VERSION 5.8 ;
BUSBITCHARS "[]" ;
DIVIDERCHAR "/" ;
UNITS
    DATABASE MICRONS 1000 ;
END UNITS

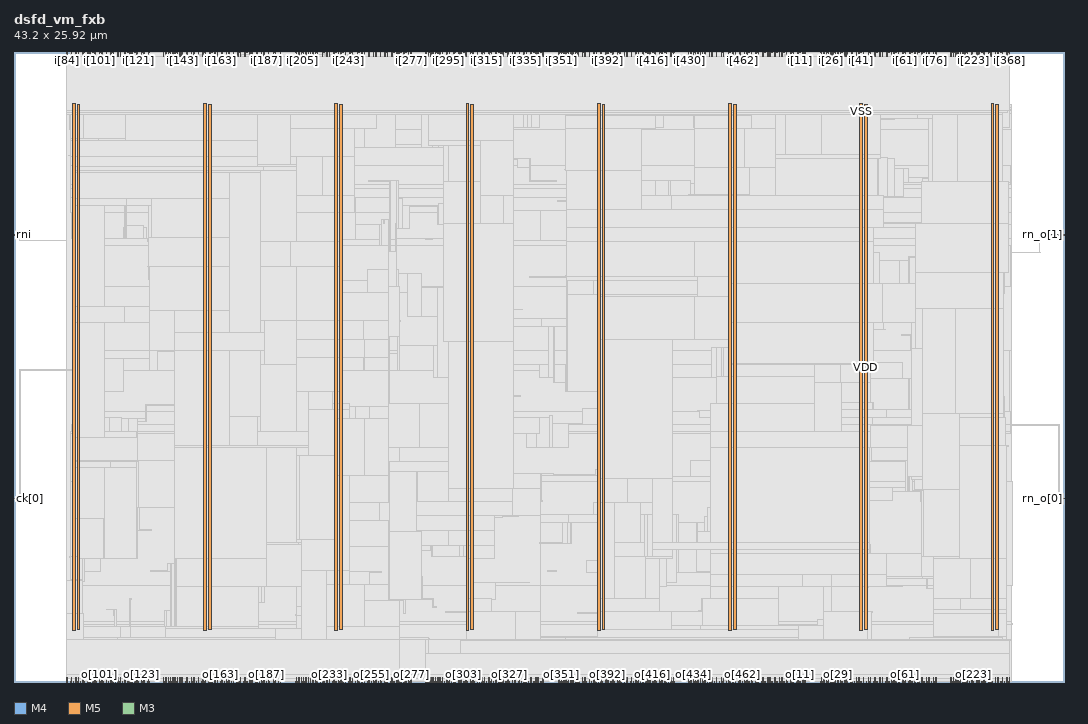
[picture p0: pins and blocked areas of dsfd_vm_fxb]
MACRO dsfd_vm_fxb
  FOREIGN dsfd_vm_fxb 0 0 ;
  CLASS BLOCK ;
  SIZE 43.2 BY 25.92 ;
  PIN ck[0]
    DIRECTION INPUT ;
    USE SIGNAL ;
    PORT
      LAYER M4 ;
        RECT  0 7.536 0.192 7.56 ;
    END
    PORT
      LAYER M4 ;
        RECT  0.156 7.536 0.275 7.56 ;
    END
  END ck[0]
  PIN i[0]
    DIRECTION INPUT ;
    USE SIGNAL ;
    PORT
      LAYER M5 ;
        RECT  31.488 25.728 31.512 25.92 ;
    END
  END i[0]
  PIN i[100]
    DIRECTION INPUT ;
    USE SIGNAL ;
    PORT
      LAYER M5 ;
        RECT  3.504 25.728 3.528 25.92 ;
    END
  END i[100]
  PIN i[101]
    DIRECTION INPUT ;
    USE SIGNAL ;
    PORT
      LAYER M3 ;
        RECT  3.528 25.882 3.546 25.92 ;
    END
  END i[101]
  PIN i[102]
    DIRECTION INPUT ;
    USE SIGNAL ;
    PORT
      LAYER M5 ;
        RECT  3.6 25.728 3.624 25.92 ;
    END
  END i[102]
  PIN i[103]
    DIRECTION INPUT ;
    USE SIGNAL ;
    PORT
      LAYER M3 ;
        RECT  3.672 25.882 3.69 25.92 ;
    END
  END i[103]
  PIN i[104]
    DIRECTION INPUT ;
    USE SIGNAL ;
    PORT
      LAYER M5 ;
        RECT  3.792 25.728 3.816 25.92 ;
    END
  END i[104]
  PIN i[105]
    DIRECTION INPUT ;
    USE SIGNAL ;
    PORT
      LAYER M3 ;
        RECT  3.888 25.882 3.906 25.92 ;
    END
  END i[105]
  PIN i[106]
    DIRECTION INPUT ;
    USE SIGNAL ;
    PORT
      LAYER M5 ;
        RECT  3.984 25.728 4.008 25.92 ;
    END
  END i[106]
  PIN i[107]
    DIRECTION INPUT ;
    USE SIGNAL ;
    PORT
      LAYER M3 ;
        RECT  4.032 25.882 4.05 25.92 ;
    END
  END i[107]
  PIN i[108]
    DIRECTION INPUT ;
    USE SIGNAL ;
    PORT
      LAYER M5 ;
        RECT  4.08 25.728 4.104 25.92 ;
    END
  END i[108]
  PIN i[109]
    DIRECTION INPUT ;
    USE SIGNAL ;
    PORT
      LAYER M3 ;
        RECT  4.176 25.882 4.194 25.92 ;
    END
  END i[109]
  PIN i[10]
    DIRECTION INPUT ;
    USE SIGNAL ;
    PORT
      LAYER M5 ;
        RECT  32.256 25.728 32.28 25.92 ;
    END
  END i[10]
  PIN i[110]
    DIRECTION INPUT ;
    USE SIGNAL ;
    PORT
      LAYER M5 ;
        RECT  4.272 25.728 4.296 25.92 ;
    END
  END i[110]
  PIN i[111]
    DIRECTION INPUT ;
    USE SIGNAL ;
    PORT
      LAYER M3 ;
        RECT  4.32 25.882 4.338 25.92 ;
    END
  END i[111]
  PIN i[112]
    DIRECTION INPUT ;
    USE SIGNAL ;
    PORT
      LAYER M5 ;
        RECT  4.368 25.728 4.392 25.92 ;
    END
  END i[112]
  PIN i[113]
    DIRECTION INPUT ;
    USE SIGNAL ;
    PORT
      LAYER M3 ;
        RECT  4.464 25.882 4.482 25.92 ;
    END
  END i[113]
  PIN i[114]
    DIRECTION INPUT ;
    USE SIGNAL ;
    PORT
      LAYER M5 ;
        RECT  4.56 25.728 4.584 25.92 ;
    END
  END i[114]
  PIN i[115]
    DIRECTION INPUT ;
    USE SIGNAL ;
    PORT
      LAYER M3 ;
        RECT  4.68 25.882 4.698 25.92 ;
    END
  END i[115]
  PIN i[116]
    DIRECTION INPUT ;
    USE SIGNAL ;
    PORT
      LAYER M5 ;
        RECT  4.752 25.728 4.776 25.92 ;
    END
  END i[116]
  PIN i[117]
    DIRECTION INPUT ;
    USE SIGNAL ;
    PORT
      LAYER M3 ;
        RECT  4.824 25.882 4.842 25.92 ;
    END
  END i[117]
  PIN i[118]
    DIRECTION INPUT ;
    USE SIGNAL ;
    PORT
      LAYER M5 ;
        RECT  4.848 25.728 4.872 25.92 ;
    END
  END i[118]
  PIN i[119]
    DIRECTION INPUT ;
    USE SIGNAL ;
    PORT
      LAYER M3 ;
        RECT  4.968 25.882 4.986 25.92 ;
    END
  END i[119]
  PIN i[11]
    DIRECTION INPUT ;
    USE SIGNAL ;
    PORT
      LAYER M3 ;
        RECT  32.328 25.882 32.346 25.92 ;
    END
  END i[11]
  PIN i[120]
    DIRECTION INPUT ;
    USE SIGNAL ;
    PORT
      LAYER M5 ;
        RECT  5.04 25.728 5.064 25.92 ;
    END
  END i[120]
  PIN i[121]
    DIRECTION INPUT ;
    USE SIGNAL ;
    PORT
      LAYER M3 ;
        RECT  5.112 25.882 5.13 25.92 ;
    END
  END i[121]
  PIN i[122]
    DIRECTION INPUT ;
    USE SIGNAL ;
    PORT
      LAYER M5 ;
        RECT  5.232 25.728 5.256 25.92 ;
    END
  END i[122]
  PIN i[123]
    DIRECTION INPUT ;
    USE SIGNAL ;
    PORT
      LAYER M3 ;
        RECT  5.256 25.882 5.274 25.92 ;
    END
  END i[123]
  PIN i[124]
    DIRECTION INPUT ;
    USE SIGNAL ;
    PORT
      LAYER M5 ;
        RECT  5.328 25.728 5.352 25.92 ;
    END
  END i[124]
  PIN i[125]
    DIRECTION INPUT ;
    USE SIGNAL ;
    PORT
      LAYER M3 ;
        RECT  5.472 25.882 5.49 25.92 ;
    END
  END i[125]
  PIN i[126]
    DIRECTION INPUT ;
    USE SIGNAL ;
    PORT
      LAYER M5 ;
        RECT  5.52 25.728 5.544 25.92 ;
    END
  END i[126]
  PIN i[127]
    DIRECTION INPUT ;
    USE SIGNAL ;
    PORT
      LAYER M3 ;
        RECT  5.544 25.882 5.562 25.92 ;
    END
  END i[127]
  PIN i[128]
    DIRECTION INPUT ;
    USE SIGNAL ;
    PORT
      LAYER M5 ;
        RECT  6.144 25.728 6.168 25.92 ;
    END
  END i[128]
  PIN i[129]
    DIRECTION INPUT ;
    USE SIGNAL ;
    PORT
      LAYER M3 ;
        RECT  6.192 25.882 6.21 25.92 ;
    END
  END i[129]
  PIN i[12]
    DIRECTION INPUT ;
    USE SIGNAL ;
    PORT
      LAYER M5 ;
        RECT  32.448 25.728 32.472 25.92 ;
    END
  END i[12]
  PIN i[130]
    DIRECTION INPUT ;
    USE SIGNAL ;
    PORT
      LAYER M5 ;
        RECT  6.24 25.728 6.264 25.92 ;
    END
  END i[130]
  PIN i[131]
    DIRECTION INPUT ;
    USE SIGNAL ;
    PORT
      LAYER M3 ;
        RECT  6.264 25.882 6.282 25.92 ;
    END
  END i[131]
  PIN i[132]
    DIRECTION INPUT ;
    USE SIGNAL ;
    PORT
      LAYER M5 ;
        RECT  6.336 25.728 6.36 25.92 ;
    END
  END i[132]
  PIN i[133]
    DIRECTION INPUT ;
    USE SIGNAL ;
    PORT
      LAYER M3 ;
        RECT  6.336 25.882 6.354 25.92 ;
    END
  END i[133]
  PIN i[134]
    DIRECTION INPUT ;
    USE SIGNAL ;
    PORT
      LAYER M5 ;
        RECT  6.432 25.728 6.456 25.92 ;
    END
  END i[134]
  PIN i[135]
    DIRECTION INPUT ;
    USE SIGNAL ;
    PORT
      LAYER M3 ;
        RECT  6.408 25.882 6.426 25.92 ;
    END
  END i[135]
  PIN i[136]
    DIRECTION INPUT ;
    USE SIGNAL ;
    PORT
      LAYER M5 ;
        RECT  6.528 25.728 6.552 25.92 ;
    END
  END i[136]
  PIN i[137]
    DIRECTION INPUT ;
    USE SIGNAL ;
    PORT
      LAYER M3 ;
        RECT  6.48 25.882 6.498 25.92 ;
    END
  END i[137]
  PIN i[138]
    DIRECTION INPUT ;
    USE SIGNAL ;
    PORT
      LAYER M5 ;
        RECT  6.624 25.728 6.648 25.92 ;
    END
  END i[138]
  PIN i[139]
    DIRECTION INPUT ;
    USE SIGNAL ;
    PORT
      LAYER M3 ;
        RECT  6.552 25.882 6.57 25.92 ;
    END
  END i[139]
  PIN i[13]
    DIRECTION INPUT ;
    USE SIGNAL ;
    PORT
      LAYER M3 ;
        RECT  32.472 25.882 32.49 25.92 ;
    END
  END i[13]
  PIN i[140]
    DIRECTION INPUT ;
    USE SIGNAL ;
    PORT
      LAYER M5 ;
        RECT  6.72 25.728 6.744 25.92 ;
    END
  END i[140]
  PIN i[141]
    DIRECTION INPUT ;
    USE SIGNAL ;
    PORT
      LAYER M3 ;
        RECT  6.696 25.882 6.714 25.92 ;
    END
  END i[141]
  PIN i[142]
    DIRECTION INPUT ;
    USE SIGNAL ;
    PORT
      LAYER M5 ;
        RECT  6.816 25.728 6.84 25.92 ;
    END
  END i[142]
  PIN i[143]
    DIRECTION INPUT ;
    USE SIGNAL ;
    PORT
      LAYER M3 ;
        RECT  6.912 25.882 6.93 25.92 ;
    END
  END i[143]
  PIN i[144]
    DIRECTION INPUT ;
    USE SIGNAL ;
    PORT
      LAYER M5 ;
        RECT  6.912 25.728 6.936 25.92 ;
    END
  END i[144]
  PIN i[145]
    DIRECTION INPUT ;
    USE SIGNAL ;
    PORT
      LAYER M3 ;
        RECT  7.056 25.882 7.074 25.92 ;
    END
  END i[145]
  PIN i[146]
    DIRECTION INPUT ;
    USE SIGNAL ;
    PORT
      LAYER M5 ;
        RECT  7.104 25.728 7.128 25.92 ;
    END
  END i[146]
  PIN i[147]
    DIRECTION INPUT ;
    USE SIGNAL ;
    PORT
      LAYER M3 ;
        RECT  7.2 25.882 7.218 25.92 ;
    END
  END i[147]
  PIN i[148]
    DIRECTION INPUT ;
    USE SIGNAL ;
    PORT
      LAYER M5 ;
        RECT  7.296 25.728 7.32 25.92 ;
    END
  END i[148]
  PIN i[149]
    DIRECTION INPUT ;
    USE SIGNAL ;
    PORT
      LAYER M3 ;
        RECT  7.344 25.882 7.362 25.92 ;
    END
  END i[149]
  PIN i[14]
    DIRECTION INPUT ;
    USE SIGNAL ;
    PORT
      LAYER M3 ;
        RECT  32.544 25.882 32.562 25.92 ;
    END
  END i[14]
  PIN i[150]
    DIRECTION INPUT ;
    USE SIGNAL ;
    PORT
      LAYER M5 ;
        RECT  7.392 25.728 7.416 25.92 ;
    END
  END i[150]
  PIN i[151]
    DIRECTION INPUT ;
    USE SIGNAL ;
    PORT
      LAYER M3 ;
        RECT  7.488 25.882 7.506 25.92 ;
    END
  END i[151]
  PIN i[152]
    DIRECTION INPUT ;
    USE SIGNAL ;
    PORT
      LAYER M5 ;
        RECT  7.584 25.728 7.608 25.92 ;
    END
  END i[152]
  PIN i[153]
    DIRECTION INPUT ;
    USE SIGNAL ;
    PORT
      LAYER M3 ;
        RECT  7.704 25.882 7.722 25.92 ;
    END
  END i[153]
  PIN i[154]
    DIRECTION INPUT ;
    USE SIGNAL ;
    PORT
      LAYER M5 ;
        RECT  7.776 25.728 7.8 25.92 ;
    END
  END i[154]
  PIN i[155]
    DIRECTION INPUT ;
    USE SIGNAL ;
    PORT
      LAYER M3 ;
        RECT  7.848 25.882 7.866 25.92 ;
    END
  END i[155]
  PIN i[156]
    DIRECTION INPUT ;
    USE SIGNAL ;
    PORT
      LAYER M5 ;
        RECT  7.872 25.728 7.896 25.92 ;
    END
  END i[156]
  PIN i[157]
    DIRECTION INPUT ;
    USE SIGNAL ;
    PORT
      LAYER M3 ;
        RECT  7.992 25.882 8.01 25.92 ;
    END
  END i[157]
  PIN i[158]
    DIRECTION INPUT ;
    USE SIGNAL ;
    PORT
      LAYER M5 ;
        RECT  8.064 25.728 8.088 25.92 ;
    END
  END i[158]
  PIN i[159]
    DIRECTION INPUT ;
    USE SIGNAL ;
    PORT
      LAYER M3 ;
        RECT  8.136 25.882 8.154 25.92 ;
    END
  END i[159]
  PIN i[15]
    DIRECTION INPUT ;
    USE SIGNAL ;
    PORT
      LAYER M5 ;
        RECT  33.216 25.728 33.24 25.92 ;
    END
  END i[15]
  PIN i[160]
    DIRECTION INPUT ;
    USE SIGNAL ;
    PORT
      LAYER M5 ;
        RECT  8.256 25.728 8.28 25.92 ;
    END
  END i[160]
  PIN i[161]
    DIRECTION INPUT ;
    USE SIGNAL ;
    PORT
      LAYER M3 ;
        RECT  8.28 25.882 8.298 25.92 ;
    END
  END i[161]
  PIN i[162]
    DIRECTION INPUT ;
    USE SIGNAL ;
    PORT
      LAYER M5 ;
        RECT  8.352 25.728 8.376 25.92 ;
    END
  END i[162]
  PIN i[163]
    DIRECTION INPUT ;
    USE SIGNAL ;
    PORT
      LAYER M3 ;
        RECT  8.496 25.882 8.514 25.92 ;
    END
  END i[163]
  PIN i[164]
    DIRECTION INPUT ;
    USE SIGNAL ;
    PORT
      LAYER M5 ;
        RECT  8.544 25.728 8.568 25.92 ;
    END
  END i[164]
  PIN i[165]
    DIRECTION INPUT ;
    USE SIGNAL ;
    PORT
      LAYER M3 ;
        RECT  8.64 25.882 8.658 25.92 ;
    END
  END i[165]
  PIN i[166]
    DIRECTION INPUT ;
    USE SIGNAL ;
    PORT
      LAYER M5 ;
        RECT  8.736 25.728 8.76 25.92 ;
    END
  END i[166]
  PIN i[167]
    DIRECTION INPUT ;
    USE SIGNAL ;
    PORT
      LAYER M3 ;
        RECT  8.784 25.882 8.802 25.92 ;
    END
  END i[167]
  PIN i[168]
    DIRECTION INPUT ;
    USE SIGNAL ;
    PORT
      LAYER M5 ;
        RECT  8.832 25.728 8.856 25.92 ;
    END
  END i[168]
  PIN i[169]
    DIRECTION INPUT ;
    USE SIGNAL ;
    PORT
      LAYER M3 ;
        RECT  8.928 25.882 8.946 25.92 ;
    END
  END i[169]
  PIN i[16]
    DIRECTION INPUT ;
    USE SIGNAL ;
    PORT
      LAYER M3 ;
        RECT  33.192 25.882 33.21 25.92 ;
    END
  END i[16]
  PIN i[170]
    DIRECTION INPUT ;
    USE SIGNAL ;
    PORT
      LAYER M5 ;
        RECT  9.024 25.728 9.048 25.92 ;
    END
  END i[170]
  PIN i[171]
    DIRECTION INPUT ;
    USE SIGNAL ;
    PORT
      LAYER M3 ;
        RECT  9.144 25.882 9.162 25.92 ;
    END
  END i[171]
  PIN i[172]
    DIRECTION INPUT ;
    USE SIGNAL ;
    PORT
      LAYER M5 ;
        RECT  9.216 25.728 9.24 25.92 ;
    END
  END i[172]
  PIN i[173]
    DIRECTION INPUT ;
    USE SIGNAL ;
    PORT
      LAYER M3 ;
        RECT  9.288 25.882 9.306 25.92 ;
    END
  END i[173]
  PIN i[174]
    DIRECTION INPUT ;
    USE SIGNAL ;
    PORT
      LAYER M5 ;
        RECT  9.312 25.728 9.336 25.92 ;
    END
  END i[174]
  PIN i[175]
    DIRECTION INPUT ;
    USE SIGNAL ;
    PORT
      LAYER M3 ;
        RECT  9.432 25.882 9.45 25.92 ;
    END
  END i[175]
  PIN i[176]
    DIRECTION INPUT ;
    USE SIGNAL ;
    PORT
      LAYER M5 ;
        RECT  9.504 25.728 9.528 25.92 ;
    END
  END i[176]
  PIN i[177]
    DIRECTION INPUT ;
    USE SIGNAL ;
    PORT
      LAYER M3 ;
        RECT  9.576 25.882 9.594 25.92 ;
    END
  END i[177]
  PIN i[178]
    DIRECTION INPUT ;
    USE SIGNAL ;
    PORT
      LAYER M5 ;
        RECT  9.696 25.728 9.72 25.92 ;
    END
  END i[178]
  PIN i[179]
    DIRECTION INPUT ;
    USE SIGNAL ;
    PORT
      LAYER M3 ;
        RECT  9.72 25.882 9.738 25.92 ;
    END
  END i[179]
  PIN i[17]
    DIRECTION INPUT ;
    USE SIGNAL ;
    PORT
      LAYER M5 ;
        RECT  33.312 25.728 33.336 25.92 ;
    END
  END i[17]
  PIN i[180]
    DIRECTION INPUT ;
    USE SIGNAL ;
    PORT
      LAYER M5 ;
        RECT  9.792 25.728 9.816 25.92 ;
    END
  END i[180]
  PIN i[181]
    DIRECTION INPUT ;
    USE SIGNAL ;
    PORT
      LAYER M3 ;
        RECT  9.936 25.882 9.954 25.92 ;
    END
  END i[181]
  PIN i[182]
    DIRECTION INPUT ;
    USE SIGNAL ;
    PORT
      LAYER M5 ;
        RECT  9.984 25.728 10.008 25.92 ;
    END
  END i[182]
  PIN i[183]
    DIRECTION INPUT ;
    USE SIGNAL ;
    PORT
      LAYER M3 ;
        RECT  10.08 25.882 10.098 25.92 ;
    END
  END i[183]
  PIN i[184]
    DIRECTION INPUT ;
    USE SIGNAL ;
    PORT
      LAYER M5 ;
        RECT  10.176 25.728 10.2 25.92 ;
    END
  END i[184]
  PIN i[185]
    DIRECTION INPUT ;
    USE SIGNAL ;
    PORT
      LAYER M3 ;
        RECT  10.224 25.882 10.242 25.92 ;
    END
  END i[185]
  PIN i[186]
    DIRECTION INPUT ;
    USE SIGNAL ;
    PORT
      LAYER M5 ;
        RECT  10.272 25.728 10.296 25.92 ;
    END
  END i[186]
  PIN i[187]
    DIRECTION INPUT ;
    USE SIGNAL ;
    PORT
      LAYER M3 ;
        RECT  10.368 25.882 10.386 25.92 ;
    END
  END i[187]
  PIN i[188]
    DIRECTION INPUT ;
    USE SIGNAL ;
    PORT
      LAYER M5 ;
        RECT  10.464 25.728 10.488 25.92 ;
    END
  END i[188]
  PIN i[189]
    DIRECTION INPUT ;
    USE SIGNAL ;
    PORT
      LAYER M3 ;
        RECT  10.512 25.882 10.53 25.92 ;
    END
  END i[189]
  PIN i[18]
    DIRECTION INPUT ;
    USE SIGNAL ;
    PORT
      LAYER M3 ;
        RECT  33.264 25.882 33.282 25.92 ;
    END
  END i[18]
  PIN i[190]
    DIRECTION INPUT ;
    USE SIGNAL ;
    PORT
      LAYER M5 ;
        RECT  10.656 25.728 10.68 25.92 ;
    END
  END i[190]
  PIN i[191]
    DIRECTION INPUT ;
    USE SIGNAL ;
    PORT
      LAYER M3 ;
        RECT  10.728 25.882 10.746 25.92 ;
    END
  END i[191]
  PIN i[192]
    DIRECTION INPUT ;
    USE SIGNAL ;
    PORT
      LAYER M5 ;
        RECT  10.752 25.728 10.776 25.92 ;
    END
  END i[192]
  PIN i[193]
    DIRECTION INPUT ;
    USE SIGNAL ;
    PORT
      LAYER M3 ;
        RECT  10.872 25.882 10.89 25.92 ;
    END
  END i[193]
  PIN i[194]
    DIRECTION INPUT ;
    USE SIGNAL ;
    PORT
      LAYER M5 ;
        RECT  10.944 25.728 10.968 25.92 ;
    END
  END i[194]
  PIN i[195]
    DIRECTION INPUT ;
    USE SIGNAL ;
    PORT
      LAYER M3 ;
        RECT  10.944 25.882 10.962 25.92 ;
    END
  END i[195]
  PIN i[196]
    DIRECTION INPUT ;
    USE SIGNAL ;
    PORT
      LAYER M5 ;
        RECT  11.616 25.728 11.64 25.92 ;
    END
  END i[196]
  PIN i[197]
    DIRECTION INPUT ;
    USE SIGNAL ;
    PORT
      LAYER M3 ;
        RECT  11.592 25.882 11.61 25.92 ;
    END
  END i[197]
  PIN i[198]
    DIRECTION INPUT ;
    USE SIGNAL ;
    PORT
      LAYER M5 ;
        RECT  11.712 25.728 11.736 25.92 ;
    END
  END i[198]
  PIN i[199]
    DIRECTION INPUT ;
    USE SIGNAL ;
    PORT
      LAYER M3 ;
        RECT  11.664 25.882 11.682 25.92 ;
    END
  END i[199]
  PIN i[19]
    DIRECTION INPUT ;
    USE SIGNAL ;
    PORT
      LAYER M5 ;
        RECT  33.408 25.728 33.432 25.92 ;
    END
  END i[19]
  PIN i[1]
    DIRECTION INPUT ;
    USE SIGNAL ;
    PORT
      LAYER M3 ;
        RECT  31.536 25.882 31.554 25.92 ;
    END
  END i[1]
  PIN i[200]
    DIRECTION INPUT ;
    USE SIGNAL ;
    PORT
      LAYER M5 ;
        RECT  11.808 25.728 11.832 25.92 ;
    END
  END i[200]
  PIN i[201]
    DIRECTION INPUT ;
    USE SIGNAL ;
    PORT
      LAYER M3 ;
        RECT  11.736 25.882 11.754 25.92 ;
    END
  END i[201]
  PIN i[202]
    DIRECTION INPUT ;
    USE SIGNAL ;
    PORT
      LAYER M5 ;
        RECT  11.904 25.728 11.928 25.92 ;
    END
  END i[202]
  PIN i[203]
    DIRECTION INPUT ;
    USE SIGNAL ;
    PORT
      LAYER M3 ;
        RECT  11.808 25.882 11.826 25.92 ;
    END
  END i[203]
  PIN i[204]
    DIRECTION INPUT ;
    USE SIGNAL ;
    PORT
      LAYER M5 ;
        RECT  12 25.728 12.024 25.92 ;
    END
  END i[204]
  PIN i[205]
    DIRECTION INPUT ;
    USE SIGNAL ;
    PORT
      LAYER M3 ;
        RECT  11.88 25.882 11.898 25.92 ;
    END
  END i[205]
  PIN i[206]
    DIRECTION INPUT ;
    USE SIGNAL ;
    PORT
      LAYER M5 ;
        RECT  12.096 25.728 12.12 25.92 ;
    END
  END i[206]
  PIN i[207]
    DIRECTION INPUT ;
    USE SIGNAL ;
    PORT
      LAYER M3 ;
        RECT  11.952 25.882 11.97 25.92 ;
    END
  END i[207]
  PIN i[208]
    DIRECTION INPUT ;
    USE SIGNAL ;
    PORT
      LAYER M5 ;
        RECT  12.192 25.728 12.216 25.92 ;
    END
  END i[208]
  PIN i[209]
    DIRECTION INPUT ;
    USE SIGNAL ;
    PORT
      LAYER M3 ;
        RECT  12.096 25.882 12.114 25.92 ;
    END
  END i[209]
  PIN i[20]
    DIRECTION INPUT ;
    USE SIGNAL ;
    PORT
      LAYER M3 ;
        RECT  33.336 25.882 33.354 25.92 ;
    END
  END i[20]
  PIN i[210]
    DIRECTION INPUT ;
    USE SIGNAL ;
    PORT
      LAYER M5 ;
        RECT  12.288 25.728 12.312 25.92 ;
    END
  END i[210]
  PIN i[211]
    DIRECTION INPUT ;
    USE SIGNAL ;
    PORT
      LAYER M3 ;
        RECT  12.312 25.882 12.33 25.92 ;
    END
  END i[211]
  PIN i[212]
    DIRECTION INPUT ;
    USE SIGNAL ;
    PORT
      LAYER M5 ;
        RECT  38.832 25.728 38.856 25.92 ;
    END
  END i[212]
  PIN i[213]
    DIRECTION INPUT ;
    USE SIGNAL ;
    PORT
      LAYER M3 ;
        RECT  38.808 25.882 38.826 25.92 ;
    END
  END i[213]
  PIN i[214]
    DIRECTION INPUT ;
    USE SIGNAL ;
    PORT
      LAYER M5 ;
        RECT  38.928 25.728 38.952 25.92 ;
    END
  END i[214]
  PIN i[215]
    DIRECTION INPUT ;
    USE SIGNAL ;
    PORT
      LAYER M3 ;
        RECT  38.88 25.882 38.898 25.92 ;
    END
  END i[215]
  PIN i[216]
    DIRECTION INPUT ;
    USE SIGNAL ;
    PORT
      LAYER M5 ;
        RECT  39.024 25.728 39.048 25.92 ;
    END
  END i[216]
  PIN i[217]
    DIRECTION INPUT ;
    USE SIGNAL ;
    PORT
      LAYER M3 ;
        RECT  39.024 25.882 39.042 25.92 ;
    END
  END i[217]
  PIN i[218]
    DIRECTION INPUT ;
    USE SIGNAL ;
    PORT
      LAYER M5 ;
        RECT  39.12 25.728 39.144 25.92 ;
    END
  END i[218]
  PIN i[219]
    DIRECTION INPUT ;
    USE SIGNAL ;
    PORT
      LAYER M3 ;
        RECT  39.168 25.882 39.186 25.92 ;
    END
  END i[219]
  PIN i[21]
    DIRECTION INPUT ;
    USE SIGNAL ;
    PORT
      LAYER M5 ;
        RECT  33.504 25.728 33.528 25.92 ;
    END
  END i[21]
  PIN i[220]
    DIRECTION INPUT ;
    USE SIGNAL ;
    PORT
      LAYER M5 ;
        RECT  39.216 25.728 39.24 25.92 ;
    END
  END i[220]
  PIN i[221]
    DIRECTION INPUT ;
    USE SIGNAL ;
    PORT
      LAYER M3 ;
        RECT  39.312 25.882 39.33 25.92 ;
    END
  END i[221]
  PIN i[222]
    DIRECTION INPUT ;
    USE SIGNAL ;
    PORT
      LAYER M5 ;
        RECT  39.408 25.728 39.432 25.92 ;
    END
  END i[222]
  PIN i[223]
    DIRECTION INPUT ;
    USE SIGNAL ;
    PORT
      LAYER M3 ;
        RECT  39.456 25.882 39.474 25.92 ;
    END
  END i[223]
  PIN i[224]
    DIRECTION INPUT ;
    USE SIGNAL ;
    PORT
      LAYER M5 ;
        RECT  39.6 25.728 39.624 25.92 ;
    END
  END i[224]
  PIN i[225]
    DIRECTION INPUT ;
    USE SIGNAL ;
    PORT
      LAYER M3 ;
        RECT  39.672 25.882 39.69 25.92 ;
    END
  END i[225]
  PIN i[226]
    DIRECTION INPUT ;
    USE SIGNAL ;
    PORT
      LAYER M5 ;
        RECT  12.384 25.728 12.408 25.92 ;
    END
  END i[226]
  PIN i[227]
    DIRECTION INPUT ;
    USE SIGNAL ;
    PORT
      LAYER M3 ;
        RECT  12.456 25.882 12.474 25.92 ;
    END
  END i[227]
  PIN i[228]
    DIRECTION INPUT ;
    USE SIGNAL ;
    PORT
      LAYER M5 ;
        RECT  12.48 25.728 12.504 25.92 ;
    END
  END i[228]
  PIN i[229]
    DIRECTION INPUT ;
    USE SIGNAL ;
    PORT
      LAYER M3 ;
        RECT  12.6 25.882 12.618 25.92 ;
    END
  END i[229]
  PIN i[22]
    DIRECTION INPUT ;
    USE SIGNAL ;
    PORT
      LAYER M3 ;
        RECT  33.408 25.882 33.426 25.92 ;
    END
  END i[22]
  PIN i[230]
    DIRECTION INPUT ;
    USE SIGNAL ;
    PORT
      LAYER M5 ;
        RECT  12.672 25.728 12.696 25.92 ;
    END
  END i[230]
  PIN i[231]
    DIRECTION INPUT ;
    USE SIGNAL ;
    PORT
      LAYER M3 ;
        RECT  12.744 25.882 12.762 25.92 ;
    END
  END i[231]
  PIN i[232]
    DIRECTION INPUT ;
    USE SIGNAL ;
    PORT
      LAYER M5 ;
        RECT  12.864 25.728 12.888 25.92 ;
    END
  END i[232]
  PIN i[233]
    DIRECTION INPUT ;
    USE SIGNAL ;
    PORT
      LAYER M3 ;
        RECT  12.96 25.882 12.978 25.92 ;
    END
  END i[233]
  PIN i[234]
    DIRECTION INPUT ;
    USE SIGNAL ;
    PORT
      LAYER M5 ;
        RECT  12.96 25.728 12.984 25.92 ;
    END
  END i[234]
  PIN i[235]
    DIRECTION INPUT ;
    USE SIGNAL ;
    PORT
      LAYER M3 ;
        RECT  13.104 25.882 13.122 25.92 ;
    END
  END i[235]
  PIN i[236]
    DIRECTION INPUT ;
    USE SIGNAL ;
    PORT
      LAYER M5 ;
        RECT  13.152 25.728 13.176 25.92 ;
    END
  END i[236]
  PIN i[237]
    DIRECTION INPUT ;
    USE SIGNAL ;
    PORT
      LAYER M3 ;
        RECT  13.248 25.882 13.266 25.92 ;
    END
  END i[237]
  PIN i[238]
    DIRECTION INPUT ;
    USE SIGNAL ;
    PORT
      LAYER M5 ;
        RECT  13.344 25.728 13.368 25.92 ;
    END
  END i[238]
  PIN i[239]
    DIRECTION INPUT ;
    USE SIGNAL ;
    PORT
      LAYER M3 ;
        RECT  13.392 25.882 13.41 25.92 ;
    END
  END i[239]
  PIN i[23]
    DIRECTION INPUT ;
    USE SIGNAL ;
    PORT
      LAYER M5 ;
        RECT  33.6 25.728 33.624 25.92 ;
    END
  END i[23]
  PIN i[240]
    DIRECTION INPUT ;
    USE SIGNAL ;
    PORT
      LAYER M5 ;
        RECT  13.44 25.728 13.464 25.92 ;
    END
  END i[240]
  PIN i[241]
    DIRECTION INPUT ;
    USE SIGNAL ;
    PORT
      LAYER M3 ;
        RECT  13.536 25.882 13.554 25.92 ;
    END
  END i[241]
  PIN i[242]
    DIRECTION INPUT ;
    USE SIGNAL ;
    PORT
      LAYER M5 ;
        RECT  13.632 25.728 13.656 25.92 ;
    END
  END i[242]
  PIN i[243]
    DIRECTION INPUT ;
    USE SIGNAL ;
    PORT
      LAYER M3 ;
        RECT  13.752 25.882 13.77 25.92 ;
    END
  END i[243]
  PIN i[244]
    DIRECTION INPUT ;
    USE SIGNAL ;
    PORT
      LAYER M5 ;
        RECT  13.824 25.728 13.848 25.92 ;
    END
  END i[244]
  PIN i[245]
    DIRECTION INPUT ;
    USE SIGNAL ;
    PORT
      LAYER M3 ;
        RECT  13.896 25.882 13.914 25.92 ;
    END
  END i[245]
  PIN i[246]
    DIRECTION INPUT ;
    USE SIGNAL ;
    PORT
      LAYER M5 ;
        RECT  13.92 25.728 13.944 25.92 ;
    END
  END i[246]
  PIN i[247]
    DIRECTION INPUT ;
    USE SIGNAL ;
    PORT
      LAYER M3 ;
        RECT  14.04 25.882 14.058 25.92 ;
    END
  END i[247]
  PIN i[248]
    DIRECTION INPUT ;
    USE SIGNAL ;
    PORT
      LAYER M5 ;
        RECT  14.112 25.728 14.136 25.92 ;
    END
  END i[248]
  PIN i[249]
    DIRECTION INPUT ;
    USE SIGNAL ;
    PORT
      LAYER M3 ;
        RECT  14.184 25.882 14.202 25.92 ;
    END
  END i[249]
  PIN i[24]
    DIRECTION INPUT ;
    USE SIGNAL ;
    PORT
      LAYER M3 ;
        RECT  33.48 25.882 33.498 25.92 ;
    END
  END i[24]
  PIN i[250]
    DIRECTION INPUT ;
    USE SIGNAL ;
    PORT
      LAYER M5 ;
        RECT  14.304 25.728 14.328 25.92 ;
    END
  END i[250]
  PIN i[251]
    DIRECTION INPUT ;
    USE SIGNAL ;
    PORT
      LAYER M3 ;
        RECT  14.328 25.882 14.346 25.92 ;
    END
  END i[251]
  PIN i[252]
    DIRECTION INPUT ;
    USE SIGNAL ;
    PORT
      LAYER M5 ;
        RECT  14.4 25.728 14.424 25.92 ;
    END
  END i[252]
  PIN i[253]
    DIRECTION INPUT ;
    USE SIGNAL ;
    PORT
      LAYER M3 ;
        RECT  14.544 25.882 14.562 25.92 ;
    END
  END i[253]
  PIN i[254]
    DIRECTION INPUT ;
    USE SIGNAL ;
    PORT
      LAYER M5 ;
        RECT  14.592 25.728 14.616 25.92 ;
    END
  END i[254]
  PIN i[255]
    DIRECTION INPUT ;
    USE SIGNAL ;
    PORT
      LAYER M3 ;
        RECT  14.688 25.882 14.706 25.92 ;
    END
  END i[255]
  PIN i[256]
    DIRECTION INPUT ;
    USE SIGNAL ;
    PORT
      LAYER M5 ;
        RECT  14.784 25.728 14.808 25.92 ;
    END
  END i[256]
  PIN i[257]
    DIRECTION INPUT ;
    USE SIGNAL ;
    PORT
      LAYER M3 ;
        RECT  14.832 25.882 14.85 25.92 ;
    END
  END i[257]
  PIN i[258]
    DIRECTION INPUT ;
    USE SIGNAL ;
    PORT
      LAYER M5 ;
        RECT  14.88 25.728 14.904 25.92 ;
    END
  END i[258]
  PIN i[259]
    DIRECTION INPUT ;
    USE SIGNAL ;
    PORT
      LAYER M3 ;
        RECT  14.976 25.882 14.994 25.92 ;
    END
  END i[259]
  PIN i[25]
    DIRECTION INPUT ;
    USE SIGNAL ;
    PORT
      LAYER M5 ;
        RECT  33.696 25.728 33.72 25.92 ;
    END
  END i[25]
  PIN i[260]
    DIRECTION INPUT ;
    USE SIGNAL ;
    PORT
      LAYER M5 ;
        RECT  15.072 25.728 15.096 25.92 ;
    END
  END i[260]
  PIN i[261]
    DIRECTION INPUT ;
    USE SIGNAL ;
    PORT
      LAYER M3 ;
        RECT  15.12 25.882 15.138 25.92 ;
    END
  END i[261]
  PIN i[262]
    DIRECTION INPUT ;
    USE SIGNAL ;
    PORT
      LAYER M5 ;
        RECT  15.264 25.728 15.288 25.92 ;
    END
  END i[262]
  PIN i[263]
    DIRECTION INPUT ;
    USE SIGNAL ;
    PORT
      LAYER M3 ;
        RECT  15.336 25.882 15.354 25.92 ;
    END
  END i[263]
  PIN i[264]
    DIRECTION INPUT ;
    USE SIGNAL ;
    PORT
      LAYER M5 ;
        RECT  15.36 25.728 15.384 25.92 ;
    END
  END i[264]
  PIN i[265]
    DIRECTION INPUT ;
    USE SIGNAL ;
    PORT
      LAYER M3 ;
        RECT  15.48 25.882 15.498 25.92 ;
    END
  END i[265]
  PIN i[266]
    DIRECTION INPUT ;
    USE SIGNAL ;
    PORT
      LAYER M5 ;
        RECT  15.552 25.728 15.576 25.92 ;
    END
  END i[266]
  PIN i[267]
    DIRECTION INPUT ;
    USE SIGNAL ;
    PORT
      LAYER M3 ;
        RECT  15.624 25.882 15.642 25.92 ;
    END
  END i[267]
  PIN i[268]
    DIRECTION INPUT ;
    USE SIGNAL ;
    PORT
      LAYER M5 ;
        RECT  15.744 25.728 15.768 25.92 ;
    END
  END i[268]
  PIN i[269]
    DIRECTION INPUT ;
    USE SIGNAL ;
    PORT
      LAYER M3 ;
        RECT  15.768 25.882 15.786 25.92 ;
    END
  END i[269]
  PIN i[26]
    DIRECTION INPUT ;
    USE SIGNAL ;
    PORT
      LAYER M3 ;
        RECT  33.624 25.882 33.642 25.92 ;
    END
  END i[26]
  PIN i[270]
    DIRECTION INPUT ;
    USE SIGNAL ;
    PORT
      LAYER M5 ;
        RECT  15.84 25.728 15.864 25.92 ;
    END
  END i[270]
  PIN i[271]
    DIRECTION INPUT ;
    USE SIGNAL ;
    PORT
      LAYER M3 ;
        RECT  15.912 25.882 15.93 25.92 ;
    END
  END i[271]
  PIN i[272]
    DIRECTION INPUT ;
    USE SIGNAL ;
    PORT
      LAYER M5 ;
        RECT  16.032 25.728 16.056 25.92 ;
    END
  END i[272]
  PIN i[273]
    DIRECTION INPUT ;
    USE SIGNAL ;
    PORT
      LAYER M3 ;
        RECT  16.128 25.882 16.146 25.92 ;
    END
  END i[273]
  PIN i[274]
    DIRECTION INPUT ;
    USE SIGNAL ;
    PORT
      LAYER M5 ;
        RECT  16.224 25.728 16.248 25.92 ;
    END
  END i[274]
  PIN i[275]
    DIRECTION INPUT ;
    USE SIGNAL ;
    PORT
      LAYER M3 ;
        RECT  16.272 25.882 16.29 25.92 ;
    END
  END i[275]
  PIN i[276]
    DIRECTION INPUT ;
    USE SIGNAL ;
    PORT
      LAYER M5 ;
        RECT  16.32 25.728 16.344 25.92 ;
    END
  END i[276]
  PIN i[277]
    DIRECTION INPUT ;
    USE SIGNAL ;
    PORT
      LAYER M3 ;
        RECT  16.344 25.882 16.362 25.92 ;
    END
  END i[277]
  PIN i[278]
    DIRECTION INPUT ;
    USE SIGNAL ;
    PORT
      LAYER M5 ;
        RECT  16.944 25.728 16.968 25.92 ;
    END
  END i[278]
  PIN i[279]
    DIRECTION INPUT ;
    USE SIGNAL ;
    PORT
      LAYER M3 ;
        RECT  16.992 25.882 17.01 25.92 ;
    END
  END i[279]
  PIN i[27]
    DIRECTION INPUT ;
    USE SIGNAL ;
    PORT
      LAYER M5 ;
        RECT  33.792 25.728 33.816 25.92 ;
    END
  END i[27]
  PIN i[280]
    DIRECTION INPUT ;
    USE SIGNAL ;
    PORT
      LAYER M5 ;
        RECT  17.04 25.728 17.064 25.92 ;
    END
  END i[280]
  PIN i[281]
    DIRECTION INPUT ;
    USE SIGNAL ;
    PORT
      LAYER M3 ;
        RECT  17.064 25.882 17.082 25.92 ;
    END
  END i[281]
  PIN i[282]
    DIRECTION INPUT ;
    USE SIGNAL ;
    PORT
      LAYER M5 ;
        RECT  17.136 25.728 17.16 25.92 ;
    END
  END i[282]
  PIN i[283]
    DIRECTION INPUT ;
    USE SIGNAL ;
    PORT
      LAYER M3 ;
        RECT  17.136 25.882 17.154 25.92 ;
    END
  END i[283]
  PIN i[284]
    DIRECTION INPUT ;
    USE SIGNAL ;
    PORT
      LAYER M5 ;
        RECT  17.232 25.728 17.256 25.92 ;
    END
  END i[284]
  PIN i[285]
    DIRECTION INPUT ;
    USE SIGNAL ;
    PORT
      LAYER M3 ;
        RECT  17.208 25.882 17.226 25.92 ;
    END
  END i[285]
  PIN i[286]
    DIRECTION INPUT ;
    USE SIGNAL ;
    PORT
      LAYER M5 ;
        RECT  17.328 25.728 17.352 25.92 ;
    END
  END i[286]
  PIN i[287]
    DIRECTION INPUT ;
    USE SIGNAL ;
    PORT
      LAYER M3 ;
        RECT  17.28 25.882 17.298 25.92 ;
    END
  END i[287]
  PIN i[288]
    DIRECTION INPUT ;
    USE SIGNAL ;
    PORT
      LAYER M5 ;
        RECT  17.424 25.728 17.448 25.92 ;
    END
  END i[288]
  PIN i[289]
    DIRECTION INPUT ;
    USE SIGNAL ;
    PORT
      LAYER M3 ;
        RECT  17.352 25.882 17.37 25.92 ;
    END
  END i[289]
  PIN i[28]
    DIRECTION INPUT ;
    USE SIGNAL ;
    PORT
      LAYER M5 ;
        RECT  33.888 25.728 33.912 25.92 ;
    END
  END i[28]
  PIN i[290]
    DIRECTION INPUT ;
    USE SIGNAL ;
    PORT
      LAYER M5 ;
        RECT  17.52 25.728 17.544 25.92 ;
    END
  END i[290]
  PIN i[291]
    DIRECTION INPUT ;
    USE SIGNAL ;
    PORT
      LAYER M3 ;
        RECT  17.568 25.882 17.586 25.92 ;
    END
  END i[291]
  PIN i[292]
    DIRECTION INPUT ;
    USE SIGNAL ;
    PORT
      LAYER M5 ;
        RECT  17.616 25.728 17.64 25.92 ;
    END
  END i[292]
  PIN i[293]
    DIRECTION INPUT ;
    USE SIGNAL ;
    PORT
      LAYER M3 ;
        RECT  17.712 25.882 17.73 25.92 ;
    END
  END i[293]
  PIN i[294]
    DIRECTION INPUT ;
    USE SIGNAL ;
    PORT
      LAYER M5 ;
        RECT  17.808 25.728 17.832 25.92 ;
    END
  END i[294]
  PIN i[295]
    DIRECTION INPUT ;
    USE SIGNAL ;
    PORT
      LAYER M3 ;
        RECT  17.856 25.882 17.874 25.92 ;
    END
  END i[295]
  PIN i[296]
    DIRECTION INPUT ;
    USE SIGNAL ;
    PORT
      LAYER M5 ;
        RECT  17.904 25.728 17.928 25.92 ;
    END
  END i[296]
  PIN i[297]
    DIRECTION INPUT ;
    USE SIGNAL ;
    PORT
      LAYER M3 ;
        RECT  18 25.882 18.018 25.92 ;
    END
  END i[297]
  PIN i[298]
    DIRECTION INPUT ;
    USE SIGNAL ;
    PORT
      LAYER M5 ;
        RECT  18.096 25.728 18.12 25.92 ;
    END
  END i[298]
  PIN i[299]
    DIRECTION INPUT ;
    USE SIGNAL ;
    PORT
      LAYER M3 ;
        RECT  18.144 25.882 18.162 25.92 ;
    END
  END i[299]
  PIN i[29]
    DIRECTION INPUT ;
    USE SIGNAL ;
    PORT
      LAYER M3 ;
        RECT  33.912 25.882 33.93 25.92 ;
    END
  END i[29]
  PIN i[2]
    DIRECTION INPUT ;
    USE SIGNAL ;
    PORT
      LAYER M5 ;
        RECT  31.584 25.728 31.608 25.92 ;
    END
  END i[2]
  PIN i[300]
    DIRECTION INPUT ;
    USE SIGNAL ;
    PORT
      LAYER M5 ;
        RECT  18.288 25.728 18.312 25.92 ;
    END
  END i[300]
  PIN i[301]
    DIRECTION INPUT ;
    USE SIGNAL ;
    PORT
      LAYER M3 ;
        RECT  18.36 25.882 18.378 25.92 ;
    END
  END i[301]
  PIN i[302]
    DIRECTION INPUT ;
    USE SIGNAL ;
    PORT
      LAYER M5 ;
        RECT  18.384 25.728 18.408 25.92 ;
    END
  END i[302]
  PIN i[303]
    DIRECTION INPUT ;
    USE SIGNAL ;
    PORT
      LAYER M3 ;
        RECT  18.504 25.882 18.522 25.92 ;
    END
  END i[303]
  PIN i[304]
    DIRECTION INPUT ;
    USE SIGNAL ;
    PORT
      LAYER M5 ;
        RECT  18.576 25.728 18.6 25.92 ;
    END
  END i[304]
  PIN i[305]
    DIRECTION INPUT ;
    USE SIGNAL ;
    PORT
      LAYER M3 ;
        RECT  18.648 25.882 18.666 25.92 ;
    END
  END i[305]
  PIN i[306]
    DIRECTION INPUT ;
    USE SIGNAL ;
    PORT
      LAYER M5 ;
        RECT  18.768 25.728 18.792 25.92 ;
    END
  END i[306]
  PIN i[307]
    DIRECTION INPUT ;
    USE SIGNAL ;
    PORT
      LAYER M3 ;
        RECT  18.792 25.882 18.81 25.92 ;
    END
  END i[307]
  PIN i[308]
    DIRECTION INPUT ;
    USE SIGNAL ;
    PORT
      LAYER M5 ;
        RECT  18.864 25.728 18.888 25.92 ;
    END
  END i[308]
  PIN i[309]
    DIRECTION INPUT ;
    USE SIGNAL ;
    PORT
      LAYER M3 ;
        RECT  18.936 25.882 18.954 25.92 ;
    END
  END i[309]
  PIN i[30]
    DIRECTION INPUT ;
    USE SIGNAL ;
    PORT
      LAYER M5 ;
        RECT  33.984 25.728 34.008 25.92 ;
    END
  END i[30]
  PIN i[310]
    DIRECTION INPUT ;
    USE SIGNAL ;
    PORT
      LAYER M5 ;
        RECT  19.056 25.728 19.08 25.92 ;
    END
  END i[310]
  PIN i[311]
    DIRECTION INPUT ;
    USE SIGNAL ;
    PORT
      LAYER M3 ;
        RECT  19.152 25.882 19.17 25.92 ;
    END
  END i[311]
  PIN i[312]
    DIRECTION INPUT ;
    USE SIGNAL ;
    PORT
      LAYER M5 ;
        RECT  19.248 25.728 19.272 25.92 ;
    END
  END i[312]
  PIN i[313]
    DIRECTION INPUT ;
    USE SIGNAL ;
    PORT
      LAYER M3 ;
        RECT  19.296 25.882 19.314 25.92 ;
    END
  END i[313]
  PIN i[314]
    DIRECTION INPUT ;
    USE SIGNAL ;
    PORT
      LAYER M5 ;
        RECT  19.344 25.728 19.368 25.92 ;
    END
  END i[314]
  PIN i[315]
    DIRECTION INPUT ;
    USE SIGNAL ;
    PORT
      LAYER M3 ;
        RECT  19.44 25.882 19.458 25.92 ;
    END
  END i[315]
  PIN i[316]
    DIRECTION INPUT ;
    USE SIGNAL ;
    PORT
      LAYER M5 ;
        RECT  19.536 25.728 19.56 25.92 ;
    END
  END i[316]
  PIN i[317]
    DIRECTION INPUT ;
    USE SIGNAL ;
    PORT
      LAYER M3 ;
        RECT  19.584 25.882 19.602 25.92 ;
    END
  END i[317]
  PIN i[318]
    DIRECTION INPUT ;
    USE SIGNAL ;
    PORT
      LAYER M5 ;
        RECT  19.632 25.728 19.656 25.92 ;
    END
  END i[318]
  PIN i[319]
    DIRECTION INPUT ;
    USE SIGNAL ;
    PORT
      LAYER M3 ;
        RECT  19.728 25.882 19.746 25.92 ;
    END
  END i[319]
  PIN i[31]
    DIRECTION INPUT ;
    USE SIGNAL ;
    PORT
      LAYER M3 ;
        RECT  34.056 25.882 34.074 25.92 ;
    END
  END i[31]
  PIN i[320]
    DIRECTION INPUT ;
    USE SIGNAL ;
    PORT
      LAYER M5 ;
        RECT  19.824 25.728 19.848 25.92 ;
    END
  END i[320]
  PIN i[321]
    DIRECTION INPUT ;
    USE SIGNAL ;
    PORT
      LAYER M3 ;
        RECT  19.944 25.882 19.962 25.92 ;
    END
  END i[321]
  PIN i[322]
    DIRECTION INPUT ;
    USE SIGNAL ;
    PORT
      LAYER M5 ;
        RECT  20.016 25.728 20.04 25.92 ;
    END
  END i[322]
  PIN i[323]
    DIRECTION INPUT ;
    USE SIGNAL ;
    PORT
      LAYER M3 ;
        RECT  20.088 25.882 20.106 25.92 ;
    END
  END i[323]
  PIN i[324]
    DIRECTION INPUT ;
    USE SIGNAL ;
    PORT
      LAYER M5 ;
        RECT  20.112 25.728 20.136 25.92 ;
    END
  END i[324]
  PIN i[325]
    DIRECTION INPUT ;
    USE SIGNAL ;
    PORT
      LAYER M3 ;
        RECT  20.232 25.882 20.25 25.92 ;
    END
  END i[325]
  PIN i[326]
    DIRECTION INPUT ;
    USE SIGNAL ;
    PORT
      LAYER M5 ;
        RECT  20.304 25.728 20.328 25.92 ;
    END
  END i[326]
  PIN i[327]
    DIRECTION INPUT ;
    USE SIGNAL ;
    PORT
      LAYER M3 ;
        RECT  20.376 25.882 20.394 25.92 ;
    END
  END i[327]
  PIN i[328]
    DIRECTION INPUT ;
    USE SIGNAL ;
    PORT
      LAYER M5 ;
        RECT  20.496 25.728 20.52 25.92 ;
    END
  END i[328]
  PIN i[329]
    DIRECTION INPUT ;
    USE SIGNAL ;
    PORT
      LAYER M3 ;
        RECT  20.592 25.882 20.61 25.92 ;
    END
  END i[329]
  PIN i[32]
    DIRECTION INPUT ;
    USE SIGNAL ;
    PORT
      LAYER M5 ;
        RECT  34.176 25.728 34.2 25.92 ;
    END
  END i[32]
  PIN i[330]
    DIRECTION INPUT ;
    USE SIGNAL ;
    PORT
      LAYER M5 ;
        RECT  20.592 25.728 20.616 25.92 ;
    END
  END i[330]
  PIN i[331]
    DIRECTION INPUT ;
    USE SIGNAL ;
    PORT
      LAYER M3 ;
        RECT  20.736 25.882 20.754 25.92 ;
    END
  END i[331]
  PIN i[332]
    DIRECTION INPUT ;
    USE SIGNAL ;
    PORT
      LAYER M5 ;
        RECT  20.784 25.728 20.808 25.92 ;
    END
  END i[332]
  PIN i[333]
    DIRECTION INPUT ;
    USE SIGNAL ;
    PORT
      LAYER M3 ;
        RECT  20.88 25.882 20.898 25.92 ;
    END
  END i[333]
  PIN i[334]
    DIRECTION INPUT ;
    USE SIGNAL ;
    PORT
      LAYER M5 ;
        RECT  20.976 25.728 21 25.92 ;
    END
  END i[334]
  PIN i[335]
    DIRECTION INPUT ;
    USE SIGNAL ;
    PORT
      LAYER M3 ;
        RECT  21.024 25.882 21.042 25.92 ;
    END
  END i[335]
  PIN i[336]
    DIRECTION INPUT ;
    USE SIGNAL ;
    PORT
      LAYER M5 ;
        RECT  21.072 25.728 21.096 25.92 ;
    END
  END i[336]
  PIN i[337]
    DIRECTION INPUT ;
    USE SIGNAL ;
    PORT
      LAYER M3 ;
        RECT  21.168 25.882 21.186 25.92 ;
    END
  END i[337]
  PIN i[338]
    DIRECTION INPUT ;
    USE SIGNAL ;
    PORT
      LAYER M5 ;
        RECT  21.264 25.728 21.288 25.92 ;
    END
  END i[338]
  PIN i[339]
    DIRECTION INPUT ;
    USE SIGNAL ;
    PORT
      LAYER M3 ;
        RECT  21.384 25.882 21.402 25.92 ;
    END
  END i[339]
  PIN i[33]
    DIRECTION INPUT ;
    USE SIGNAL ;
    PORT
      LAYER M3 ;
        RECT  34.2 25.882 34.218 25.92 ;
    END
  END i[33]
  PIN i[340]
    DIRECTION INPUT ;
    USE SIGNAL ;
    PORT
      LAYER M5 ;
        RECT  21.456 25.728 21.48 25.92 ;
    END
  END i[340]
  PIN i[341]
    DIRECTION INPUT ;
    USE SIGNAL ;
    PORT
      LAYER M3 ;
        RECT  21.528 25.882 21.546 25.92 ;
    END
  END i[341]
  PIN i[342]
    DIRECTION INPUT ;
    USE SIGNAL ;
    PORT
      LAYER M5 ;
        RECT  21.552 25.728 21.576 25.92 ;
    END
  END i[342]
  PIN i[343]
    DIRECTION INPUT ;
    USE SIGNAL ;
    PORT
      LAYER M3 ;
        RECT  21.672 25.882 21.69 25.92 ;
    END
  END i[343]
  PIN i[344]
    DIRECTION INPUT ;
    USE SIGNAL ;
    PORT
      LAYER M5 ;
        RECT  21.744 25.728 21.768 25.92 ;
    END
  END i[344]
  PIN i[345]
    DIRECTION INPUT ;
    USE SIGNAL ;
    PORT
      LAYER M3 ;
        RECT  21.744 25.882 21.762 25.92 ;
    END
  END i[345]
  PIN i[346]
    DIRECTION INPUT ;
    USE SIGNAL ;
    PORT
      LAYER M5 ;
        RECT  22.416 25.728 22.44 25.92 ;
    END
  END i[346]
  PIN i[347]
    DIRECTION INPUT ;
    USE SIGNAL ;
    PORT
      LAYER M3 ;
        RECT  22.392 25.882 22.41 25.92 ;
    END
  END i[347]
  PIN i[348]
    DIRECTION INPUT ;
    USE SIGNAL ;
    PORT
      LAYER M5 ;
        RECT  22.512 25.728 22.536 25.92 ;
    END
  END i[348]
  PIN i[349]
    DIRECTION INPUT ;
    USE SIGNAL ;
    PORT
      LAYER M3 ;
        RECT  22.464 25.882 22.482 25.92 ;
    END
  END i[349]
  PIN i[34]
    DIRECTION INPUT ;
    USE SIGNAL ;
    PORT
      LAYER M5 ;
        RECT  34.272 25.728 34.296 25.92 ;
    END
  END i[34]
  PIN i[350]
    DIRECTION INPUT ;
    USE SIGNAL ;
    PORT
      LAYER M5 ;
        RECT  22.608 25.728 22.632 25.92 ;
    END
  END i[350]
  PIN i[351]
    DIRECTION INPUT ;
    USE SIGNAL ;
    PORT
      LAYER M3 ;
        RECT  22.536 25.882 22.554 25.92 ;
    END
  END i[351]
  PIN i[352]
    DIRECTION INPUT ;
    USE SIGNAL ;
    PORT
      LAYER M5 ;
        RECT  22.704 25.728 22.728 25.92 ;
    END
  END i[352]
  PIN i[353]
    DIRECTION INPUT ;
    USE SIGNAL ;
    PORT
      LAYER M3 ;
        RECT  22.608 25.882 22.626 25.92 ;
    END
  END i[353]
  PIN i[354]
    DIRECTION INPUT ;
    USE SIGNAL ;
    PORT
      LAYER M3 ;
        RECT  39.816 25.882 39.834 25.92 ;
    END
  END i[354]
  PIN i[355]
    DIRECTION INPUT ;
    USE SIGNAL ;
    PORT
      LAYER M5 ;
        RECT  39.888 25.728 39.912 25.92 ;
    END
  END i[355]
  PIN i[356]
    DIRECTION INPUT ;
    USE SIGNAL ;
    PORT
      LAYER M3 ;
        RECT  39.96 25.882 39.978 25.92 ;
    END
  END i[356]
  PIN i[357]
    DIRECTION INPUT ;
    USE SIGNAL ;
    PORT
      LAYER M5 ;
        RECT  40.08 25.728 40.104 25.92 ;
    END
  END i[357]
  PIN i[358]
    DIRECTION INPUT ;
    USE SIGNAL ;
    PORT
      LAYER M3 ;
        RECT  40.104 25.882 40.122 25.92 ;
    END
  END i[358]
  PIN i[359]
    DIRECTION INPUT ;
    USE SIGNAL ;
    PORT
      LAYER M5 ;
        RECT  40.176 25.728 40.2 25.92 ;
    END
  END i[359]
  PIN i[35]
    DIRECTION INPUT ;
    USE SIGNAL ;
    PORT
      LAYER M3 ;
        RECT  34.416 25.882 34.434 25.92 ;
    END
  END i[35]
  PIN i[360]
    DIRECTION INPUT ;
    USE SIGNAL ;
    PORT
      LAYER M3 ;
        RECT  40.248 25.882 40.266 25.92 ;
    END
  END i[360]
  PIN i[361]
    DIRECTION INPUT ;
    USE SIGNAL ;
    PORT
      LAYER M5 ;
        RECT  40.368 25.728 40.392 25.92 ;
    END
  END i[361]
  PIN i[362]
    DIRECTION INPUT ;
    USE SIGNAL ;
    PORT
      LAYER M3 ;
        RECT  40.464 25.882 40.482 25.92 ;
    END
  END i[362]
  PIN i[363]
    DIRECTION INPUT ;
    USE SIGNAL ;
    PORT
      LAYER M5 ;
        RECT  40.464 25.728 40.488 25.92 ;
    END
  END i[363]
  PIN i[364]
    DIRECTION INPUT ;
    USE SIGNAL ;
    PORT
      LAYER M3 ;
        RECT  40.608 25.882 40.626 25.92 ;
    END
  END i[364]
  PIN i[365]
    DIRECTION INPUT ;
    USE SIGNAL ;
    PORT
      LAYER M5 ;
        RECT  40.656 25.728 40.68 25.92 ;
    END
  END i[365]
  PIN i[366]
    DIRECTION INPUT ;
    USE SIGNAL ;
    PORT
      LAYER M3 ;
        RECT  40.752 25.882 40.77 25.92 ;
    END
  END i[366]
  PIN i[367]
    DIRECTION INPUT ;
    USE SIGNAL ;
    PORT
      LAYER M5 ;
        RECT  40.848 25.728 40.872 25.92 ;
    END
  END i[367]
  PIN i[368]
    DIRECTION INPUT ;
    USE SIGNAL ;
    PORT
      LAYER M5 ;
        RECT  40.944 25.728 40.968 25.92 ;
    END
  END i[368]
  PIN i[369]
    DIRECTION INPUT ;
    USE SIGNAL ;
    PORT
      LAYER M5 ;
        RECT  22.8 25.728 22.824 25.92 ;
    END
  END i[369]
  PIN i[36]
    DIRECTION INPUT ;
    USE SIGNAL ;
    PORT
      LAYER M5 ;
        RECT  34.464 25.728 34.488 25.92 ;
    END
  END i[36]
  PIN i[370]
    DIRECTION INPUT ;
    USE SIGNAL ;
    PORT
      LAYER M3 ;
        RECT  22.68 25.882 22.698 25.92 ;
    END
  END i[370]
  PIN i[371]
    DIRECTION INPUT ;
    USE SIGNAL ;
    PORT
      LAYER M5 ;
        RECT  22.896 25.728 22.92 25.92 ;
    END
  END i[371]
  PIN i[372]
    DIRECTION INPUT ;
    USE SIGNAL ;
    PORT
      LAYER M3 ;
        RECT  22.752 25.882 22.77 25.92 ;
    END
  END i[372]
  PIN i[373]
    DIRECTION INPUT ;
    USE SIGNAL ;
    PORT
      LAYER M5 ;
        RECT  22.992 25.728 23.016 25.92 ;
    END
  END i[373]
  PIN i[374]
    DIRECTION INPUT ;
    USE SIGNAL ;
    PORT
      LAYER M3 ;
        RECT  22.968 25.882 22.986 25.92 ;
    END
  END i[374]
  PIN i[375]
    DIRECTION INPUT ;
    USE SIGNAL ;
    PORT
      LAYER M5 ;
        RECT  23.088 25.728 23.112 25.92 ;
    END
  END i[375]
  PIN i[376]
    DIRECTION INPUT ;
    USE SIGNAL ;
    PORT
      LAYER M3 ;
        RECT  23.112 25.882 23.13 25.92 ;
    END
  END i[376]
  PIN i[377]
    DIRECTION INPUT ;
    USE SIGNAL ;
    PORT
      LAYER M5 ;
        RECT  23.184 25.728 23.208 25.92 ;
    END
  END i[377]
  PIN i[378]
    DIRECTION INPUT ;
    USE SIGNAL ;
    PORT
      LAYER M3 ;
        RECT  23.256 25.882 23.274 25.92 ;
    END
  END i[378]
  PIN i[379]
    DIRECTION INPUT ;
    USE SIGNAL ;
    PORT
      LAYER M5 ;
        RECT  23.376 25.728 23.4 25.92 ;
    END
  END i[379]
  PIN i[37]
    DIRECTION INPUT ;
    USE SIGNAL ;
    PORT
      LAYER M3 ;
        RECT  34.56 25.882 34.578 25.92 ;
    END
  END i[37]
  PIN i[380]
    DIRECTION INPUT ;
    USE SIGNAL ;
    PORT
      LAYER M3 ;
        RECT  23.4 25.882 23.418 25.92 ;
    END
  END i[380]
  PIN i[381]
    DIRECTION INPUT ;
    USE SIGNAL ;
    PORT
      LAYER M5 ;
        RECT  23.472 25.728 23.496 25.92 ;
    END
  END i[381]
  PIN i[382]
    DIRECTION INPUT ;
    USE SIGNAL ;
    PORT
      LAYER M3 ;
        RECT  23.544 25.882 23.562 25.92 ;
    END
  END i[382]
  PIN i[383]
    DIRECTION INPUT ;
    USE SIGNAL ;
    PORT
      LAYER M5 ;
        RECT  23.664 25.728 23.688 25.92 ;
    END
  END i[383]
  PIN i[384]
    DIRECTION INPUT ;
    USE SIGNAL ;
    PORT
      LAYER M3 ;
        RECT  23.76 25.882 23.778 25.92 ;
    END
  END i[384]
  PIN i[385]
    DIRECTION INPUT ;
    USE SIGNAL ;
    PORT
      LAYER M5 ;
        RECT  23.856 25.728 23.88 25.92 ;
    END
  END i[385]
  PIN i[386]
    DIRECTION INPUT ;
    USE SIGNAL ;
    PORT
      LAYER M3 ;
        RECT  23.904 25.882 23.922 25.92 ;
    END
  END i[386]
  PIN i[387]
    DIRECTION INPUT ;
    USE SIGNAL ;
    PORT
      LAYER M5 ;
        RECT  23.952 25.728 23.976 25.92 ;
    END
  END i[387]
  PIN i[388]
    DIRECTION INPUT ;
    USE SIGNAL ;
    PORT
      LAYER M3 ;
        RECT  24.048 25.882 24.066 25.92 ;
    END
  END i[388]
  PIN i[389]
    DIRECTION INPUT ;
    USE SIGNAL ;
    PORT
      LAYER M5 ;
        RECT  24.144 25.728 24.168 25.92 ;
    END
  END i[389]
  PIN i[38]
    DIRECTION INPUT ;
    USE SIGNAL ;
    PORT
      LAYER M5 ;
        RECT  34.656 25.728 34.68 25.92 ;
    END
  END i[38]
  PIN i[390]
    DIRECTION INPUT ;
    USE SIGNAL ;
    PORT
      LAYER M3 ;
        RECT  24.192 25.882 24.21 25.92 ;
    END
  END i[390]
  PIN i[391]
    DIRECTION INPUT ;
    USE SIGNAL ;
    PORT
      LAYER M5 ;
        RECT  24.336 25.728 24.36 25.92 ;
    END
  END i[391]
  PIN i[392]
    DIRECTION INPUT ;
    USE SIGNAL ;
    PORT
      LAYER M3 ;
        RECT  24.408 25.882 24.426 25.92 ;
    END
  END i[392]
  PIN i[393]
    DIRECTION INPUT ;
    USE SIGNAL ;
    PORT
      LAYER M5 ;
        RECT  24.432 25.728 24.456 25.92 ;
    END
  END i[393]
  PIN i[394]
    DIRECTION INPUT ;
    USE SIGNAL ;
    PORT
      LAYER M3 ;
        RECT  24.552 25.882 24.57 25.92 ;
    END
  END i[394]
  PIN i[395]
    DIRECTION INPUT ;
    USE SIGNAL ;
    PORT
      LAYER M5 ;
        RECT  24.624 25.728 24.648 25.92 ;
    END
  END i[395]
  PIN i[396]
    DIRECTION INPUT ;
    USE SIGNAL ;
    PORT
      LAYER M3 ;
        RECT  24.696 25.882 24.714 25.92 ;
    END
  END i[396]
  PIN i[397]
    DIRECTION INPUT ;
    USE SIGNAL ;
    PORT
      LAYER M5 ;
        RECT  24.816 25.728 24.84 25.92 ;
    END
  END i[397]
  PIN i[398]
    DIRECTION INPUT ;
    USE SIGNAL ;
    PORT
      LAYER M3 ;
        RECT  24.84 25.882 24.858 25.92 ;
    END
  END i[398]
  PIN i[399]
    DIRECTION INPUT ;
    USE SIGNAL ;
    PORT
      LAYER M5 ;
        RECT  24.912 25.728 24.936 25.92 ;
    END
  END i[399]
  PIN i[39]
    DIRECTION INPUT ;
    USE SIGNAL ;
    PORT
      LAYER M3 ;
        RECT  34.704 25.882 34.722 25.92 ;
    END
  END i[39]
  PIN i[3]
    DIRECTION INPUT ;
    USE SIGNAL ;
    PORT
      LAYER M3 ;
        RECT  31.68 25.882 31.698 25.92 ;
    END
  END i[3]
  PIN i[400]
    DIRECTION INPUT ;
    USE SIGNAL ;
    PORT
      LAYER M3 ;
        RECT  24.984 25.882 25.002 25.92 ;
    END
  END i[400]
  PIN i[401]
    DIRECTION INPUT ;
    USE SIGNAL ;
    PORT
      LAYER M5 ;
        RECT  25.104 25.728 25.128 25.92 ;
    END
  END i[401]
  PIN i[402]
    DIRECTION INPUT ;
    USE SIGNAL ;
    PORT
      LAYER M3 ;
        RECT  25.2 25.882 25.218 25.92 ;
    END
  END i[402]
  PIN i[403]
    DIRECTION INPUT ;
    USE SIGNAL ;
    PORT
      LAYER M5 ;
        RECT  25.2 25.728 25.224 25.92 ;
    END
  END i[403]
  PIN i[404]
    DIRECTION INPUT ;
    USE SIGNAL ;
    PORT
      LAYER M3 ;
        RECT  25.344 25.882 25.362 25.92 ;
    END
  END i[404]
  PIN i[405]
    DIRECTION INPUT ;
    USE SIGNAL ;
    PORT
      LAYER M5 ;
        RECT  25.392 25.728 25.416 25.92 ;
    END
  END i[405]
  PIN i[406]
    DIRECTION INPUT ;
    USE SIGNAL ;
    PORT
      LAYER M3 ;
        RECT  25.488 25.882 25.506 25.92 ;
    END
  END i[406]
  PIN i[407]
    DIRECTION INPUT ;
    USE SIGNAL ;
    PORT
      LAYER M5 ;
        RECT  25.584 25.728 25.608 25.92 ;
    END
  END i[407]
  PIN i[408]
    DIRECTION INPUT ;
    USE SIGNAL ;
    PORT
      LAYER M3 ;
        RECT  25.632 25.882 25.65 25.92 ;
    END
  END i[408]
  PIN i[409]
    DIRECTION INPUT ;
    USE SIGNAL ;
    PORT
      LAYER M5 ;
        RECT  25.68 25.728 25.704 25.92 ;
    END
  END i[409]
  PIN i[40]
    DIRECTION INPUT ;
    USE SIGNAL ;
    PORT
      LAYER M5 ;
        RECT  34.752 25.728 34.776 25.92 ;
    END
  END i[40]
  PIN i[410]
    DIRECTION INPUT ;
    USE SIGNAL ;
    PORT
      LAYER M3 ;
        RECT  25.776 25.882 25.794 25.92 ;
    END
  END i[410]
  PIN i[411]
    DIRECTION INPUT ;
    USE SIGNAL ;
    PORT
      LAYER M5 ;
        RECT  25.872 25.728 25.896 25.92 ;
    END
  END i[411]
  PIN i[412]
    DIRECTION INPUT ;
    USE SIGNAL ;
    PORT
      LAYER M3 ;
        RECT  25.992 25.882 26.01 25.92 ;
    END
  END i[412]
  PIN i[413]
    DIRECTION INPUT ;
    USE SIGNAL ;
    PORT
      LAYER M5 ;
        RECT  26.064 25.728 26.088 25.92 ;
    END
  END i[413]
  PIN i[414]
    DIRECTION INPUT ;
    USE SIGNAL ;
    PORT
      LAYER M3 ;
        RECT  26.136 25.882 26.154 25.92 ;
    END
  END i[414]
  PIN i[415]
    DIRECTION INPUT ;
    USE SIGNAL ;
    PORT
      LAYER M5 ;
        RECT  26.16 25.728 26.184 25.92 ;
    END
  END i[415]
  PIN i[416]
    DIRECTION INPUT ;
    USE SIGNAL ;
    PORT
      LAYER M3 ;
        RECT  26.28 25.882 26.298 25.92 ;
    END
  END i[416]
  PIN i[417]
    DIRECTION INPUT ;
    USE SIGNAL ;
    PORT
      LAYER M5 ;
        RECT  26.352 25.728 26.376 25.92 ;
    END
  END i[417]
  PIN i[418]
    DIRECTION INPUT ;
    USE SIGNAL ;
    PORT
      LAYER M3 ;
        RECT  26.424 25.882 26.442 25.92 ;
    END
  END i[418]
  PIN i[419]
    DIRECTION INPUT ;
    USE SIGNAL ;
    PORT
      LAYER M5 ;
        RECT  26.544 25.728 26.568 25.92 ;
    END
  END i[419]
  PIN i[41]
    DIRECTION INPUT ;
    USE SIGNAL ;
    PORT
      LAYER M3 ;
        RECT  34.848 25.882 34.866 25.92 ;
    END
  END i[41]
  PIN i[420]
    DIRECTION INPUT ;
    USE SIGNAL ;
    PORT
      LAYER M3 ;
        RECT  26.568 25.882 26.586 25.92 ;
    END
  END i[420]
  PIN i[421]
    DIRECTION INPUT ;
    USE SIGNAL ;
    PORT
      LAYER M5 ;
        RECT  26.64 25.728 26.664 25.92 ;
    END
  END i[421]
  PIN i[422]
    DIRECTION INPUT ;
    USE SIGNAL ;
    PORT
      LAYER M3 ;
        RECT  26.784 25.882 26.802 25.92 ;
    END
  END i[422]
  PIN i[423]
    DIRECTION INPUT ;
    USE SIGNAL ;
    PORT
      LAYER M5 ;
        RECT  26.832 25.728 26.856 25.92 ;
    END
  END i[423]
  PIN i[424]
    DIRECTION INPUT ;
    USE SIGNAL ;
    PORT
      LAYER M3 ;
        RECT  26.928 25.882 26.946 25.92 ;
    END
  END i[424]
  PIN i[425]
    DIRECTION INPUT ;
    USE SIGNAL ;
    PORT
      LAYER M5 ;
        RECT  27.024 25.728 27.048 25.92 ;
    END
  END i[425]
  PIN i[426]
    DIRECTION INPUT ;
    USE SIGNAL ;
    PORT
      LAYER M3 ;
        RECT  27.072 25.882 27.09 25.92 ;
    END
  END i[426]
  PIN i[427]
    DIRECTION INPUT ;
    USE SIGNAL ;
    PORT
      LAYER M5 ;
        RECT  27.12 25.728 27.144 25.92 ;
    END
  END i[427]
  PIN i[428]
    DIRECTION INPUT ;
    USE SIGNAL ;
    PORT
      LAYER M3 ;
        RECT  27.144 25.882 27.162 25.92 ;
    END
  END i[428]
  PIN i[429]
    DIRECTION INPUT ;
    USE SIGNAL ;
    PORT
      LAYER M5 ;
        RECT  27.744 25.728 27.768 25.92 ;
    END
  END i[429]
  PIN i[42]
    DIRECTION INPUT ;
    USE SIGNAL ;
    PORT
      LAYER M3 ;
        RECT  35.064 25.882 35.082 25.92 ;
    END
  END i[42]
  PIN i[430]
    DIRECTION INPUT ;
    USE SIGNAL ;
    PORT
      LAYER M3 ;
        RECT  27.792 25.882 27.81 25.92 ;
    END
  END i[430]
  PIN i[431]
    DIRECTION INPUT ;
    USE SIGNAL ;
    PORT
      LAYER M5 ;
        RECT  27.84 25.728 27.864 25.92 ;
    END
  END i[431]
  PIN i[432]
    DIRECTION INPUT ;
    USE SIGNAL ;
    PORT
      LAYER M3 ;
        RECT  27.864 25.882 27.882 25.92 ;
    END
  END i[432]
  PIN i[433]
    DIRECTION INPUT ;
    USE SIGNAL ;
    PORT
      LAYER M5 ;
        RECT  27.936 25.728 27.96 25.92 ;
    END
  END i[433]
  PIN i[434]
    DIRECTION INPUT ;
    USE SIGNAL ;
    PORT
      LAYER M3 ;
        RECT  27.936 25.882 27.954 25.92 ;
    END
  END i[434]
  PIN i[435]
    DIRECTION INPUT ;
    USE SIGNAL ;
    PORT
      LAYER M5 ;
        RECT  28.032 25.728 28.056 25.92 ;
    END
  END i[435]
  PIN i[436]
    DIRECTION INPUT ;
    USE SIGNAL ;
    PORT
      LAYER M3 ;
        RECT  28.008 25.882 28.026 25.92 ;
    END
  END i[436]
  PIN i[437]
    DIRECTION INPUT ;
    USE SIGNAL ;
    PORT
      LAYER M5 ;
        RECT  28.128 25.728 28.152 25.92 ;
    END
  END i[437]
  PIN i[438]
    DIRECTION INPUT ;
    USE SIGNAL ;
    PORT
      LAYER M3 ;
        RECT  28.08 25.882 28.098 25.92 ;
    END
  END i[438]
  PIN i[439]
    DIRECTION INPUT ;
    USE SIGNAL ;
    PORT
      LAYER M5 ;
        RECT  28.224 25.728 28.248 25.92 ;
    END
  END i[439]
  PIN i[43]
    DIRECTION INPUT ;
    USE SIGNAL ;
    PORT
      LAYER M5 ;
        RECT  35.136 25.728 35.16 25.92 ;
    END
  END i[43]
  PIN i[440]
    DIRECTION INPUT ;
    USE SIGNAL ;
    PORT
      LAYER M3 ;
        RECT  28.224 25.882 28.242 25.92 ;
    END
  END i[440]
  PIN i[441]
    DIRECTION INPUT ;
    USE SIGNAL ;
    PORT
      LAYER M5 ;
        RECT  28.32 25.728 28.344 25.92 ;
    END
  END i[441]
  PIN i[442]
    DIRECTION INPUT ;
    USE SIGNAL ;
    PORT
      LAYER M3 ;
        RECT  28.368 25.882 28.386 25.92 ;
    END
  END i[442]
  PIN i[443]
    DIRECTION INPUT ;
    USE SIGNAL ;
    PORT
      LAYER M5 ;
        RECT  28.416 25.728 28.44 25.92 ;
    END
  END i[443]
  PIN i[444]
    DIRECTION INPUT ;
    USE SIGNAL ;
    PORT
      LAYER M3 ;
        RECT  28.512 25.882 28.53 25.92 ;
    END
  END i[444]
  PIN i[445]
    DIRECTION INPUT ;
    USE SIGNAL ;
    PORT
      LAYER M5 ;
        RECT  28.608 25.728 28.632 25.92 ;
    END
  END i[445]
  PIN i[446]
    DIRECTION INPUT ;
    USE SIGNAL ;
    PORT
      LAYER M3 ;
        RECT  28.656 25.882 28.674 25.92 ;
    END
  END i[446]
  PIN i[447]
    DIRECTION INPUT ;
    USE SIGNAL ;
    PORT
      LAYER M5 ;
        RECT  28.704 25.728 28.728 25.92 ;
    END
  END i[447]
  PIN i[448]
    DIRECTION INPUT ;
    USE SIGNAL ;
    PORT
      LAYER M3 ;
        RECT  28.8 25.882 28.818 25.92 ;
    END
  END i[448]
  PIN i[449]
    DIRECTION INPUT ;
    USE SIGNAL ;
    PORT
      LAYER M5 ;
        RECT  28.896 25.728 28.92 25.92 ;
    END
  END i[449]
  PIN i[44]
    DIRECTION INPUT ;
    USE SIGNAL ;
    PORT
      LAYER M3 ;
        RECT  35.208 25.882 35.226 25.92 ;
    END
  END i[44]
  PIN i[450]
    DIRECTION INPUT ;
    USE SIGNAL ;
    PORT
      LAYER M3 ;
        RECT  29.016 25.882 29.034 25.92 ;
    END
  END i[450]
  PIN i[451]
    DIRECTION INPUT ;
    USE SIGNAL ;
    PORT
      LAYER M5 ;
        RECT  29.088 25.728 29.112 25.92 ;
    END
  END i[451]
  PIN i[452]
    DIRECTION INPUT ;
    USE SIGNAL ;
    PORT
      LAYER M3 ;
        RECT  29.16 25.882 29.178 25.92 ;
    END
  END i[452]
  PIN i[453]
    DIRECTION INPUT ;
    USE SIGNAL ;
    PORT
      LAYER M5 ;
        RECT  29.184 25.728 29.208 25.92 ;
    END
  END i[453]
  PIN i[454]
    DIRECTION INPUT ;
    USE SIGNAL ;
    PORT
      LAYER M3 ;
        RECT  29.304 25.882 29.322 25.92 ;
    END
  END i[454]
  PIN i[455]
    DIRECTION INPUT ;
    USE SIGNAL ;
    PORT
      LAYER M5 ;
        RECT  29.376 25.728 29.4 25.92 ;
    END
  END i[455]
  PIN i[456]
    DIRECTION INPUT ;
    USE SIGNAL ;
    PORT
      LAYER M3 ;
        RECT  29.448 25.882 29.466 25.92 ;
    END
  END i[456]
  PIN i[457]
    DIRECTION INPUT ;
    USE SIGNAL ;
    PORT
      LAYER M5 ;
        RECT  29.568 25.728 29.592 25.92 ;
    END
  END i[457]
  PIN i[458]
    DIRECTION INPUT ;
    USE SIGNAL ;
    PORT
      LAYER M3 ;
        RECT  29.592 25.882 29.61 25.92 ;
    END
  END i[458]
  PIN i[459]
    DIRECTION INPUT ;
    USE SIGNAL ;
    PORT
      LAYER M5 ;
        RECT  29.664 25.728 29.688 25.92 ;
    END
  END i[459]
  PIN i[45]
    DIRECTION INPUT ;
    USE SIGNAL ;
    PORT
      LAYER M5 ;
        RECT  35.232 25.728 35.256 25.92 ;
    END
  END i[45]
  PIN i[460]
    DIRECTION INPUT ;
    USE SIGNAL ;
    PORT
      LAYER M3 ;
        RECT  29.808 25.882 29.826 25.92 ;
    END
  END i[460]
  PIN i[461]
    DIRECTION INPUT ;
    USE SIGNAL ;
    PORT
      LAYER M5 ;
        RECT  29.856 25.728 29.88 25.92 ;
    END
  END i[461]
  PIN i[462]
    DIRECTION INPUT ;
    USE SIGNAL ;
    PORT
      LAYER M3 ;
        RECT  29.952 25.882 29.97 25.92 ;
    END
  END i[462]
  PIN i[463]
    DIRECTION INPUT ;
    USE SIGNAL ;
    PORT
      LAYER M5 ;
        RECT  30.048 25.728 30.072 25.92 ;
    END
  END i[463]
  PIN i[464]
    DIRECTION INPUT ;
    USE SIGNAL ;
    PORT
      LAYER M3 ;
        RECT  30.096 25.882 30.114 25.92 ;
    END
  END i[464]
  PIN i[465]
    DIRECTION INPUT ;
    USE SIGNAL ;
    PORT
      LAYER M5 ;
        RECT  30.144 25.728 30.168 25.92 ;
    END
  END i[465]
  PIN i[466]
    DIRECTION INPUT ;
    USE SIGNAL ;
    PORT
      LAYER M3 ;
        RECT  30.24 25.882 30.258 25.92 ;
    END
  END i[466]
  PIN i[467]
    DIRECTION INPUT ;
    USE SIGNAL ;
    PORT
      LAYER M5 ;
        RECT  30.336 25.728 30.36 25.92 ;
    END
  END i[467]
  PIN i[468]
    DIRECTION INPUT ;
    USE SIGNAL ;
    PORT
      LAYER M3 ;
        RECT  30.384 25.882 30.402 25.92 ;
    END
  END i[468]
  PIN i[469]
    DIRECTION INPUT ;
    USE SIGNAL ;
    PORT
      LAYER M5 ;
        RECT  30.528 25.728 30.552 25.92 ;
    END
  END i[469]
  PIN i[46]
    DIRECTION INPUT ;
    USE SIGNAL ;
    PORT
      LAYER M3 ;
        RECT  35.352 25.882 35.37 25.92 ;
    END
  END i[46]
  PIN i[470]
    DIRECTION INPUT ;
    USE SIGNAL ;
    PORT
      LAYER M3 ;
        RECT  30.6 25.882 30.618 25.92 ;
    END
  END i[470]
  PIN i[471]
    DIRECTION INPUT ;
    USE SIGNAL ;
    PORT
      LAYER M5 ;
        RECT  30.624 25.728 30.648 25.92 ;
    END
  END i[471]
  PIN i[472]
    DIRECTION INPUT ;
    USE SIGNAL ;
    PORT
      LAYER M3 ;
        RECT  30.744 25.882 30.762 25.92 ;
    END
  END i[472]
  PIN i[473]
    DIRECTION INPUT ;
    USE SIGNAL ;
    PORT
      LAYER M5 ;
        RECT  30.816 25.728 30.84 25.92 ;
    END
  END i[473]
  PIN i[474]
    DIRECTION INPUT ;
    USE SIGNAL ;
    PORT
      LAYER M3 ;
        RECT  30.888 25.882 30.906 25.92 ;
    END
  END i[474]
  PIN i[475]
    DIRECTION INPUT ;
    USE SIGNAL ;
    PORT
      LAYER M5 ;
        RECT  31.008 25.728 31.032 25.92 ;
    END
  END i[475]
  PIN i[476]
    DIRECTION INPUT ;
    USE SIGNAL ;
    PORT
      LAYER M3 ;
        RECT  31.032 25.882 31.05 25.92 ;
    END
  END i[476]
  PIN i[477]
    DIRECTION INPUT ;
    USE SIGNAL ;
    PORT
      LAYER M5 ;
        RECT  31.104 25.728 31.128 25.92 ;
    END
  END i[477]
  PIN i[478]
    DIRECTION INPUT ;
    USE SIGNAL ;
    PORT
      LAYER M3 ;
        RECT  31.176 25.882 31.194 25.92 ;
    END
  END i[478]
  PIN i[479]
    DIRECTION INPUT ;
    USE SIGNAL ;
    PORT
      LAYER M5 ;
        RECT  31.296 25.728 31.32 25.92 ;
    END
  END i[479]
  PIN i[47]
    DIRECTION INPUT ;
    USE SIGNAL ;
    PORT
      LAYER M5 ;
        RECT  35.424 25.728 35.448 25.92 ;
    END
  END i[47]
  PIN i[480]
    DIRECTION INPUT ;
    USE SIGNAL ;
    PORT
      LAYER M3 ;
        RECT  31.392 25.882 31.41 25.92 ;
    END
  END i[480]
  PIN i[48]
    DIRECTION INPUT ;
    USE SIGNAL ;
    PORT
      LAYER M3 ;
        RECT  35.496 25.882 35.514 25.92 ;
    END
  END i[48]
  PIN i[49]
    DIRECTION INPUT ;
    USE SIGNAL ;
    PORT
      LAYER M5 ;
        RECT  35.616 25.728 35.64 25.92 ;
    END
  END i[49]
  PIN i[4]
    DIRECTION INPUT ;
    USE SIGNAL ;
    PORT
      LAYER M5 ;
        RECT  31.776 25.728 31.8 25.92 ;
    END
  END i[4]
  PIN i[50]
    DIRECTION INPUT ;
    USE SIGNAL ;
    PORT
      LAYER M3 ;
        RECT  35.64 25.882 35.658 25.92 ;
    END
  END i[50]
  PIN i[51]
    DIRECTION INPUT ;
    USE SIGNAL ;
    PORT
      LAYER M5 ;
        RECT  35.712 25.728 35.736 25.92 ;
    END
  END i[51]
  PIN i[52]
    DIRECTION INPUT ;
    USE SIGNAL ;
    PORT
      LAYER M3 ;
        RECT  35.856 25.882 35.874 25.92 ;
    END
  END i[52]
  PIN i[53]
    DIRECTION INPUT ;
    USE SIGNAL ;
    PORT
      LAYER M5 ;
        RECT  35.904 25.728 35.928 25.92 ;
    END
  END i[53]
  PIN i[54]
    DIRECTION INPUT ;
    USE SIGNAL ;
    PORT
      LAYER M3 ;
        RECT  36 25.882 36.018 25.92 ;
    END
  END i[54]
  PIN i[55]
    DIRECTION INPUT ;
    USE SIGNAL ;
    PORT
      LAYER M5 ;
        RECT  36.096 25.728 36.12 25.92 ;
    END
  END i[55]
  PIN i[56]
    DIRECTION INPUT ;
    USE SIGNAL ;
    PORT
      LAYER M5 ;
        RECT  36.192 25.728 36.216 25.92 ;
    END
  END i[56]
  PIN i[57]
    DIRECTION INPUT ;
    USE SIGNAL ;
    PORT
      LAYER M3 ;
        RECT  36.288 25.882 36.306 25.92 ;
    END
  END i[57]
  PIN i[58]
    DIRECTION INPUT ;
    USE SIGNAL ;
    PORT
      LAYER M5 ;
        RECT  36.384 25.728 36.408 25.92 ;
    END
  END i[58]
  PIN i[59]
    DIRECTION INPUT ;
    USE SIGNAL ;
    PORT
      LAYER M3 ;
        RECT  36.432 25.882 36.45 25.92 ;
    END
  END i[59]
  PIN i[5]
    DIRECTION INPUT ;
    USE SIGNAL ;
    PORT
      LAYER M3 ;
        RECT  31.824 25.882 31.842 25.92 ;
    END
  END i[5]
  PIN i[60]
    DIRECTION INPUT ;
    USE SIGNAL ;
    PORT
      LAYER M5 ;
        RECT  36.576 25.728 36.6 25.92 ;
    END
  END i[60]
  PIN i[61]
    DIRECTION INPUT ;
    USE SIGNAL ;
    PORT
      LAYER M3 ;
        RECT  36.648 25.882 36.666 25.92 ;
    END
  END i[61]
  PIN i[62]
    DIRECTION INPUT ;
    USE SIGNAL ;
    PORT
      LAYER M5 ;
        RECT  36.672 25.728 36.696 25.92 ;
    END
  END i[62]
  PIN i[63]
    DIRECTION INPUT ;
    USE SIGNAL ;
    PORT
      LAYER M3 ;
        RECT  36.792 25.882 36.81 25.92 ;
    END
  END i[63]
  PIN i[64]
    DIRECTION INPUT ;
    USE SIGNAL ;
    PORT
      LAYER M5 ;
        RECT  36.864 25.728 36.888 25.92 ;
    END
  END i[64]
  PIN i[65]
    DIRECTION INPUT ;
    USE SIGNAL ;
    PORT
      LAYER M3 ;
        RECT  36.936 25.882 36.954 25.92 ;
    END
  END i[65]
  PIN i[66]
    DIRECTION INPUT ;
    USE SIGNAL ;
    PORT
      LAYER M5 ;
        RECT  37.056 25.728 37.08 25.92 ;
    END
  END i[66]
  PIN i[67]
    DIRECTION INPUT ;
    USE SIGNAL ;
    PORT
      LAYER M3 ;
        RECT  37.08 25.882 37.098 25.92 ;
    END
  END i[67]
  PIN i[68]
    DIRECTION INPUT ;
    USE SIGNAL ;
    PORT
      LAYER M5 ;
        RECT  37.152 25.728 37.176 25.92 ;
    END
  END i[68]
  PIN i[69]
    DIRECTION INPUT ;
    USE SIGNAL ;
    PORT
      LAYER M3 ;
        RECT  37.224 25.882 37.242 25.92 ;
    END
  END i[69]
  PIN i[6]
    DIRECTION INPUT ;
    USE SIGNAL ;
    PORT
      LAYER M5 ;
        RECT  31.968 25.728 31.992 25.92 ;
    END
  END i[6]
  PIN i[70]
    DIRECTION INPUT ;
    USE SIGNAL ;
    PORT
      LAYER M3 ;
        RECT  37.44 25.882 37.458 25.92 ;
    END
  END i[70]
  PIN i[71]
    DIRECTION INPUT ;
    USE SIGNAL ;
    PORT
      LAYER M5 ;
        RECT  37.536 25.728 37.56 25.92 ;
    END
  END i[71]
  PIN i[72]
    DIRECTION INPUT ;
    USE SIGNAL ;
    PORT
      LAYER M3 ;
        RECT  37.584 25.882 37.602 25.92 ;
    END
  END i[72]
  PIN i[73]
    DIRECTION INPUT ;
    USE SIGNAL ;
    PORT
      LAYER M5 ;
        RECT  37.632 25.728 37.656 25.92 ;
    END
  END i[73]
  PIN i[74]
    DIRECTION INPUT ;
    USE SIGNAL ;
    PORT
      LAYER M3 ;
        RECT  37.728 25.882 37.746 25.92 ;
    END
  END i[74]
  PIN i[75]
    DIRECTION INPUT ;
    USE SIGNAL ;
    PORT
      LAYER M5 ;
        RECT  37.824 25.728 37.848 25.92 ;
    END
  END i[75]
  PIN i[76]
    DIRECTION INPUT ;
    USE SIGNAL ;
    PORT
      LAYER M3 ;
        RECT  37.872 25.882 37.89 25.92 ;
    END
  END i[76]
  PIN i[77]
    DIRECTION INPUT ;
    USE SIGNAL ;
    PORT
      LAYER M5 ;
        RECT  37.92 25.728 37.944 25.92 ;
    END
  END i[77]
  PIN i[78]
    DIRECTION INPUT ;
    USE SIGNAL ;
    PORT
      LAYER M3 ;
        RECT  37.944 25.882 37.962 25.92 ;
    END
  END i[78]
  PIN i[79]
    DIRECTION INPUT ;
    USE SIGNAL ;
    PORT
      LAYER M5 ;
        RECT  38.544 25.728 38.568 25.92 ;
    END
  END i[79]
  PIN i[7]
    DIRECTION INPUT ;
    USE SIGNAL ;
    PORT
      LAYER M3 ;
        RECT  32.04 25.882 32.058 25.92 ;
    END
  END i[7]
  PIN i[80]
    DIRECTION INPUT ;
    USE SIGNAL ;
    PORT
      LAYER M3 ;
        RECT  38.592 25.882 38.61 25.92 ;
    END
  END i[80]
  PIN i[81]
    DIRECTION INPUT ;
    USE SIGNAL ;
    PORT
      LAYER M5 ;
        RECT  38.64 25.728 38.664 25.92 ;
    END
  END i[81]
  PIN i[82]
    DIRECTION INPUT ;
    USE SIGNAL ;
    PORT
      LAYER M3 ;
        RECT  38.664 25.882 38.682 25.92 ;
    END
  END i[82]
  PIN i[83]
    DIRECTION INPUT ;
    USE SIGNAL ;
    PORT
      LAYER M5 ;
        RECT  38.736 25.728 38.76 25.92 ;
    END
  END i[83]
  PIN i[84]
    DIRECTION INPUT ;
    USE SIGNAL ;
    PORT
      LAYER M5 ;
        RECT  2.16 25.728 2.184 25.92 ;
    END
  END i[84]
  PIN i[85]
    DIRECTION INPUT ;
    USE SIGNAL ;
    PORT
      LAYER M3 ;
        RECT  2.304 25.882 2.322 25.92 ;
    END
  END i[85]
  PIN i[86]
    DIRECTION INPUT ;
    USE SIGNAL ;
    PORT
      LAYER M5 ;
        RECT  2.352 25.728 2.376 25.92 ;
    END
  END i[86]
  PIN i[87]
    DIRECTION INPUT ;
    USE SIGNAL ;
    PORT
      LAYER M3 ;
        RECT  2.448 25.882 2.466 25.92 ;
    END
  END i[87]
  PIN i[88]
    DIRECTION INPUT ;
    USE SIGNAL ;
    PORT
      LAYER M5 ;
        RECT  2.544 25.728 2.568 25.92 ;
    END
  END i[88]
  PIN i[89]
    DIRECTION INPUT ;
    USE SIGNAL ;
    PORT
      LAYER M3 ;
        RECT  2.592 25.882 2.61 25.92 ;
    END
  END i[89]
  PIN i[8]
    DIRECTION INPUT ;
    USE SIGNAL ;
    PORT
      LAYER M5 ;
        RECT  32.064 25.728 32.088 25.92 ;
    END
  END i[8]
  PIN i[90]
    DIRECTION INPUT ;
    USE SIGNAL ;
    PORT
      LAYER M5 ;
        RECT  2.64 25.728 2.664 25.92 ;
    END
  END i[90]
  PIN i[91]
    DIRECTION INPUT ;
    USE SIGNAL ;
    PORT
      LAYER M3 ;
        RECT  2.736 25.882 2.754 25.92 ;
    END
  END i[91]
  PIN i[92]
    DIRECTION INPUT ;
    USE SIGNAL ;
    PORT
      LAYER M5 ;
        RECT  2.832 25.728 2.856 25.92 ;
    END
  END i[92]
  PIN i[93]
    DIRECTION INPUT ;
    USE SIGNAL ;
    PORT
      LAYER M3 ;
        RECT  2.88 25.882 2.898 25.92 ;
    END
  END i[93]
  PIN i[94]
    DIRECTION INPUT ;
    USE SIGNAL ;
    PORT
      LAYER M5 ;
        RECT  3.024 25.728 3.048 25.92 ;
    END
  END i[94]
  PIN i[95]
    DIRECTION INPUT ;
    USE SIGNAL ;
    PORT
      LAYER M3 ;
        RECT  3.096 25.882 3.114 25.92 ;
    END
  END i[95]
  PIN i[96]
    DIRECTION INPUT ;
    USE SIGNAL ;
    PORT
      LAYER M5 ;
        RECT  3.12 25.728 3.144 25.92 ;
    END
  END i[96]
  PIN i[97]
    DIRECTION INPUT ;
    USE SIGNAL ;
    PORT
      LAYER M3 ;
        RECT  3.24 25.882 3.258 25.92 ;
    END
  END i[97]
  PIN i[98]
    DIRECTION INPUT ;
    USE SIGNAL ;
    PORT
      LAYER M5 ;
        RECT  3.312 25.728 3.336 25.92 ;
    END
  END i[98]
  PIN i[99]
    DIRECTION INPUT ;
    USE SIGNAL ;
    PORT
      LAYER M3 ;
        RECT  3.384 25.882 3.402 25.92 ;
    END
  END i[99]
  PIN i[9]
    DIRECTION INPUT ;
    USE SIGNAL ;
    PORT
      LAYER M3 ;
        RECT  32.184 25.882 32.202 25.92 ;
    END
  END i[9]
  PIN i_v[0]
    DIRECTION INPUT ;
    USE SIGNAL ;
    PORT
      LAYER M5 ;
        RECT  32.544 25.728 32.568 25.92 ;
    END
  END i_v[0]
  PIN i_v[1]
    DIRECTION INPUT ;
    USE SIGNAL ;
    PORT
      LAYER M3 ;
        RECT  33.768 25.882 33.786 25.92 ;
    END
  END i_v[1]
  PIN i_v[2]
    DIRECTION INPUT ;
    USE SIGNAL ;
    PORT
      LAYER M5 ;
        RECT  34.944 25.728 34.968 25.92 ;
    END
  END i_v[2]
  PIN i_v[3]
    DIRECTION INPUT ;
    USE SIGNAL ;
    PORT
      LAYER M3 ;
        RECT  36.144 25.882 36.162 25.92 ;
    END
  END i_v[3]
  PIN i_v[4]
    DIRECTION INPUT ;
    USE SIGNAL ;
    PORT
      LAYER M5 ;
        RECT  37.344 25.728 37.368 25.92 ;
    END
  END i_v[4]
  PIN i_v[5]
    DIRECTION INPUT ;
    USE SIGNAL ;
    PORT
      LAYER M3 ;
        RECT  38.736 25.882 38.754 25.92 ;
    END
  END i_v[5]
  PIN i_v[6]
    DIRECTION INPUT ;
    USE SIGNAL ;
    PORT
      LAYER M5 ;
        RECT  39.696 25.728 39.72 25.92 ;
    END
  END i_v[6]
  PIN i_v[7]
    DIRECTION INPUT ;
    USE SIGNAL ;
    PORT
      LAYER M3 ;
        RECT  40.896 25.882 40.914 25.92 ;
    END
  END i_v[7]
  PIN o[0]
    DIRECTION OUTPUT ;
    USE SIGNAL ;
    PORT
      LAYER M5 ;
        RECT  31.488 0 31.512 0.192 ;
    END
  END o[0]
  PIN o[100]
    DIRECTION OUTPUT ;
    USE SIGNAL ;
    PORT
      LAYER M5 ;
        RECT  3.504 0 3.528 0.192 ;
    END
  END o[100]
  PIN o[101]
    DIRECTION OUTPUT ;
    USE SIGNAL ;
    PORT
      LAYER M3 ;
        RECT  3.528 0 3.546 0.038 ;
    END
  END o[101]
  PIN o[102]
    DIRECTION OUTPUT ;
    USE SIGNAL ;
    PORT
      LAYER M5 ;
        RECT  3.6 0 3.624 0.192 ;
    END
  END o[102]
  PIN o[103]
    DIRECTION OUTPUT ;
    USE SIGNAL ;
    PORT
      LAYER M3 ;
        RECT  3.672 0 3.69 0.038 ;
    END
  END o[103]
  PIN o[104]
    DIRECTION OUTPUT ;
    USE SIGNAL ;
    PORT
      LAYER M5 ;
        RECT  3.792 0 3.816 0.192 ;
    END
  END o[104]
  PIN o[105]
    DIRECTION OUTPUT ;
    USE SIGNAL ;
    PORT
      LAYER M3 ;
        RECT  3.888 0 3.906 0.038 ;
    END
  END o[105]
  PIN o[106]
    DIRECTION OUTPUT ;
    USE SIGNAL ;
    PORT
      LAYER M5 ;
        RECT  3.984 0 4.008 0.192 ;
    END
  END o[106]
  PIN o[107]
    DIRECTION OUTPUT ;
    USE SIGNAL ;
    PORT
      LAYER M3 ;
        RECT  4.032 0 4.05 0.038 ;
    END
  END o[107]
  PIN o[108]
    DIRECTION OUTPUT ;
    USE SIGNAL ;
    PORT
      LAYER M5 ;
        RECT  4.08 0 4.104 0.192 ;
    END
  END o[108]
  PIN o[109]
    DIRECTION OUTPUT ;
    USE SIGNAL ;
    PORT
      LAYER M3 ;
        RECT  4.176 0 4.194 0.038 ;
    END
  END o[109]
  PIN o[10]
    DIRECTION OUTPUT ;
    USE SIGNAL ;
    PORT
      LAYER M5 ;
        RECT  32.256 0 32.28 0.192 ;
    END
  END o[10]
  PIN o[110]
    DIRECTION OUTPUT ;
    USE SIGNAL ;
    PORT
      LAYER M5 ;
        RECT  4.272 0 4.296 0.192 ;
    END
  END o[110]
  PIN o[111]
    DIRECTION OUTPUT ;
    USE SIGNAL ;
    PORT
      LAYER M3 ;
        RECT  4.32 0 4.338 0.038 ;
    END
  END o[111]
  PIN o[112]
    DIRECTION OUTPUT ;
    USE SIGNAL ;
    PORT
      LAYER M5 ;
        RECT  4.368 0 4.392 0.192 ;
    END
  END o[112]
  PIN o[113]
    DIRECTION OUTPUT ;
    USE SIGNAL ;
    PORT
      LAYER M3 ;
        RECT  4.464 0 4.482 0.038 ;
    END
  END o[113]
  PIN o[114]
    DIRECTION OUTPUT ;
    USE SIGNAL ;
    PORT
      LAYER M5 ;
        RECT  4.56 0 4.584 0.192 ;
    END
  END o[114]
  PIN o[115]
    DIRECTION OUTPUT ;
    USE SIGNAL ;
    PORT
      LAYER M3 ;
        RECT  4.68 0 4.698 0.038 ;
    END
  END o[115]
  PIN o[116]
    DIRECTION OUTPUT ;
    USE SIGNAL ;
    PORT
      LAYER M5 ;
        RECT  4.752 0 4.776 0.192 ;
    END
  END o[116]
  PIN o[117]
    DIRECTION OUTPUT ;
    USE SIGNAL ;
    PORT
      LAYER M3 ;
        RECT  4.824 0 4.842 0.038 ;
    END
  END o[117]
  PIN o[118]
    DIRECTION OUTPUT ;
    USE SIGNAL ;
    PORT
      LAYER M5 ;
        RECT  4.848 0 4.872 0.192 ;
    END
  END o[118]
  PIN o[119]
    DIRECTION OUTPUT ;
    USE SIGNAL ;
    PORT
      LAYER M3 ;
        RECT  4.968 0 4.986 0.038 ;
    END
  END o[119]
  PIN o[11]
    DIRECTION OUTPUT ;
    USE SIGNAL ;
    PORT
      LAYER M3 ;
        RECT  32.328 0 32.346 0.038 ;
    END
  END o[11]
  PIN o[120]
    DIRECTION OUTPUT ;
    USE SIGNAL ;
    PORT
      LAYER M5 ;
        RECT  5.04 0 5.064 0.192 ;
    END
  END o[120]
  PIN o[121]
    DIRECTION OUTPUT ;
    USE SIGNAL ;
    PORT
      LAYER M3 ;
        RECT  5.112 0 5.13 0.038 ;
    END
  END o[121]
  PIN o[122]
    DIRECTION OUTPUT ;
    USE SIGNAL ;
    PORT
      LAYER M5 ;
        RECT  5.232 0 5.256 0.192 ;
    END
  END o[122]
  PIN o[123]
    DIRECTION OUTPUT ;
    USE SIGNAL ;
    PORT
      LAYER M3 ;
        RECT  5.256 0 5.274 0.038 ;
    END
  END o[123]
  PIN o[124]
    DIRECTION OUTPUT ;
    USE SIGNAL ;
    PORT
      LAYER M5 ;
        RECT  5.328 0 5.352 0.192 ;
    END
  END o[124]
  PIN o[125]
    DIRECTION OUTPUT ;
    USE SIGNAL ;
    PORT
      LAYER M3 ;
        RECT  5.472 0 5.49 0.038 ;
    END
  END o[125]
  PIN o[126]
    DIRECTION OUTPUT ;
    USE SIGNAL ;
    PORT
      LAYER M5 ;
        RECT  5.52 0 5.544 0.192 ;
    END
  END o[126]
  PIN o[127]
    DIRECTION OUTPUT ;
    USE SIGNAL ;
    PORT
      LAYER M3 ;
        RECT  5.544 0 5.562 0.038 ;
    END
  END o[127]
  PIN o[128]
    DIRECTION OUTPUT ;
    USE SIGNAL ;
    PORT
      LAYER M5 ;
        RECT  6.144 0 6.168 0.192 ;
    END
  END o[128]
  PIN o[129]
    DIRECTION OUTPUT ;
    USE SIGNAL ;
    PORT
      LAYER M3 ;
        RECT  6.192 0 6.21 0.038 ;
    END
  END o[129]
  PIN o[12]
    DIRECTION OUTPUT ;
    USE SIGNAL ;
    PORT
      LAYER M5 ;
        RECT  32.448 0 32.472 0.192 ;
    END
  END o[12]
  PIN o[130]
    DIRECTION OUTPUT ;
    USE SIGNAL ;
    PORT
      LAYER M5 ;
        RECT  6.24 0 6.264 0.192 ;
    END
  END o[130]
  PIN o[131]
    DIRECTION OUTPUT ;
    USE SIGNAL ;
    PORT
      LAYER M3 ;
        RECT  6.264 0 6.282 0.038 ;
    END
  END o[131]
  PIN o[132]
    DIRECTION OUTPUT ;
    USE SIGNAL ;
    PORT
      LAYER M5 ;
        RECT  6.336 0 6.36 0.192 ;
    END
  END o[132]
  PIN o[133]
    DIRECTION OUTPUT ;
    USE SIGNAL ;
    PORT
      LAYER M3 ;
        RECT  6.336 0 6.354 0.038 ;
    END
  END o[133]
  PIN o[134]
    DIRECTION OUTPUT ;
    USE SIGNAL ;
    PORT
      LAYER M5 ;
        RECT  6.432 0 6.456 0.192 ;
    END
  END o[134]
  PIN o[135]
    DIRECTION OUTPUT ;
    USE SIGNAL ;
    PORT
      LAYER M3 ;
        RECT  6.408 0 6.426 0.038 ;
    END
  END o[135]
  PIN o[136]
    DIRECTION OUTPUT ;
    USE SIGNAL ;
    PORT
      LAYER M5 ;
        RECT  6.528 0 6.552 0.192 ;
    END
  END o[136]
  PIN o[137]
    DIRECTION OUTPUT ;
    USE SIGNAL ;
    PORT
      LAYER M3 ;
        RECT  6.48 0 6.498 0.038 ;
    END
  END o[137]
  PIN o[138]
    DIRECTION OUTPUT ;
    USE SIGNAL ;
    PORT
      LAYER M5 ;
        RECT  6.624 0 6.648 0.192 ;
    END
  END o[138]
  PIN o[139]
    DIRECTION OUTPUT ;
    USE SIGNAL ;
    PORT
      LAYER M3 ;
        RECT  6.552 0 6.57 0.038 ;
    END
  END o[139]
  PIN o[13]
    DIRECTION OUTPUT ;
    USE SIGNAL ;
    PORT
      LAYER M3 ;
        RECT  32.472 0 32.49 0.038 ;
    END
  END o[13]
  PIN o[140]
    DIRECTION OUTPUT ;
    USE SIGNAL ;
    PORT
      LAYER M5 ;
        RECT  6.72 0 6.744 0.192 ;
    END
  END o[140]
  PIN o[141]
    DIRECTION OUTPUT ;
    USE SIGNAL ;
    PORT
      LAYER M3 ;
        RECT  6.696 0 6.714 0.038 ;
    END
  END o[141]
  PIN o[142]
    DIRECTION OUTPUT ;
    USE SIGNAL ;
    PORT
      LAYER M5 ;
        RECT  6.816 0 6.84 0.192 ;
    END
  END o[142]
  PIN o[143]
    DIRECTION OUTPUT ;
    USE SIGNAL ;
    PORT
      LAYER M3 ;
        RECT  6.912 0 6.93 0.038 ;
    END
  END o[143]
  PIN o[144]
    DIRECTION OUTPUT ;
    USE SIGNAL ;
    PORT
      LAYER M5 ;
        RECT  6.912 0 6.936 0.192 ;
    END
  END o[144]
  PIN o[145]
    DIRECTION OUTPUT ;
    USE SIGNAL ;
    PORT
      LAYER M3 ;
        RECT  7.056 0 7.074 0.038 ;
    END
  END o[145]
  PIN o[146]
    DIRECTION OUTPUT ;
    USE SIGNAL ;
    PORT
      LAYER M5 ;
        RECT  7.104 0 7.128 0.192 ;
    END
  END o[146]
  PIN o[147]
    DIRECTION OUTPUT ;
    USE SIGNAL ;
    PORT
      LAYER M3 ;
        RECT  7.2 0 7.218 0.038 ;
    END
  END o[147]
  PIN o[148]
    DIRECTION OUTPUT ;
    USE SIGNAL ;
    PORT
      LAYER M5 ;
        RECT  7.296 0 7.32 0.192 ;
    END
  END o[148]
  PIN o[149]
    DIRECTION OUTPUT ;
    USE SIGNAL ;
    PORT
      LAYER M3 ;
        RECT  7.344 0 7.362 0.038 ;
    END
  END o[149]
  PIN o[14]
    DIRECTION OUTPUT ;
    USE SIGNAL ;
    PORT
      LAYER M3 ;
        RECT  32.544 0 32.562 0.038 ;
    END
  END o[14]
  PIN o[150]
    DIRECTION OUTPUT ;
    USE SIGNAL ;
    PORT
      LAYER M5 ;
        RECT  7.392 0 7.416 0.192 ;
    END
  END o[150]
  PIN o[151]
    DIRECTION OUTPUT ;
    USE SIGNAL ;
    PORT
      LAYER M3 ;
        RECT  7.488 0 7.506 0.038 ;
    END
  END o[151]
  PIN o[152]
    DIRECTION OUTPUT ;
    USE SIGNAL ;
    PORT
      LAYER M5 ;
        RECT  7.584 0 7.608 0.192 ;
    END
  END o[152]
  PIN o[153]
    DIRECTION OUTPUT ;
    USE SIGNAL ;
    PORT
      LAYER M3 ;
        RECT  7.704 0 7.722 0.038 ;
    END
  END o[153]
  PIN o[154]
    DIRECTION OUTPUT ;
    USE SIGNAL ;
    PORT
      LAYER M5 ;
        RECT  7.776 0 7.8 0.192 ;
    END
  END o[154]
  PIN o[155]
    DIRECTION OUTPUT ;
    USE SIGNAL ;
    PORT
      LAYER M3 ;
        RECT  7.848 0 7.866 0.038 ;
    END
  END o[155]
  PIN o[156]
    DIRECTION OUTPUT ;
    USE SIGNAL ;
    PORT
      LAYER M5 ;
        RECT  7.872 0 7.896 0.192 ;
    END
  END o[156]
  PIN o[157]
    DIRECTION OUTPUT ;
    USE SIGNAL ;
    PORT
      LAYER M3 ;
        RECT  7.992 0 8.01 0.038 ;
    END
  END o[157]
  PIN o[158]
    DIRECTION OUTPUT ;
    USE SIGNAL ;
    PORT
      LAYER M5 ;
        RECT  8.064 0 8.088 0.192 ;
    END
  END o[158]
  PIN o[159]
    DIRECTION OUTPUT ;
    USE SIGNAL ;
    PORT
      LAYER M3 ;
        RECT  8.136 0 8.154 0.038 ;
    END
  END o[159]
  PIN o[15]
    DIRECTION OUTPUT ;
    USE SIGNAL ;
    PORT
      LAYER M5 ;
        RECT  33.216 0 33.24 0.192 ;
    END
  END o[15]
  PIN o[160]
    DIRECTION OUTPUT ;
    USE SIGNAL ;
    PORT
      LAYER M5 ;
        RECT  8.256 0 8.28 0.192 ;
    END
  END o[160]
  PIN o[161]
    DIRECTION OUTPUT ;
    USE SIGNAL ;
    PORT
      LAYER M3 ;
        RECT  8.28 0 8.298 0.038 ;
    END
  END o[161]
  PIN o[162]
    DIRECTION OUTPUT ;
    USE SIGNAL ;
    PORT
      LAYER M5 ;
        RECT  8.352 0 8.376 0.192 ;
    END
  END o[162]
  PIN o[163]
    DIRECTION OUTPUT ;
    USE SIGNAL ;
    PORT
      LAYER M3 ;
        RECT  8.496 0 8.514 0.038 ;
    END
  END o[163]
  PIN o[164]
    DIRECTION OUTPUT ;
    USE SIGNAL ;
    PORT
      LAYER M5 ;
        RECT  8.544 0 8.568 0.192 ;
    END
  END o[164]
  PIN o[165]
    DIRECTION OUTPUT ;
    USE SIGNAL ;
    PORT
      LAYER M3 ;
        RECT  8.64 0 8.658 0.038 ;
    END
  END o[165]
  PIN o[166]
    DIRECTION OUTPUT ;
    USE SIGNAL ;
    PORT
      LAYER M5 ;
        RECT  8.736 0 8.76 0.192 ;
    END
  END o[166]
  PIN o[167]
    DIRECTION OUTPUT ;
    USE SIGNAL ;
    PORT
      LAYER M3 ;
        RECT  8.784 0 8.802 0.038 ;
    END
  END o[167]
  PIN o[168]
    DIRECTION OUTPUT ;
    USE SIGNAL ;
    PORT
      LAYER M5 ;
        RECT  8.832 0 8.856 0.192 ;
    END
  END o[168]
  PIN o[169]
    DIRECTION OUTPUT ;
    USE SIGNAL ;
    PORT
      LAYER M3 ;
        RECT  8.928 0 8.946 0.038 ;
    END
  END o[169]
  PIN o[16]
    DIRECTION OUTPUT ;
    USE SIGNAL ;
    PORT
      LAYER M3 ;
        RECT  33.192 0 33.21 0.038 ;
    END
  END o[16]
  PIN o[170]
    DIRECTION OUTPUT ;
    USE SIGNAL ;
    PORT
      LAYER M5 ;
        RECT  9.024 0 9.048 0.192 ;
    END
  END o[170]
  PIN o[171]
    DIRECTION OUTPUT ;
    USE SIGNAL ;
    PORT
      LAYER M3 ;
        RECT  9.144 0 9.162 0.038 ;
    END
  END o[171]
  PIN o[172]
    DIRECTION OUTPUT ;
    USE SIGNAL ;
    PORT
      LAYER M5 ;
        RECT  9.216 0 9.24 0.192 ;
    END
  END o[172]
  PIN o[173]
    DIRECTION OUTPUT ;
    USE SIGNAL ;
    PORT
      LAYER M3 ;
        RECT  9.288 0 9.306 0.038 ;
    END
  END o[173]
  PIN o[174]
    DIRECTION OUTPUT ;
    USE SIGNAL ;
    PORT
      LAYER M5 ;
        RECT  9.312 0 9.336 0.192 ;
    END
  END o[174]
  PIN o[175]
    DIRECTION OUTPUT ;
    USE SIGNAL ;
    PORT
      LAYER M3 ;
        RECT  9.432 0 9.45 0.038 ;
    END
  END o[175]
  PIN o[176]
    DIRECTION OUTPUT ;
    USE SIGNAL ;
    PORT
      LAYER M5 ;
        RECT  9.504 0 9.528 0.192 ;
    END
  END o[176]
  PIN o[177]
    DIRECTION OUTPUT ;
    USE SIGNAL ;
    PORT
      LAYER M3 ;
        RECT  9.576 0 9.594 0.038 ;
    END
  END o[177]
  PIN o[178]
    DIRECTION OUTPUT ;
    USE SIGNAL ;
    PORT
      LAYER M5 ;
        RECT  9.696 0 9.72 0.192 ;
    END
  END o[178]
  PIN o[179]
    DIRECTION OUTPUT ;
    USE SIGNAL ;
    PORT
      LAYER M3 ;
        RECT  9.72 0 9.738 0.038 ;
    END
  END o[179]
  PIN o[17]
    DIRECTION OUTPUT ;
    USE SIGNAL ;
    PORT
      LAYER M5 ;
        RECT  33.312 0 33.336 0.192 ;
    END
  END o[17]
  PIN o[180]
    DIRECTION OUTPUT ;
    USE SIGNAL ;
    PORT
      LAYER M5 ;
        RECT  9.792 0 9.816 0.192 ;
    END
  END o[180]
  PIN o[181]
    DIRECTION OUTPUT ;
    USE SIGNAL ;
    PORT
      LAYER M3 ;
        RECT  9.936 0 9.954 0.038 ;
    END
  END o[181]
  PIN o[182]
    DIRECTION OUTPUT ;
    USE SIGNAL ;
    PORT
      LAYER M5 ;
        RECT  9.984 0 10.008 0.192 ;
    END
  END o[182]
  PIN o[183]
    DIRECTION OUTPUT ;
    USE SIGNAL ;
    PORT
      LAYER M3 ;
        RECT  10.08 0 10.098 0.038 ;
    END
  END o[183]
  PIN o[184]
    DIRECTION OUTPUT ;
    USE SIGNAL ;
    PORT
      LAYER M5 ;
        RECT  10.176 0 10.2 0.192 ;
    END
  END o[184]
  PIN o[185]
    DIRECTION OUTPUT ;
    USE SIGNAL ;
    PORT
      LAYER M3 ;
        RECT  10.224 0 10.242 0.038 ;
    END
  END o[185]
  PIN o[186]
    DIRECTION OUTPUT ;
    USE SIGNAL ;
    PORT
      LAYER M5 ;
        RECT  10.272 0 10.296 0.192 ;
    END
  END o[186]
  PIN o[187]
    DIRECTION OUTPUT ;
    USE SIGNAL ;
    PORT
      LAYER M3 ;
        RECT  10.368 0 10.386 0.038 ;
    END
  END o[187]
  PIN o[188]
    DIRECTION OUTPUT ;
    USE SIGNAL ;
    PORT
      LAYER M5 ;
        RECT  10.464 0 10.488 0.192 ;
    END
  END o[188]
  PIN o[189]
    DIRECTION OUTPUT ;
    USE SIGNAL ;
    PORT
      LAYER M3 ;
        RECT  10.512 0 10.53 0.038 ;
    END
  END o[189]
  PIN o[18]
    DIRECTION OUTPUT ;
    USE SIGNAL ;
    PORT
      LAYER M3 ;
        RECT  33.264 0 33.282 0.038 ;
    END
  END o[18]
  PIN o[190]
    DIRECTION OUTPUT ;
    USE SIGNAL ;
    PORT
      LAYER M5 ;
        RECT  10.656 0 10.68 0.192 ;
    END
  END o[190]
  PIN o[191]
    DIRECTION OUTPUT ;
    USE SIGNAL ;
    PORT
      LAYER M3 ;
        RECT  10.728 0 10.746 0.038 ;
    END
  END o[191]
  PIN o[192]
    DIRECTION OUTPUT ;
    USE SIGNAL ;
    PORT
      LAYER M5 ;
        RECT  10.752 0 10.776 0.192 ;
    END
  END o[192]
  PIN o[193]
    DIRECTION OUTPUT ;
    USE SIGNAL ;
    PORT
      LAYER M3 ;
        RECT  10.872 0 10.89 0.038 ;
    END
  END o[193]
  PIN o[194]
    DIRECTION OUTPUT ;
    USE SIGNAL ;
    PORT
      LAYER M5 ;
        RECT  10.944 0 10.968 0.192 ;
    END
  END o[194]
  PIN o[195]
    DIRECTION OUTPUT ;
    USE SIGNAL ;
    PORT
      LAYER M3 ;
        RECT  10.944 0 10.962 0.038 ;
    END
  END o[195]
  PIN o[196]
    DIRECTION OUTPUT ;
    USE SIGNAL ;
    PORT
      LAYER M5 ;
        RECT  11.616 0 11.64 0.192 ;
    END
  END o[196]
  PIN o[197]
    DIRECTION OUTPUT ;
    USE SIGNAL ;
    PORT
      LAYER M3 ;
        RECT  11.592 0 11.61 0.038 ;
    END
  END o[197]
  PIN o[198]
    DIRECTION OUTPUT ;
    USE SIGNAL ;
    PORT
      LAYER M5 ;
        RECT  11.712 0 11.736 0.192 ;
    END
  END o[198]
  PIN o[199]
    DIRECTION OUTPUT ;
    USE SIGNAL ;
    PORT
      LAYER M3 ;
        RECT  11.664 0 11.682 0.038 ;
    END
  END o[199]
  PIN o[19]
    DIRECTION OUTPUT ;
    USE SIGNAL ;
    PORT
      LAYER M5 ;
        RECT  33.408 0 33.432 0.192 ;
    END
  END o[19]
  PIN o[1]
    DIRECTION OUTPUT ;
    USE SIGNAL ;
    PORT
      LAYER M3 ;
        RECT  31.536 0 31.554 0.038 ;
    END
  END o[1]
  PIN o[200]
    DIRECTION OUTPUT ;
    USE SIGNAL ;
    PORT
      LAYER M5 ;
        RECT  11.808 0 11.832 0.192 ;
    END
  END o[200]
  PIN o[201]
    DIRECTION OUTPUT ;
    USE SIGNAL ;
    PORT
      LAYER M3 ;
        RECT  11.736 0 11.754 0.038 ;
    END
  END o[201]
  PIN o[202]
    DIRECTION OUTPUT ;
    USE SIGNAL ;
    PORT
      LAYER M5 ;
        RECT  11.904 0 11.928 0.192 ;
    END
  END o[202]
  PIN o[203]
    DIRECTION OUTPUT ;
    USE SIGNAL ;
    PORT
      LAYER M3 ;
        RECT  11.808 0 11.826 0.038 ;
    END
  END o[203]
  PIN o[204]
    DIRECTION OUTPUT ;
    USE SIGNAL ;
    PORT
      LAYER M5 ;
        RECT  12 0 12.024 0.192 ;
    END
  END o[204]
  PIN o[205]
    DIRECTION OUTPUT ;
    USE SIGNAL ;
    PORT
      LAYER M3 ;
        RECT  11.88 0 11.898 0.038 ;
    END
  END o[205]
  PIN o[206]
    DIRECTION OUTPUT ;
    USE SIGNAL ;
    PORT
      LAYER M5 ;
        RECT  12.096 0 12.12 0.192 ;
    END
  END o[206]
  PIN o[207]
    DIRECTION OUTPUT ;
    USE SIGNAL ;
    PORT
      LAYER M3 ;
        RECT  11.952 0 11.97 0.038 ;
    END
  END o[207]
  PIN o[208]
    DIRECTION OUTPUT ;
    USE SIGNAL ;
    PORT
      LAYER M5 ;
        RECT  12.192 0 12.216 0.192 ;
    END
  END o[208]
  PIN o[209]
    DIRECTION OUTPUT ;
    USE SIGNAL ;
    PORT
      LAYER M3 ;
        RECT  12.096 0 12.114 0.038 ;
    END
  END o[209]
  PIN o[20]
    DIRECTION OUTPUT ;
    USE SIGNAL ;
    PORT
      LAYER M3 ;
        RECT  33.336 0 33.354 0.038 ;
    END
  END o[20]
  PIN o[210]
    DIRECTION OUTPUT ;
    USE SIGNAL ;
    PORT
      LAYER M5 ;
        RECT  12.288 0 12.312 0.192 ;
    END
  END o[210]
  PIN o[211]
    DIRECTION OUTPUT ;
    USE SIGNAL ;
    PORT
      LAYER M3 ;
        RECT  12.312 0 12.33 0.038 ;
    END
  END o[211]
  PIN o[212]
    DIRECTION OUTPUT ;
    USE SIGNAL ;
    PORT
      LAYER M5 ;
        RECT  38.832 0 38.856 0.192 ;
    END
  END o[212]
  PIN o[213]
    DIRECTION OUTPUT ;
    USE SIGNAL ;
    PORT
      LAYER M3 ;
        RECT  38.808 0 38.826 0.038 ;
    END
  END o[213]
  PIN o[214]
    DIRECTION OUTPUT ;
    USE SIGNAL ;
    PORT
      LAYER M5 ;
        RECT  38.928 0 38.952 0.192 ;
    END
  END o[214]
  PIN o[215]
    DIRECTION OUTPUT ;
    USE SIGNAL ;
    PORT
      LAYER M3 ;
        RECT  38.88 0 38.898 0.038 ;
    END
  END o[215]
  PIN o[216]
    DIRECTION OUTPUT ;
    USE SIGNAL ;
    PORT
      LAYER M5 ;
        RECT  39.024 0 39.048 0.192 ;
    END
  END o[216]
  PIN o[217]
    DIRECTION OUTPUT ;
    USE SIGNAL ;
    PORT
      LAYER M3 ;
        RECT  39.024 0 39.042 0.038 ;
    END
  END o[217]
  PIN o[218]
    DIRECTION OUTPUT ;
    USE SIGNAL ;
    PORT
      LAYER M5 ;
        RECT  39.12 0 39.144 0.192 ;
    END
  END o[218]
  PIN o[219]
    DIRECTION OUTPUT ;
    USE SIGNAL ;
    PORT
      LAYER M3 ;
        RECT  39.168 0 39.186 0.038 ;
    END
  END o[219]
  PIN o[21]
    DIRECTION OUTPUT ;
    USE SIGNAL ;
    PORT
      LAYER M5 ;
        RECT  33.504 0 33.528 0.192 ;
    END
  END o[21]
  PIN o[220]
    DIRECTION OUTPUT ;
    USE SIGNAL ;
    PORT
      LAYER M5 ;
        RECT  39.216 0 39.24 0.192 ;
    END
  END o[220]
  PIN o[221]
    DIRECTION OUTPUT ;
    USE SIGNAL ;
    PORT
      LAYER M3 ;
        RECT  39.312 0 39.33 0.038 ;
    END
  END o[221]
  PIN o[222]
    DIRECTION OUTPUT ;
    USE SIGNAL ;
    PORT
      LAYER M5 ;
        RECT  39.408 0 39.432 0.192 ;
    END
  END o[222]
  PIN o[223]
    DIRECTION OUTPUT ;
    USE SIGNAL ;
    PORT
      LAYER M3 ;
        RECT  39.456 0 39.474 0.038 ;
    END
  END o[223]
  PIN o[224]
    DIRECTION OUTPUT ;
    USE SIGNAL ;
    PORT
      LAYER M5 ;
        RECT  39.6 0 39.624 0.192 ;
    END
  END o[224]
  PIN o[225]
    DIRECTION OUTPUT ;
    USE SIGNAL ;
    PORT
      LAYER M3 ;
        RECT  39.672 0 39.69 0.038 ;
    END
  END o[225]
  PIN o[226]
    DIRECTION OUTPUT ;
    USE SIGNAL ;
    PORT
      LAYER M5 ;
        RECT  12.384 0 12.408 0.192 ;
    END
  END o[226]
  PIN o[227]
    DIRECTION OUTPUT ;
    USE SIGNAL ;
    PORT
      LAYER M3 ;
        RECT  12.456 0 12.474 0.038 ;
    END
  END o[227]
  PIN o[228]
    DIRECTION OUTPUT ;
    USE SIGNAL ;
    PORT
      LAYER M5 ;
        RECT  12.48 0 12.504 0.192 ;
    END
  END o[228]
  PIN o[229]
    DIRECTION OUTPUT ;
    USE SIGNAL ;
    PORT
      LAYER M3 ;
        RECT  12.6 0 12.618 0.038 ;
    END
  END o[229]
  PIN o[22]
    DIRECTION OUTPUT ;
    USE SIGNAL ;
    PORT
      LAYER M3 ;
        RECT  33.408 0 33.426 0.038 ;
    END
  END o[22]
  PIN o[230]
    DIRECTION OUTPUT ;
    USE SIGNAL ;
    PORT
      LAYER M5 ;
        RECT  12.672 0 12.696 0.192 ;
    END
  END o[230]
  PIN o[231]
    DIRECTION OUTPUT ;
    USE SIGNAL ;
    PORT
      LAYER M3 ;
        RECT  12.744 0 12.762 0.038 ;
    END
  END o[231]
  PIN o[232]
    DIRECTION OUTPUT ;
    USE SIGNAL ;
    PORT
      LAYER M5 ;
        RECT  12.864 0 12.888 0.192 ;
    END
  END o[232]
  PIN o[233]
    DIRECTION OUTPUT ;
    USE SIGNAL ;
    PORT
      LAYER M3 ;
        RECT  12.96 0 12.978 0.038 ;
    END
  END o[233]
  PIN o[234]
    DIRECTION OUTPUT ;
    USE SIGNAL ;
    PORT
      LAYER M5 ;
        RECT  12.96 0 12.984 0.192 ;
    END
  END o[234]
  PIN o[235]
    DIRECTION OUTPUT ;
    USE SIGNAL ;
    PORT
      LAYER M3 ;
        RECT  13.104 0 13.122 0.038 ;
    END
  END o[235]
  PIN o[236]
    DIRECTION OUTPUT ;
    USE SIGNAL ;
    PORT
      LAYER M5 ;
        RECT  13.152 0 13.176 0.192 ;
    END
  END o[236]
  PIN o[237]
    DIRECTION OUTPUT ;
    USE SIGNAL ;
    PORT
      LAYER M3 ;
        RECT  13.248 0 13.266 0.038 ;
    END
  END o[237]
  PIN o[238]
    DIRECTION OUTPUT ;
    USE SIGNAL ;
    PORT
      LAYER M5 ;
        RECT  13.344 0 13.368 0.192 ;
    END
  END o[238]
  PIN o[239]
    DIRECTION OUTPUT ;
    USE SIGNAL ;
    PORT
      LAYER M3 ;
        RECT  13.392 0 13.41 0.038 ;
    END
  END o[239]
  PIN o[23]
    DIRECTION OUTPUT ;
    USE SIGNAL ;
    PORT
      LAYER M5 ;
        RECT  33.6 0 33.624 0.192 ;
    END
  END o[23]
  PIN o[240]
    DIRECTION OUTPUT ;
    USE SIGNAL ;
    PORT
      LAYER M5 ;
        RECT  13.44 0 13.464 0.192 ;
    END
  END o[240]
  PIN o[241]
    DIRECTION OUTPUT ;
    USE SIGNAL ;
    PORT
      LAYER M3 ;
        RECT  13.536 0 13.554 0.038 ;
    END
  END o[241]
  PIN o[242]
    DIRECTION OUTPUT ;
    USE SIGNAL ;
    PORT
      LAYER M5 ;
        RECT  13.632 0 13.656 0.192 ;
    END
  END o[242]
  PIN o[243]
    DIRECTION OUTPUT ;
    USE SIGNAL ;
    PORT
      LAYER M3 ;
        RECT  13.752 0 13.77 0.038 ;
    END
  END o[243]
  PIN o[244]
    DIRECTION OUTPUT ;
    USE SIGNAL ;
    PORT
      LAYER M5 ;
        RECT  13.824 0 13.848 0.192 ;
    END
  END o[244]
  PIN o[245]
    DIRECTION OUTPUT ;
    USE SIGNAL ;
    PORT
      LAYER M3 ;
        RECT  13.896 0 13.914 0.038 ;
    END
  END o[245]
  PIN o[246]
    DIRECTION OUTPUT ;
    USE SIGNAL ;
    PORT
      LAYER M5 ;
        RECT  13.92 0 13.944 0.192 ;
    END
  END o[246]
  PIN o[247]
    DIRECTION OUTPUT ;
    USE SIGNAL ;
    PORT
      LAYER M3 ;
        RECT  14.04 0 14.058 0.038 ;
    END
  END o[247]
  PIN o[248]
    DIRECTION OUTPUT ;
    USE SIGNAL ;
    PORT
      LAYER M5 ;
        RECT  14.112 0 14.136 0.192 ;
    END
  END o[248]
  PIN o[249]
    DIRECTION OUTPUT ;
    USE SIGNAL ;
    PORT
      LAYER M3 ;
        RECT  14.184 0 14.202 0.038 ;
    END
  END o[249]
  PIN o[24]
    DIRECTION OUTPUT ;
    USE SIGNAL ;
    PORT
      LAYER M3 ;
        RECT  33.48 0 33.498 0.038 ;
    END
  END o[24]
  PIN o[250]
    DIRECTION OUTPUT ;
    USE SIGNAL ;
    PORT
      LAYER M5 ;
        RECT  14.304 0 14.328 0.192 ;
    END
  END o[250]
  PIN o[251]
    DIRECTION OUTPUT ;
    USE SIGNAL ;
    PORT
      LAYER M3 ;
        RECT  14.328 0 14.346 0.038 ;
    END
  END o[251]
  PIN o[252]
    DIRECTION OUTPUT ;
    USE SIGNAL ;
    PORT
      LAYER M5 ;
        RECT  14.4 0 14.424 0.192 ;
    END
  END o[252]
  PIN o[253]
    DIRECTION OUTPUT ;
    USE SIGNAL ;
    PORT
      LAYER M3 ;
        RECT  14.544 0 14.562 0.038 ;
    END
  END o[253]
  PIN o[254]
    DIRECTION OUTPUT ;
    USE SIGNAL ;
    PORT
      LAYER M5 ;
        RECT  14.592 0 14.616 0.192 ;
    END
  END o[254]
  PIN o[255]
    DIRECTION OUTPUT ;
    USE SIGNAL ;
    PORT
      LAYER M3 ;
        RECT  14.688 0 14.706 0.038 ;
    END
  END o[255]
  PIN o[256]
    DIRECTION OUTPUT ;
    USE SIGNAL ;
    PORT
      LAYER M5 ;
        RECT  14.784 0 14.808 0.192 ;
    END
  END o[256]
  PIN o[257]
    DIRECTION OUTPUT ;
    USE SIGNAL ;
    PORT
      LAYER M3 ;
        RECT  14.832 0 14.85 0.038 ;
    END
  END o[257]
  PIN o[258]
    DIRECTION OUTPUT ;
    USE SIGNAL ;
    PORT
      LAYER M5 ;
        RECT  14.88 0 14.904 0.192 ;
    END
  END o[258]
  PIN o[259]
    DIRECTION OUTPUT ;
    USE SIGNAL ;
    PORT
      LAYER M3 ;
        RECT  14.976 0 14.994 0.038 ;
    END
  END o[259]
  PIN o[25]
    DIRECTION OUTPUT ;
    USE SIGNAL ;
    PORT
      LAYER M5 ;
        RECT  33.696 0 33.72 0.192 ;
    END
  END o[25]
  PIN o[260]
    DIRECTION OUTPUT ;
    USE SIGNAL ;
    PORT
      LAYER M5 ;
        RECT  15.072 0 15.096 0.192 ;
    END
  END o[260]
  PIN o[261]
    DIRECTION OUTPUT ;
    USE SIGNAL ;
    PORT
      LAYER M3 ;
        RECT  15.12 0 15.138 0.038 ;
    END
  END o[261]
  PIN o[262]
    DIRECTION OUTPUT ;
    USE SIGNAL ;
    PORT
      LAYER M5 ;
        RECT  15.264 0 15.288 0.192 ;
    END
  END o[262]
  PIN o[263]
    DIRECTION OUTPUT ;
    USE SIGNAL ;
    PORT
      LAYER M3 ;
        RECT  15.336 0 15.354 0.038 ;
    END
  END o[263]
  PIN o[264]
    DIRECTION OUTPUT ;
    USE SIGNAL ;
    PORT
      LAYER M5 ;
        RECT  15.36 0 15.384 0.192 ;
    END
  END o[264]
  PIN o[265]
    DIRECTION OUTPUT ;
    USE SIGNAL ;
    PORT
      LAYER M3 ;
        RECT  15.48 0 15.498 0.038 ;
    END
  END o[265]
  PIN o[266]
    DIRECTION OUTPUT ;
    USE SIGNAL ;
    PORT
      LAYER M5 ;
        RECT  15.552 0 15.576 0.192 ;
    END
  END o[266]
  PIN o[267]
    DIRECTION OUTPUT ;
    USE SIGNAL ;
    PORT
      LAYER M3 ;
        RECT  15.624 0 15.642 0.038 ;
    END
  END o[267]
  PIN o[268]
    DIRECTION OUTPUT ;
    USE SIGNAL ;
    PORT
      LAYER M5 ;
        RECT  15.744 0 15.768 0.192 ;
    END
  END o[268]
  PIN o[269]
    DIRECTION OUTPUT ;
    USE SIGNAL ;
    PORT
      LAYER M3 ;
        RECT  15.768 0 15.786 0.038 ;
    END
  END o[269]
  PIN o[26]
    DIRECTION OUTPUT ;
    USE SIGNAL ;
    PORT
      LAYER M3 ;
        RECT  33.624 0 33.642 0.038 ;
    END
  END o[26]
  PIN o[270]
    DIRECTION OUTPUT ;
    USE SIGNAL ;
    PORT
      LAYER M5 ;
        RECT  15.84 0 15.864 0.192 ;
    END
  END o[270]
  PIN o[271]
    DIRECTION OUTPUT ;
    USE SIGNAL ;
    PORT
      LAYER M3 ;
        RECT  15.912 0 15.93 0.038 ;
    END
  END o[271]
  PIN o[272]
    DIRECTION OUTPUT ;
    USE SIGNAL ;
    PORT
      LAYER M5 ;
        RECT  16.032 0 16.056 0.192 ;
    END
  END o[272]
  PIN o[273]
    DIRECTION OUTPUT ;
    USE SIGNAL ;
    PORT
      LAYER M3 ;
        RECT  16.128 0 16.146 0.038 ;
    END
  END o[273]
  PIN o[274]
    DIRECTION OUTPUT ;
    USE SIGNAL ;
    PORT
      LAYER M5 ;
        RECT  16.224 0 16.248 0.192 ;
    END
  END o[274]
  PIN o[275]
    DIRECTION OUTPUT ;
    USE SIGNAL ;
    PORT
      LAYER M3 ;
        RECT  16.272 0 16.29 0.038 ;
    END
  END o[275]
  PIN o[276]
    DIRECTION OUTPUT ;
    USE SIGNAL ;
    PORT
      LAYER M5 ;
        RECT  16.32 0 16.344 0.192 ;
    END
  END o[276]
  PIN o[277]
    DIRECTION OUTPUT ;
    USE SIGNAL ;
    PORT
      LAYER M3 ;
        RECT  16.344 0 16.362 0.038 ;
    END
  END o[277]
  PIN o[278]
    DIRECTION OUTPUT ;
    USE SIGNAL ;
    PORT
      LAYER M5 ;
        RECT  16.944 0 16.968 0.192 ;
    END
  END o[278]
  PIN o[279]
    DIRECTION OUTPUT ;
    USE SIGNAL ;
    PORT
      LAYER M3 ;
        RECT  16.992 0 17.01 0.038 ;
    END
  END o[279]
  PIN o[27]
    DIRECTION OUTPUT ;
    USE SIGNAL ;
    PORT
      LAYER M5 ;
        RECT  33.792 0 33.816 0.192 ;
    END
  END o[27]
  PIN o[280]
    DIRECTION OUTPUT ;
    USE SIGNAL ;
    PORT
      LAYER M5 ;
        RECT  17.04 0 17.064 0.192 ;
    END
  END o[280]
  PIN o[281]
    DIRECTION OUTPUT ;
    USE SIGNAL ;
    PORT
      LAYER M3 ;
        RECT  17.064 0 17.082 0.038 ;
    END
  END o[281]
  PIN o[282]
    DIRECTION OUTPUT ;
    USE SIGNAL ;
    PORT
      LAYER M5 ;
        RECT  17.136 0 17.16 0.192 ;
    END
  END o[282]
  PIN o[283]
    DIRECTION OUTPUT ;
    USE SIGNAL ;
    PORT
      LAYER M3 ;
        RECT  17.136 0 17.154 0.038 ;
    END
  END o[283]
  PIN o[284]
    DIRECTION OUTPUT ;
    USE SIGNAL ;
    PORT
      LAYER M5 ;
        RECT  17.232 0 17.256 0.192 ;
    END
  END o[284]
  PIN o[285]
    DIRECTION OUTPUT ;
    USE SIGNAL ;
    PORT
      LAYER M3 ;
        RECT  17.208 0 17.226 0.038 ;
    END
  END o[285]
  PIN o[286]
    DIRECTION OUTPUT ;
    USE SIGNAL ;
    PORT
      LAYER M5 ;
        RECT  17.328 0 17.352 0.192 ;
    END
  END o[286]
  PIN o[287]
    DIRECTION OUTPUT ;
    USE SIGNAL ;
    PORT
      LAYER M3 ;
        RECT  17.28 0 17.298 0.038 ;
    END
  END o[287]
  PIN o[288]
    DIRECTION OUTPUT ;
    USE SIGNAL ;
    PORT
      LAYER M5 ;
        RECT  17.424 0 17.448 0.192 ;
    END
  END o[288]
  PIN o[289]
    DIRECTION OUTPUT ;
    USE SIGNAL ;
    PORT
      LAYER M3 ;
        RECT  17.352 0 17.37 0.038 ;
    END
  END o[289]
  PIN o[28]
    DIRECTION OUTPUT ;
    USE SIGNAL ;
    PORT
      LAYER M5 ;
        RECT  33.888 0 33.912 0.192 ;
    END
  END o[28]
  PIN o[290]
    DIRECTION OUTPUT ;
    USE SIGNAL ;
    PORT
      LAYER M5 ;
        RECT  17.52 0 17.544 0.192 ;
    END
  END o[290]
  PIN o[291]
    DIRECTION OUTPUT ;
    USE SIGNAL ;
    PORT
      LAYER M3 ;
        RECT  17.568 0 17.586 0.038 ;
    END
  END o[291]
  PIN o[292]
    DIRECTION OUTPUT ;
    USE SIGNAL ;
    PORT
      LAYER M5 ;
        RECT  17.616 0 17.64 0.192 ;
    END
  END o[292]
  PIN o[293]
    DIRECTION OUTPUT ;
    USE SIGNAL ;
    PORT
      LAYER M3 ;
        RECT  17.712 0 17.73 0.038 ;
    END
  END o[293]
  PIN o[294]
    DIRECTION OUTPUT ;
    USE SIGNAL ;
    PORT
      LAYER M5 ;
        RECT  17.808 0 17.832 0.192 ;
    END
  END o[294]
  PIN o[295]
    DIRECTION OUTPUT ;
    USE SIGNAL ;
    PORT
      LAYER M3 ;
        RECT  17.856 0 17.874 0.038 ;
    END
  END o[295]
  PIN o[296]
    DIRECTION OUTPUT ;
    USE SIGNAL ;
    PORT
      LAYER M5 ;
        RECT  17.904 0 17.928 0.192 ;
    END
  END o[296]
  PIN o[297]
    DIRECTION OUTPUT ;
    USE SIGNAL ;
    PORT
      LAYER M3 ;
        RECT  18 0 18.018 0.038 ;
    END
  END o[297]
  PIN o[298]
    DIRECTION OUTPUT ;
    USE SIGNAL ;
    PORT
      LAYER M5 ;
        RECT  18.096 0 18.12 0.192 ;
    END
  END o[298]
  PIN o[299]
    DIRECTION OUTPUT ;
    USE SIGNAL ;
    PORT
      LAYER M3 ;
        RECT  18.144 0 18.162 0.038 ;
    END
  END o[299]
  PIN o[29]
    DIRECTION OUTPUT ;
    USE SIGNAL ;
    PORT
      LAYER M3 ;
        RECT  33.912 0 33.93 0.038 ;
    END
  END o[29]
  PIN o[2]
    DIRECTION OUTPUT ;
    USE SIGNAL ;
    PORT
      LAYER M5 ;
        RECT  31.584 0 31.608 0.192 ;
    END
  END o[2]
  PIN o[300]
    DIRECTION OUTPUT ;
    USE SIGNAL ;
    PORT
      LAYER M5 ;
        RECT  18.288 0 18.312 0.192 ;
    END
  END o[300]
  PIN o[301]
    DIRECTION OUTPUT ;
    USE SIGNAL ;
    PORT
      LAYER M3 ;
        RECT  18.36 0 18.378 0.038 ;
    END
  END o[301]
  PIN o[302]
    DIRECTION OUTPUT ;
    USE SIGNAL ;
    PORT
      LAYER M5 ;
        RECT  18.384 0 18.408 0.192 ;
    END
  END o[302]
  PIN o[303]
    DIRECTION OUTPUT ;
    USE SIGNAL ;
    PORT
      LAYER M3 ;
        RECT  18.504 0 18.522 0.038 ;
    END
  END o[303]
  PIN o[304]
    DIRECTION OUTPUT ;
    USE SIGNAL ;
    PORT
      LAYER M5 ;
        RECT  18.576 0 18.6 0.192 ;
    END
  END o[304]
  PIN o[305]
    DIRECTION OUTPUT ;
    USE SIGNAL ;
    PORT
      LAYER M3 ;
        RECT  18.648 0 18.666 0.038 ;
    END
  END o[305]
  PIN o[306]
    DIRECTION OUTPUT ;
    USE SIGNAL ;
    PORT
      LAYER M5 ;
        RECT  18.768 0 18.792 0.192 ;
    END
  END o[306]
  PIN o[307]
    DIRECTION OUTPUT ;
    USE SIGNAL ;
    PORT
      LAYER M3 ;
        RECT  18.792 0 18.81 0.038 ;
    END
  END o[307]
  PIN o[308]
    DIRECTION OUTPUT ;
    USE SIGNAL ;
    PORT
      LAYER M5 ;
        RECT  18.864 0 18.888 0.192 ;
    END
  END o[308]
  PIN o[309]
    DIRECTION OUTPUT ;
    USE SIGNAL ;
    PORT
      LAYER M3 ;
        RECT  18.936 0 18.954 0.038 ;
    END
  END o[309]
  PIN o[30]
    DIRECTION OUTPUT ;
    USE SIGNAL ;
    PORT
      LAYER M5 ;
        RECT  33.984 0 34.008 0.192 ;
    END
  END o[30]
  PIN o[310]
    DIRECTION OUTPUT ;
    USE SIGNAL ;
    PORT
      LAYER M5 ;
        RECT  19.056 0 19.08 0.192 ;
    END
  END o[310]
  PIN o[311]
    DIRECTION OUTPUT ;
    USE SIGNAL ;
    PORT
      LAYER M3 ;
        RECT  19.152 0 19.17 0.038 ;
    END
  END o[311]
  PIN o[312]
    DIRECTION OUTPUT ;
    USE SIGNAL ;
    PORT
      LAYER M5 ;
        RECT  19.248 0 19.272 0.192 ;
    END
  END o[312]
  PIN o[313]
    DIRECTION OUTPUT ;
    USE SIGNAL ;
    PORT
      LAYER M3 ;
        RECT  19.296 0 19.314 0.038 ;
    END
  END o[313]
  PIN o[314]
    DIRECTION OUTPUT ;
    USE SIGNAL ;
    PORT
      LAYER M5 ;
        RECT  19.344 0 19.368 0.192 ;
    END
  END o[314]
  PIN o[315]
    DIRECTION OUTPUT ;
    USE SIGNAL ;
    PORT
      LAYER M3 ;
        RECT  19.44 0 19.458 0.038 ;
    END
  END o[315]
  PIN o[316]
    DIRECTION OUTPUT ;
    USE SIGNAL ;
    PORT
      LAYER M5 ;
        RECT  19.536 0 19.56 0.192 ;
    END
  END o[316]
  PIN o[317]
    DIRECTION OUTPUT ;
    USE SIGNAL ;
    PORT
      LAYER M3 ;
        RECT  19.584 0 19.602 0.038 ;
    END
  END o[317]
  PIN o[318]
    DIRECTION OUTPUT ;
    USE SIGNAL ;
    PORT
      LAYER M5 ;
        RECT  19.632 0 19.656 0.192 ;
    END
  END o[318]
  PIN o[319]
    DIRECTION OUTPUT ;
    USE SIGNAL ;
    PORT
      LAYER M3 ;
        RECT  19.728 0 19.746 0.038 ;
    END
  END o[319]
  PIN o[31]
    DIRECTION OUTPUT ;
    USE SIGNAL ;
    PORT
      LAYER M3 ;
        RECT  34.056 0 34.074 0.038 ;
    END
  END o[31]
  PIN o[320]
    DIRECTION OUTPUT ;
    USE SIGNAL ;
    PORT
      LAYER M5 ;
        RECT  19.824 0 19.848 0.192 ;
    END
  END o[320]
  PIN o[321]
    DIRECTION OUTPUT ;
    USE SIGNAL ;
    PORT
      LAYER M3 ;
        RECT  19.944 0 19.962 0.038 ;
    END
  END o[321]
  PIN o[322]
    DIRECTION OUTPUT ;
    USE SIGNAL ;
    PORT
      LAYER M5 ;
        RECT  20.016 0 20.04 0.192 ;
    END
  END o[322]
  PIN o[323]
    DIRECTION OUTPUT ;
    USE SIGNAL ;
    PORT
      LAYER M3 ;
        RECT  20.088 0 20.106 0.038 ;
    END
  END o[323]
  PIN o[324]
    DIRECTION OUTPUT ;
    USE SIGNAL ;
    PORT
      LAYER M5 ;
        RECT  20.112 0 20.136 0.192 ;
    END
  END o[324]
  PIN o[325]
    DIRECTION OUTPUT ;
    USE SIGNAL ;
    PORT
      LAYER M3 ;
        RECT  20.232 0 20.25 0.038 ;
    END
  END o[325]
  PIN o[326]
    DIRECTION OUTPUT ;
    USE SIGNAL ;
    PORT
      LAYER M5 ;
        RECT  20.304 0 20.328 0.192 ;
    END
  END o[326]
  PIN o[327]
    DIRECTION OUTPUT ;
    USE SIGNAL ;
    PORT
      LAYER M3 ;
        RECT  20.376 0 20.394 0.038 ;
    END
  END o[327]
  PIN o[328]
    DIRECTION OUTPUT ;
    USE SIGNAL ;
    PORT
      LAYER M5 ;
        RECT  20.496 0 20.52 0.192 ;
    END
  END o[328]
  PIN o[329]
    DIRECTION OUTPUT ;
    USE SIGNAL ;
    PORT
      LAYER M3 ;
        RECT  20.592 0 20.61 0.038 ;
    END
  END o[329]
  PIN o[32]
    DIRECTION OUTPUT ;
    USE SIGNAL ;
    PORT
      LAYER M5 ;
        RECT  34.176 0 34.2 0.192 ;
    END
  END o[32]
  PIN o[330]
    DIRECTION OUTPUT ;
    USE SIGNAL ;
    PORT
      LAYER M5 ;
        RECT  20.592 0 20.616 0.192 ;
    END
  END o[330]
  PIN o[331]
    DIRECTION OUTPUT ;
    USE SIGNAL ;
    PORT
      LAYER M3 ;
        RECT  20.736 0 20.754 0.038 ;
    END
  END o[331]
  PIN o[332]
    DIRECTION OUTPUT ;
    USE SIGNAL ;
    PORT
      LAYER M5 ;
        RECT  20.784 0 20.808 0.192 ;
    END
  END o[332]
  PIN o[333]
    DIRECTION OUTPUT ;
    USE SIGNAL ;
    PORT
      LAYER M3 ;
        RECT  20.88 0 20.898 0.038 ;
    END
  END o[333]
  PIN o[334]
    DIRECTION OUTPUT ;
    USE SIGNAL ;
    PORT
      LAYER M5 ;
        RECT  20.976 0 21 0.192 ;
    END
  END o[334]
  PIN o[335]
    DIRECTION OUTPUT ;
    USE SIGNAL ;
    PORT
      LAYER M3 ;
        RECT  21.024 0 21.042 0.038 ;
    END
  END o[335]
  PIN o[336]
    DIRECTION OUTPUT ;
    USE SIGNAL ;
    PORT
      LAYER M5 ;
        RECT  21.072 0 21.096 0.192 ;
    END
  END o[336]
  PIN o[337]
    DIRECTION OUTPUT ;
    USE SIGNAL ;
    PORT
      LAYER M3 ;
        RECT  21.168 0 21.186 0.038 ;
    END
  END o[337]
  PIN o[338]
    DIRECTION OUTPUT ;
    USE SIGNAL ;
    PORT
      LAYER M5 ;
        RECT  21.264 0 21.288 0.192 ;
    END
  END o[338]
  PIN o[339]
    DIRECTION OUTPUT ;
    USE SIGNAL ;
    PORT
      LAYER M3 ;
        RECT  21.384 0 21.402 0.038 ;
    END
  END o[339]
  PIN o[33]
    DIRECTION OUTPUT ;
    USE SIGNAL ;
    PORT
      LAYER M3 ;
        RECT  34.2 0 34.218 0.038 ;
    END
  END o[33]
  PIN o[340]
    DIRECTION OUTPUT ;
    USE SIGNAL ;
    PORT
      LAYER M5 ;
        RECT  21.456 0 21.48 0.192 ;
    END
  END o[340]
  PIN o[341]
    DIRECTION OUTPUT ;
    USE SIGNAL ;
    PORT
      LAYER M3 ;
        RECT  21.528 0 21.546 0.038 ;
    END
  END o[341]
  PIN o[342]
    DIRECTION OUTPUT ;
    USE SIGNAL ;
    PORT
      LAYER M5 ;
        RECT  21.552 0 21.576 0.192 ;
    END
  END o[342]
  PIN o[343]
    DIRECTION OUTPUT ;
    USE SIGNAL ;
    PORT
      LAYER M3 ;
        RECT  21.672 0 21.69 0.038 ;
    END
  END o[343]
  PIN o[344]
    DIRECTION OUTPUT ;
    USE SIGNAL ;
    PORT
      LAYER M5 ;
        RECT  21.744 0 21.768 0.192 ;
    END
  END o[344]
  PIN o[345]
    DIRECTION OUTPUT ;
    USE SIGNAL ;
    PORT
      LAYER M3 ;
        RECT  21.744 0 21.762 0.038 ;
    END
  END o[345]
  PIN o[346]
    DIRECTION OUTPUT ;
    USE SIGNAL ;
    PORT
      LAYER M5 ;
        RECT  22.416 0 22.44 0.192 ;
    END
  END o[346]
  PIN o[347]
    DIRECTION OUTPUT ;
    USE SIGNAL ;
    PORT
      LAYER M3 ;
        RECT  22.392 0 22.41 0.038 ;
    END
  END o[347]
  PIN o[348]
    DIRECTION OUTPUT ;
    USE SIGNAL ;
    PORT
      LAYER M5 ;
        RECT  22.512 0 22.536 0.192 ;
    END
  END o[348]
  PIN o[349]
    DIRECTION OUTPUT ;
    USE SIGNAL ;
    PORT
      LAYER M3 ;
        RECT  22.464 0 22.482 0.038 ;
    END
  END o[349]
  PIN o[34]
    DIRECTION OUTPUT ;
    USE SIGNAL ;
    PORT
      LAYER M5 ;
        RECT  34.272 0 34.296 0.192 ;
    END
  END o[34]
  PIN o[350]
    DIRECTION OUTPUT ;
    USE SIGNAL ;
    PORT
      LAYER M5 ;
        RECT  22.608 0 22.632 0.192 ;
    END
  END o[350]
  PIN o[351]
    DIRECTION OUTPUT ;
    USE SIGNAL ;
    PORT
      LAYER M3 ;
        RECT  22.536 0 22.554 0.038 ;
    END
  END o[351]
  PIN o[352]
    DIRECTION OUTPUT ;
    USE SIGNAL ;
    PORT
      LAYER M5 ;
        RECT  22.704 0 22.728 0.192 ;
    END
  END o[352]
  PIN o[353]
    DIRECTION OUTPUT ;
    USE SIGNAL ;
    PORT
      LAYER M3 ;
        RECT  22.608 0 22.626 0.038 ;
    END
  END o[353]
  PIN o[354]
    DIRECTION OUTPUT ;
    USE SIGNAL ;
    PORT
      LAYER M3 ;
        RECT  39.816 0 39.834 0.038 ;
    END
  END o[354]
  PIN o[355]
    DIRECTION OUTPUT ;
    USE SIGNAL ;
    PORT
      LAYER M5 ;
        RECT  39.888 0 39.912 0.192 ;
    END
  END o[355]
  PIN o[356]
    DIRECTION OUTPUT ;
    USE SIGNAL ;
    PORT
      LAYER M3 ;
        RECT  39.96 0 39.978 0.038 ;
    END
  END o[356]
  PIN o[357]
    DIRECTION OUTPUT ;
    USE SIGNAL ;
    PORT
      LAYER M5 ;
        RECT  40.08 0 40.104 0.192 ;
    END
  END o[357]
  PIN o[358]
    DIRECTION OUTPUT ;
    USE SIGNAL ;
    PORT
      LAYER M3 ;
        RECT  40.104 0 40.122 0.038 ;
    END
  END o[358]
  PIN o[359]
    DIRECTION OUTPUT ;
    USE SIGNAL ;
    PORT
      LAYER M5 ;
        RECT  40.176 0 40.2 0.192 ;
    END
  END o[359]
  PIN o[35]
    DIRECTION OUTPUT ;
    USE SIGNAL ;
    PORT
      LAYER M3 ;
        RECT  34.416 0 34.434 0.038 ;
    END
  END o[35]
  PIN o[360]
    DIRECTION OUTPUT ;
    USE SIGNAL ;
    PORT
      LAYER M3 ;
        RECT  40.248 0 40.266 0.038 ;
    END
  END o[360]
  PIN o[361]
    DIRECTION OUTPUT ;
    USE SIGNAL ;
    PORT
      LAYER M5 ;
        RECT  40.368 0 40.392 0.192 ;
    END
  END o[361]
  PIN o[362]
    DIRECTION OUTPUT ;
    USE SIGNAL ;
    PORT
      LAYER M3 ;
        RECT  40.464 0 40.482 0.038 ;
    END
  END o[362]
  PIN o[363]
    DIRECTION OUTPUT ;
    USE SIGNAL ;
    PORT
      LAYER M5 ;
        RECT  40.464 0 40.488 0.192 ;
    END
  END o[363]
  PIN o[364]
    DIRECTION OUTPUT ;
    USE SIGNAL ;
    PORT
      LAYER M3 ;
        RECT  40.608 0 40.626 0.038 ;
    END
  END o[364]
  PIN o[365]
    DIRECTION OUTPUT ;
    USE SIGNAL ;
    PORT
      LAYER M5 ;
        RECT  40.656 0 40.68 0.192 ;
    END
  END o[365]
  PIN o[366]
    DIRECTION OUTPUT ;
    USE SIGNAL ;
    PORT
      LAYER M3 ;
        RECT  40.752 0 40.77 0.038 ;
    END
  END o[366]
  PIN o[367]
    DIRECTION OUTPUT ;
    USE SIGNAL ;
    PORT
      LAYER M5 ;
        RECT  40.848 0 40.872 0.192 ;
    END
  END o[367]
  PIN o[368]
    DIRECTION OUTPUT ;
    USE SIGNAL ;
    PORT
      LAYER M5 ;
        RECT  40.944 0 40.968 0.192 ;
    END
  END o[368]
  PIN o[369]
    DIRECTION OUTPUT ;
    USE SIGNAL ;
    PORT
      LAYER M5 ;
        RECT  22.8 0 22.824 0.192 ;
    END
  END o[369]
  PIN o[36]
    DIRECTION OUTPUT ;
    USE SIGNAL ;
    PORT
      LAYER M5 ;
        RECT  34.464 0 34.488 0.192 ;
    END
  END o[36]
  PIN o[370]
    DIRECTION OUTPUT ;
    USE SIGNAL ;
    PORT
      LAYER M3 ;
        RECT  22.68 0 22.698 0.038 ;
    END
  END o[370]
  PIN o[371]
    DIRECTION OUTPUT ;
    USE SIGNAL ;
    PORT
      LAYER M5 ;
        RECT  22.896 0 22.92 0.192 ;
    END
  END o[371]
  PIN o[372]
    DIRECTION OUTPUT ;
    USE SIGNAL ;
    PORT
      LAYER M3 ;
        RECT  22.752 0 22.77 0.038 ;
    END
  END o[372]
  PIN o[373]
    DIRECTION OUTPUT ;
    USE SIGNAL ;
    PORT
      LAYER M5 ;
        RECT  22.992 0 23.016 0.192 ;
    END
  END o[373]
  PIN o[374]
    DIRECTION OUTPUT ;
    USE SIGNAL ;
    PORT
      LAYER M3 ;
        RECT  22.968 0 22.986 0.038 ;
    END
  END o[374]
  PIN o[375]
    DIRECTION OUTPUT ;
    USE SIGNAL ;
    PORT
      LAYER M5 ;
        RECT  23.088 0 23.112 0.192 ;
    END
  END o[375]
  PIN o[376]
    DIRECTION OUTPUT ;
    USE SIGNAL ;
    PORT
      LAYER M3 ;
        RECT  23.112 0 23.13 0.038 ;
    END
  END o[376]
  PIN o[377]
    DIRECTION OUTPUT ;
    USE SIGNAL ;
    PORT
      LAYER M5 ;
        RECT  23.184 0 23.208 0.192 ;
    END
  END o[377]
  PIN o[378]
    DIRECTION OUTPUT ;
    USE SIGNAL ;
    PORT
      LAYER M3 ;
        RECT  23.256 0 23.274 0.038 ;
    END
  END o[378]
  PIN o[379]
    DIRECTION OUTPUT ;
    USE SIGNAL ;
    PORT
      LAYER M5 ;
        RECT  23.376 0 23.4 0.192 ;
    END
  END o[379]
  PIN o[37]
    DIRECTION OUTPUT ;
    USE SIGNAL ;
    PORT
      LAYER M3 ;
        RECT  34.56 0 34.578 0.038 ;
    END
  END o[37]
  PIN o[380]
    DIRECTION OUTPUT ;
    USE SIGNAL ;
    PORT
      LAYER M3 ;
        RECT  23.4 0 23.418 0.038 ;
    END
  END o[380]
  PIN o[381]
    DIRECTION OUTPUT ;
    USE SIGNAL ;
    PORT
      LAYER M5 ;
        RECT  23.472 0 23.496 0.192 ;
    END
  END o[381]
  PIN o[382]
    DIRECTION OUTPUT ;
    USE SIGNAL ;
    PORT
      LAYER M3 ;
        RECT  23.544 0 23.562 0.038 ;
    END
  END o[382]
  PIN o[383]
    DIRECTION OUTPUT ;
    USE SIGNAL ;
    PORT
      LAYER M5 ;
        RECT  23.664 0 23.688 0.192 ;
    END
  END o[383]
  PIN o[384]
    DIRECTION OUTPUT ;
    USE SIGNAL ;
    PORT
      LAYER M3 ;
        RECT  23.76 0 23.778 0.038 ;
    END
  END o[384]
  PIN o[385]
    DIRECTION OUTPUT ;
    USE SIGNAL ;
    PORT
      LAYER M5 ;
        RECT  23.856 0 23.88 0.192 ;
    END
  END o[385]
  PIN o[386]
    DIRECTION OUTPUT ;
    USE SIGNAL ;
    PORT
      LAYER M3 ;
        RECT  23.904 0 23.922 0.038 ;
    END
  END o[386]
  PIN o[387]
    DIRECTION OUTPUT ;
    USE SIGNAL ;
    PORT
      LAYER M5 ;
        RECT  23.952 0 23.976 0.192 ;
    END
  END o[387]
  PIN o[388]
    DIRECTION OUTPUT ;
    USE SIGNAL ;
    PORT
      LAYER M3 ;
        RECT  24.048 0 24.066 0.038 ;
    END
  END o[388]
  PIN o[389]
    DIRECTION OUTPUT ;
    USE SIGNAL ;
    PORT
      LAYER M5 ;
        RECT  24.144 0 24.168 0.192 ;
    END
  END o[389]
  PIN o[38]
    DIRECTION OUTPUT ;
    USE SIGNAL ;
    PORT
      LAYER M5 ;
        RECT  34.656 0 34.68 0.192 ;
    END
  END o[38]
  PIN o[390]
    DIRECTION OUTPUT ;
    USE SIGNAL ;
    PORT
      LAYER M3 ;
        RECT  24.192 0 24.21 0.038 ;
    END
  END o[390]
  PIN o[391]
    DIRECTION OUTPUT ;
    USE SIGNAL ;
    PORT
      LAYER M5 ;
        RECT  24.336 0 24.36 0.192 ;
    END
  END o[391]
  PIN o[392]
    DIRECTION OUTPUT ;
    USE SIGNAL ;
    PORT
      LAYER M3 ;
        RECT  24.408 0 24.426 0.038 ;
    END
  END o[392]
  PIN o[393]
    DIRECTION OUTPUT ;
    USE SIGNAL ;
    PORT
      LAYER M5 ;
        RECT  24.432 0 24.456 0.192 ;
    END
  END o[393]
  PIN o[394]
    DIRECTION OUTPUT ;
    USE SIGNAL ;
    PORT
      LAYER M3 ;
        RECT  24.552 0 24.57 0.038 ;
    END
  END o[394]
  PIN o[395]
    DIRECTION OUTPUT ;
    USE SIGNAL ;
    PORT
      LAYER M5 ;
        RECT  24.624 0 24.648 0.192 ;
    END
  END o[395]
  PIN o[396]
    DIRECTION OUTPUT ;
    USE SIGNAL ;
    PORT
      LAYER M3 ;
        RECT  24.696 0 24.714 0.038 ;
    END
  END o[396]
  PIN o[397]
    DIRECTION OUTPUT ;
    USE SIGNAL ;
    PORT
      LAYER M5 ;
        RECT  24.816 0 24.84 0.192 ;
    END
  END o[397]
  PIN o[398]
    DIRECTION OUTPUT ;
    USE SIGNAL ;
    PORT
      LAYER M3 ;
        RECT  24.84 0 24.858 0.038 ;
    END
  END o[398]
  PIN o[399]
    DIRECTION OUTPUT ;
    USE SIGNAL ;
    PORT
      LAYER M5 ;
        RECT  24.912 0 24.936 0.192 ;
    END
  END o[399]
  PIN o[39]
    DIRECTION OUTPUT ;
    USE SIGNAL ;
    PORT
      LAYER M3 ;
        RECT  34.704 0 34.722 0.038 ;
    END
  END o[39]
  PIN o[3]
    DIRECTION OUTPUT ;
    USE SIGNAL ;
    PORT
      LAYER M3 ;
        RECT  31.68 0 31.698 0.038 ;
    END
  END o[3]
  PIN o[400]
    DIRECTION OUTPUT ;
    USE SIGNAL ;
    PORT
      LAYER M3 ;
        RECT  24.984 0 25.002 0.038 ;
    END
  END o[400]
  PIN o[401]
    DIRECTION OUTPUT ;
    USE SIGNAL ;
    PORT
      LAYER M5 ;
        RECT  25.104 0 25.128 0.192 ;
    END
  END o[401]
  PIN o[402]
    DIRECTION OUTPUT ;
    USE SIGNAL ;
    PORT
      LAYER M3 ;
        RECT  25.2 0 25.218 0.038 ;
    END
  END o[402]
  PIN o[403]
    DIRECTION OUTPUT ;
    USE SIGNAL ;
    PORT
      LAYER M5 ;
        RECT  25.2 0 25.224 0.192 ;
    END
  END o[403]
  PIN o[404]
    DIRECTION OUTPUT ;
    USE SIGNAL ;
    PORT
      LAYER M3 ;
        RECT  25.344 0 25.362 0.038 ;
    END
  END o[404]
  PIN o[405]
    DIRECTION OUTPUT ;
    USE SIGNAL ;
    PORT
      LAYER M5 ;
        RECT  25.392 0 25.416 0.192 ;
    END
  END o[405]
  PIN o[406]
    DIRECTION OUTPUT ;
    USE SIGNAL ;
    PORT
      LAYER M3 ;
        RECT  25.488 0 25.506 0.038 ;
    END
  END o[406]
  PIN o[407]
    DIRECTION OUTPUT ;
    USE SIGNAL ;
    PORT
      LAYER M5 ;
        RECT  25.584 0 25.608 0.192 ;
    END
  END o[407]
  PIN o[408]
    DIRECTION OUTPUT ;
    USE SIGNAL ;
    PORT
      LAYER M3 ;
        RECT  25.632 0 25.65 0.038 ;
    END
  END o[408]
  PIN o[409]
    DIRECTION OUTPUT ;
    USE SIGNAL ;
    PORT
      LAYER M5 ;
        RECT  25.68 0 25.704 0.192 ;
    END
  END o[409]
  PIN o[40]
    DIRECTION OUTPUT ;
    USE SIGNAL ;
    PORT
      LAYER M5 ;
        RECT  34.752 0 34.776 0.192 ;
    END
  END o[40]
  PIN o[410]
    DIRECTION OUTPUT ;
    USE SIGNAL ;
    PORT
      LAYER M3 ;
        RECT  25.776 0 25.794 0.038 ;
    END
  END o[410]
  PIN o[411]
    DIRECTION OUTPUT ;
    USE SIGNAL ;
    PORT
      LAYER M5 ;
        RECT  25.872 0 25.896 0.192 ;
    END
  END o[411]
  PIN o[412]
    DIRECTION OUTPUT ;
    USE SIGNAL ;
    PORT
      LAYER M3 ;
        RECT  25.992 0 26.01 0.038 ;
    END
  END o[412]
  PIN o[413]
    DIRECTION OUTPUT ;
    USE SIGNAL ;
    PORT
      LAYER M5 ;
        RECT  26.064 0 26.088 0.192 ;
    END
  END o[413]
  PIN o[414]
    DIRECTION OUTPUT ;
    USE SIGNAL ;
    PORT
      LAYER M3 ;
        RECT  26.136 0 26.154 0.038 ;
    END
  END o[414]
  PIN o[415]
    DIRECTION OUTPUT ;
    USE SIGNAL ;
    PORT
      LAYER M5 ;
        RECT  26.16 0 26.184 0.192 ;
    END
  END o[415]
  PIN o[416]
    DIRECTION OUTPUT ;
    USE SIGNAL ;
    PORT
      LAYER M3 ;
        RECT  26.28 0 26.298 0.038 ;
    END
  END o[416]
  PIN o[417]
    DIRECTION OUTPUT ;
    USE SIGNAL ;
    PORT
      LAYER M5 ;
        RECT  26.352 0 26.376 0.192 ;
    END
  END o[417]
  PIN o[418]
    DIRECTION OUTPUT ;
    USE SIGNAL ;
    PORT
      LAYER M3 ;
        RECT  26.424 0 26.442 0.038 ;
    END
  END o[418]
  PIN o[419]
    DIRECTION OUTPUT ;
    USE SIGNAL ;
    PORT
      LAYER M5 ;
        RECT  26.544 0 26.568 0.192 ;
    END
  END o[419]
  PIN o[41]
    DIRECTION OUTPUT ;
    USE SIGNAL ;
    PORT
      LAYER M3 ;
        RECT  34.848 0 34.866 0.038 ;
    END
  END o[41]
  PIN o[420]
    DIRECTION OUTPUT ;
    USE SIGNAL ;
    PORT
      LAYER M3 ;
        RECT  26.568 0 26.586 0.038 ;
    END
  END o[420]
  PIN o[421]
    DIRECTION OUTPUT ;
    USE SIGNAL ;
    PORT
      LAYER M5 ;
        RECT  26.64 0 26.664 0.192 ;
    END
  END o[421]
  PIN o[422]
    DIRECTION OUTPUT ;
    USE SIGNAL ;
    PORT
      LAYER M3 ;
        RECT  26.784 0 26.802 0.038 ;
    END
  END o[422]
  PIN o[423]
    DIRECTION OUTPUT ;
    USE SIGNAL ;
    PORT
      LAYER M5 ;
        RECT  26.832 0 26.856 0.192 ;
    END
  END o[423]
  PIN o[424]
    DIRECTION OUTPUT ;
    USE SIGNAL ;
    PORT
      LAYER M3 ;
        RECT  26.928 0 26.946 0.038 ;
    END
  END o[424]
  PIN o[425]
    DIRECTION OUTPUT ;
    USE SIGNAL ;
    PORT
      LAYER M5 ;
        RECT  27.024 0 27.048 0.192 ;
    END
  END o[425]
  PIN o[426]
    DIRECTION OUTPUT ;
    USE SIGNAL ;
    PORT
      LAYER M3 ;
        RECT  27.072 0 27.09 0.038 ;
    END
  END o[426]
  PIN o[427]
    DIRECTION OUTPUT ;
    USE SIGNAL ;
    PORT
      LAYER M5 ;
        RECT  27.12 0 27.144 0.192 ;
    END
  END o[427]
  PIN o[428]
    DIRECTION OUTPUT ;
    USE SIGNAL ;
    PORT
      LAYER M3 ;
        RECT  27.144 0 27.162 0.038 ;
    END
  END o[428]
  PIN o[429]
    DIRECTION OUTPUT ;
    USE SIGNAL ;
    PORT
      LAYER M5 ;
        RECT  27.744 0 27.768 0.192 ;
    END
  END o[429]
  PIN o[42]
    DIRECTION OUTPUT ;
    USE SIGNAL ;
    PORT
      LAYER M3 ;
        RECT  35.064 0 35.082 0.038 ;
    END
  END o[42]
  PIN o[430]
    DIRECTION OUTPUT ;
    USE SIGNAL ;
    PORT
      LAYER M3 ;
        RECT  27.792 0 27.81 0.038 ;
    END
  END o[430]
  PIN o[431]
    DIRECTION OUTPUT ;
    USE SIGNAL ;
    PORT
      LAYER M5 ;
        RECT  27.84 0 27.864 0.192 ;
    END
  END o[431]
  PIN o[432]
    DIRECTION OUTPUT ;
    USE SIGNAL ;
    PORT
      LAYER M3 ;
        RECT  27.864 0 27.882 0.038 ;
    END
  END o[432]
  PIN o[433]
    DIRECTION OUTPUT ;
    USE SIGNAL ;
    PORT
      LAYER M5 ;
        RECT  27.936 0 27.96 0.192 ;
    END
  END o[433]
  PIN o[434]
    DIRECTION OUTPUT ;
    USE SIGNAL ;
    PORT
      LAYER M3 ;
        RECT  27.936 0 27.954 0.038 ;
    END
  END o[434]
  PIN o[435]
    DIRECTION OUTPUT ;
    USE SIGNAL ;
    PORT
      LAYER M5 ;
        RECT  28.032 0 28.056 0.192 ;
    END
  END o[435]
  PIN o[436]
    DIRECTION OUTPUT ;
    USE SIGNAL ;
    PORT
      LAYER M3 ;
        RECT  28.008 0 28.026 0.038 ;
    END
  END o[436]
  PIN o[437]
    DIRECTION OUTPUT ;
    USE SIGNAL ;
    PORT
      LAYER M5 ;
        RECT  28.128 0 28.152 0.192 ;
    END
  END o[437]
  PIN o[438]
    DIRECTION OUTPUT ;
    USE SIGNAL ;
    PORT
      LAYER M3 ;
        RECT  28.08 0 28.098 0.038 ;
    END
  END o[438]
  PIN o[439]
    DIRECTION OUTPUT ;
    USE SIGNAL ;
    PORT
      LAYER M5 ;
        RECT  28.224 0 28.248 0.192 ;
    END
  END o[439]
  PIN o[43]
    DIRECTION OUTPUT ;
    USE SIGNAL ;
    PORT
      LAYER M5 ;
        RECT  35.136 0 35.16 0.192 ;
    END
  END o[43]
  PIN o[440]
    DIRECTION OUTPUT ;
    USE SIGNAL ;
    PORT
      LAYER M3 ;
        RECT  28.224 0 28.242 0.038 ;
    END
  END o[440]
  PIN o[441]
    DIRECTION OUTPUT ;
    USE SIGNAL ;
    PORT
      LAYER M5 ;
        RECT  28.32 0 28.344 0.192 ;
    END
  END o[441]
  PIN o[442]
    DIRECTION OUTPUT ;
    USE SIGNAL ;
    PORT
      LAYER M3 ;
        RECT  28.368 0 28.386 0.038 ;
    END
  END o[442]
  PIN o[443]
    DIRECTION OUTPUT ;
    USE SIGNAL ;
    PORT
      LAYER M5 ;
        RECT  28.416 0 28.44 0.192 ;
    END
  END o[443]
  PIN o[444]
    DIRECTION OUTPUT ;
    USE SIGNAL ;
    PORT
      LAYER M3 ;
        RECT  28.512 0 28.53 0.038 ;
    END
  END o[444]
  PIN o[445]
    DIRECTION OUTPUT ;
    USE SIGNAL ;
    PORT
      LAYER M5 ;
        RECT  28.608 0 28.632 0.192 ;
    END
  END o[445]
  PIN o[446]
    DIRECTION OUTPUT ;
    USE SIGNAL ;
    PORT
      LAYER M3 ;
        RECT  28.656 0 28.674 0.038 ;
    END
  END o[446]
  PIN o[447]
    DIRECTION OUTPUT ;
    USE SIGNAL ;
    PORT
      LAYER M5 ;
        RECT  28.704 0 28.728 0.192 ;
    END
  END o[447]
  PIN o[448]
    DIRECTION OUTPUT ;
    USE SIGNAL ;
    PORT
      LAYER M3 ;
        RECT  28.8 0 28.818 0.038 ;
    END
  END o[448]
  PIN o[449]
    DIRECTION OUTPUT ;
    USE SIGNAL ;
    PORT
      LAYER M5 ;
        RECT  28.896 0 28.92 0.192 ;
    END
  END o[449]
  PIN o[44]
    DIRECTION OUTPUT ;
    USE SIGNAL ;
    PORT
      LAYER M3 ;
        RECT  35.208 0 35.226 0.038 ;
    END
  END o[44]
  PIN o[450]
    DIRECTION OUTPUT ;
    USE SIGNAL ;
    PORT
      LAYER M3 ;
        RECT  29.016 0 29.034 0.038 ;
    END
  END o[450]
  PIN o[451]
    DIRECTION OUTPUT ;
    USE SIGNAL ;
    PORT
      LAYER M5 ;
        RECT  29.088 0 29.112 0.192 ;
    END
  END o[451]
  PIN o[452]
    DIRECTION OUTPUT ;
    USE SIGNAL ;
    PORT
      LAYER M3 ;
        RECT  29.16 0 29.178 0.038 ;
    END
  END o[452]
  PIN o[453]
    DIRECTION OUTPUT ;
    USE SIGNAL ;
    PORT
      LAYER M5 ;
        RECT  29.184 0 29.208 0.192 ;
    END
  END o[453]
  PIN o[454]
    DIRECTION OUTPUT ;
    USE SIGNAL ;
    PORT
      LAYER M3 ;
        RECT  29.304 0 29.322 0.038 ;
    END
  END o[454]
  PIN o[455]
    DIRECTION OUTPUT ;
    USE SIGNAL ;
    PORT
      LAYER M5 ;
        RECT  29.376 0 29.4 0.192 ;
    END
  END o[455]
  PIN o[456]
    DIRECTION OUTPUT ;
    USE SIGNAL ;
    PORT
      LAYER M3 ;
        RECT  29.448 0 29.466 0.038 ;
    END
  END o[456]
  PIN o[457]
    DIRECTION OUTPUT ;
    USE SIGNAL ;
    PORT
      LAYER M5 ;
        RECT  29.568 0 29.592 0.192 ;
    END
  END o[457]
  PIN o[458]
    DIRECTION OUTPUT ;
    USE SIGNAL ;
    PORT
      LAYER M3 ;
        RECT  29.592 0 29.61 0.038 ;
    END
  END o[458]
  PIN o[459]
    DIRECTION OUTPUT ;
    USE SIGNAL ;
    PORT
      LAYER M5 ;
        RECT  29.664 0 29.688 0.192 ;
    END
  END o[459]
  PIN o[45]
    DIRECTION OUTPUT ;
    USE SIGNAL ;
    PORT
      LAYER M5 ;
        RECT  35.232 0 35.256 0.192 ;
    END
  END o[45]
  PIN o[460]
    DIRECTION OUTPUT ;
    USE SIGNAL ;
    PORT
      LAYER M3 ;
        RECT  29.808 0 29.826 0.038 ;
    END
  END o[460]
  PIN o[461]
    DIRECTION OUTPUT ;
    USE SIGNAL ;
    PORT
      LAYER M5 ;
        RECT  29.856 0 29.88 0.192 ;
    END
  END o[461]
  PIN o[462]
    DIRECTION OUTPUT ;
    USE SIGNAL ;
    PORT
      LAYER M3 ;
        RECT  29.952 0 29.97 0.038 ;
    END
  END o[462]
  PIN o[463]
    DIRECTION OUTPUT ;
    USE SIGNAL ;
    PORT
      LAYER M5 ;
        RECT  30.048 0 30.072 0.192 ;
    END
  END o[463]
  PIN o[464]
    DIRECTION OUTPUT ;
    USE SIGNAL ;
    PORT
      LAYER M3 ;
        RECT  30.096 0 30.114 0.038 ;
    END
  END o[464]
  PIN o[465]
    DIRECTION OUTPUT ;
    USE SIGNAL ;
    PORT
      LAYER M5 ;
        RECT  30.144 0 30.168 0.192 ;
    END
  END o[465]
  PIN o[466]
    DIRECTION OUTPUT ;
    USE SIGNAL ;
    PORT
      LAYER M3 ;
        RECT  30.24 0 30.258 0.038 ;
    END
  END o[466]
  PIN o[467]
    DIRECTION OUTPUT ;
    USE SIGNAL ;
    PORT
      LAYER M5 ;
        RECT  30.336 0 30.36 0.192 ;
    END
  END o[467]
  PIN o[468]
    DIRECTION OUTPUT ;
    USE SIGNAL ;
    PORT
      LAYER M3 ;
        RECT  30.384 0 30.402 0.038 ;
    END
  END o[468]
  PIN o[469]
    DIRECTION OUTPUT ;
    USE SIGNAL ;
    PORT
      LAYER M5 ;
        RECT  30.528 0 30.552 0.192 ;
    END
  END o[469]
  PIN o[46]
    DIRECTION OUTPUT ;
    USE SIGNAL ;
    PORT
      LAYER M3 ;
        RECT  35.352 0 35.37 0.038 ;
    END
  END o[46]
  PIN o[470]
    DIRECTION OUTPUT ;
    USE SIGNAL ;
    PORT
      LAYER M3 ;
        RECT  30.6 0 30.618 0.038 ;
    END
  END o[470]
  PIN o[471]
    DIRECTION OUTPUT ;
    USE SIGNAL ;
    PORT
      LAYER M5 ;
        RECT  30.624 0 30.648 0.192 ;
    END
  END o[471]
  PIN o[472]
    DIRECTION OUTPUT ;
    USE SIGNAL ;
    PORT
      LAYER M3 ;
        RECT  30.744 0 30.762 0.038 ;
    END
  END o[472]
  PIN o[473]
    DIRECTION OUTPUT ;
    USE SIGNAL ;
    PORT
      LAYER M5 ;
        RECT  30.816 0 30.84 0.192 ;
    END
  END o[473]
  PIN o[474]
    DIRECTION OUTPUT ;
    USE SIGNAL ;
    PORT
      LAYER M3 ;
        RECT  30.888 0 30.906 0.038 ;
    END
  END o[474]
  PIN o[475]
    DIRECTION OUTPUT ;
    USE SIGNAL ;
    PORT
      LAYER M5 ;
        RECT  31.008 0 31.032 0.192 ;
    END
  END o[475]
  PIN o[476]
    DIRECTION OUTPUT ;
    USE SIGNAL ;
    PORT
      LAYER M3 ;
        RECT  31.032 0 31.05 0.038 ;
    END
  END o[476]
  PIN o[477]
    DIRECTION OUTPUT ;
    USE SIGNAL ;
    PORT
      LAYER M5 ;
        RECT  31.104 0 31.128 0.192 ;
    END
  END o[477]
  PIN o[478]
    DIRECTION OUTPUT ;
    USE SIGNAL ;
    PORT
      LAYER M3 ;
        RECT  31.176 0 31.194 0.038 ;
    END
  END o[478]
  PIN o[479]
    DIRECTION OUTPUT ;
    USE SIGNAL ;
    PORT
      LAYER M5 ;
        RECT  31.296 0 31.32 0.192 ;
    END
  END o[479]
  PIN o[47]
    DIRECTION OUTPUT ;
    USE SIGNAL ;
    PORT
      LAYER M5 ;
        RECT  35.424 0 35.448 0.192 ;
    END
  END o[47]
  PIN o[480]
    DIRECTION OUTPUT ;
    USE SIGNAL ;
    PORT
      LAYER M3 ;
        RECT  31.392 0 31.41 0.038 ;
    END
  END o[480]
  PIN o[48]
    DIRECTION OUTPUT ;
    USE SIGNAL ;
    PORT
      LAYER M3 ;
        RECT  35.496 0 35.514 0.038 ;
    END
  END o[48]
  PIN o[49]
    DIRECTION OUTPUT ;
    USE SIGNAL ;
    PORT
      LAYER M5 ;
        RECT  35.616 0 35.64 0.192 ;
    END
  END o[49]
  PIN o[4]
    DIRECTION OUTPUT ;
    USE SIGNAL ;
    PORT
      LAYER M5 ;
        RECT  31.776 0 31.8 0.192 ;
    END
  END o[4]
  PIN o[50]
    DIRECTION OUTPUT ;
    USE SIGNAL ;
    PORT
      LAYER M3 ;
        RECT  35.64 0 35.658 0.038 ;
    END
  END o[50]
  PIN o[51]
    DIRECTION OUTPUT ;
    USE SIGNAL ;
    PORT
      LAYER M5 ;
        RECT  35.712 0 35.736 0.192 ;
    END
  END o[51]
  PIN o[52]
    DIRECTION OUTPUT ;
    USE SIGNAL ;
    PORT
      LAYER M3 ;
        RECT  35.856 0 35.874 0.038 ;
    END
  END o[52]
  PIN o[53]
    DIRECTION OUTPUT ;
    USE SIGNAL ;
    PORT
      LAYER M5 ;
        RECT  35.904 0 35.928 0.192 ;
    END
  END o[53]
  PIN o[54]
    DIRECTION OUTPUT ;
    USE SIGNAL ;
    PORT
      LAYER M3 ;
        RECT  36 0 36.018 0.038 ;
    END
  END o[54]
  PIN o[55]
    DIRECTION OUTPUT ;
    USE SIGNAL ;
    PORT
      LAYER M5 ;
        RECT  36.096 0 36.12 0.192 ;
    END
  END o[55]
  PIN o[56]
    DIRECTION OUTPUT ;
    USE SIGNAL ;
    PORT
      LAYER M5 ;
        RECT  36.192 0 36.216 0.192 ;
    END
  END o[56]
  PIN o[57]
    DIRECTION OUTPUT ;
    USE SIGNAL ;
    PORT
      LAYER M3 ;
        RECT  36.288 0 36.306 0.038 ;
    END
  END o[57]
  PIN o[58]
    DIRECTION OUTPUT ;
    USE SIGNAL ;
    PORT
      LAYER M5 ;
        RECT  36.384 0 36.408 0.192 ;
    END
  END o[58]
  PIN o[59]
    DIRECTION OUTPUT ;
    USE SIGNAL ;
    PORT
      LAYER M3 ;
        RECT  36.432 0 36.45 0.038 ;
    END
  END o[59]
  PIN o[5]
    DIRECTION OUTPUT ;
    USE SIGNAL ;
    PORT
      LAYER M3 ;
        RECT  31.824 0 31.842 0.038 ;
    END
  END o[5]
  PIN o[60]
    DIRECTION OUTPUT ;
    USE SIGNAL ;
    PORT
      LAYER M5 ;
        RECT  36.576 0 36.6 0.192 ;
    END
  END o[60]
  PIN o[61]
    DIRECTION OUTPUT ;
    USE SIGNAL ;
    PORT
      LAYER M3 ;
        RECT  36.648 0 36.666 0.038 ;
    END
  END o[61]
  PIN o[62]
    DIRECTION OUTPUT ;
    USE SIGNAL ;
    PORT
      LAYER M5 ;
        RECT  36.672 0 36.696 0.192 ;
    END
  END o[62]
  PIN o[63]
    DIRECTION OUTPUT ;
    USE SIGNAL ;
    PORT
      LAYER M3 ;
        RECT  36.792 0 36.81 0.038 ;
    END
  END o[63]
  PIN o[64]
    DIRECTION OUTPUT ;
    USE SIGNAL ;
    PORT
      LAYER M5 ;
        RECT  36.864 0 36.888 0.192 ;
    END
  END o[64]
  PIN o[65]
    DIRECTION OUTPUT ;
    USE SIGNAL ;
    PORT
      LAYER M3 ;
        RECT  36.936 0 36.954 0.038 ;
    END
  END o[65]
  PIN o[66]
    DIRECTION OUTPUT ;
    USE SIGNAL ;
    PORT
      LAYER M5 ;
        RECT  37.056 0 37.08 0.192 ;
    END
  END o[66]
  PIN o[67]
    DIRECTION OUTPUT ;
    USE SIGNAL ;
    PORT
      LAYER M3 ;
        RECT  37.08 0 37.098 0.038 ;
    END
  END o[67]
  PIN o[68]
    DIRECTION OUTPUT ;
    USE SIGNAL ;
    PORT
      LAYER M5 ;
        RECT  37.152 0 37.176 0.192 ;
    END
  END o[68]
  PIN o[69]
    DIRECTION OUTPUT ;
    USE SIGNAL ;
    PORT
      LAYER M3 ;
        RECT  37.224 0 37.242 0.038 ;
    END
  END o[69]
  PIN o[6]
    DIRECTION OUTPUT ;
    USE SIGNAL ;
    PORT
      LAYER M5 ;
        RECT  31.968 0 31.992 0.192 ;
    END
  END o[6]
  PIN o[70]
    DIRECTION OUTPUT ;
    USE SIGNAL ;
    PORT
      LAYER M3 ;
        RECT  37.44 0 37.458 0.038 ;
    END
  END o[70]
  PIN o[71]
    DIRECTION OUTPUT ;
    USE SIGNAL ;
    PORT
      LAYER M5 ;
        RECT  37.536 0 37.56 0.192 ;
    END
  END o[71]
  PIN o[72]
    DIRECTION OUTPUT ;
    USE SIGNAL ;
    PORT
      LAYER M3 ;
        RECT  37.584 0 37.602 0.038 ;
    END
  END o[72]
  PIN o[73]
    DIRECTION OUTPUT ;
    USE SIGNAL ;
    PORT
      LAYER M5 ;
        RECT  37.632 0 37.656 0.192 ;
    END
  END o[73]
  PIN o[74]
    DIRECTION OUTPUT ;
    USE SIGNAL ;
    PORT
      LAYER M3 ;
        RECT  37.728 0 37.746 0.038 ;
    END
  END o[74]
  PIN o[75]
    DIRECTION OUTPUT ;
    USE SIGNAL ;
    PORT
      LAYER M5 ;
        RECT  37.824 0 37.848 0.192 ;
    END
  END o[75]
  PIN o[76]
    DIRECTION OUTPUT ;
    USE SIGNAL ;
    PORT
      LAYER M3 ;
        RECT  37.872 0 37.89 0.038 ;
    END
  END o[76]
  PIN o[77]
    DIRECTION OUTPUT ;
    USE SIGNAL ;
    PORT
      LAYER M5 ;
        RECT  37.92 0 37.944 0.192 ;
    END
  END o[77]
  PIN o[78]
    DIRECTION OUTPUT ;
    USE SIGNAL ;
    PORT
      LAYER M3 ;
        RECT  37.944 0 37.962 0.038 ;
    END
  END o[78]
  PIN o[79]
    DIRECTION OUTPUT ;
    USE SIGNAL ;
    PORT
      LAYER M5 ;
        RECT  38.544 0 38.568 0.192 ;
    END
  END o[79]
  PIN o[7]
    DIRECTION OUTPUT ;
    USE SIGNAL ;
    PORT
      LAYER M3 ;
        RECT  32.04 0 32.058 0.038 ;
    END
  END o[7]
  PIN o[80]
    DIRECTION OUTPUT ;
    USE SIGNAL ;
    PORT
      LAYER M3 ;
        RECT  38.592 0 38.61 0.038 ;
    END
  END o[80]
  PIN o[81]
    DIRECTION OUTPUT ;
    USE SIGNAL ;
    PORT
      LAYER M5 ;
        RECT  38.64 0 38.664 0.192 ;
    END
  END o[81]
  PIN o[82]
    DIRECTION OUTPUT ;
    USE SIGNAL ;
    PORT
      LAYER M3 ;
        RECT  38.664 0 38.682 0.038 ;
    END
  END o[82]
  PIN o[83]
    DIRECTION OUTPUT ;
    USE SIGNAL ;
    PORT
      LAYER M5 ;
        RECT  38.736 0 38.76 0.192 ;
    END
  END o[83]
  PIN o[84]
    DIRECTION OUTPUT ;
    USE SIGNAL ;
    PORT
      LAYER M5 ;
        RECT  2.16 0 2.184 0.192 ;
    END
  END o[84]
  PIN o[85]
    DIRECTION OUTPUT ;
    USE SIGNAL ;
    PORT
      LAYER M3 ;
        RECT  2.304 0 2.322 0.038 ;
    END
  END o[85]
  PIN o[86]
    DIRECTION OUTPUT ;
    USE SIGNAL ;
    PORT
      LAYER M5 ;
        RECT  2.352 0 2.376 0.192 ;
    END
  END o[86]
  PIN o[87]
    DIRECTION OUTPUT ;
    USE SIGNAL ;
    PORT
      LAYER M3 ;
        RECT  2.448 0 2.466 0.038 ;
    END
  END o[87]
  PIN o[88]
    DIRECTION OUTPUT ;
    USE SIGNAL ;
    PORT
      LAYER M5 ;
        RECT  2.544 0 2.568 0.192 ;
    END
  END o[88]
  PIN o[89]
    DIRECTION OUTPUT ;
    USE SIGNAL ;
    PORT
      LAYER M3 ;
        RECT  2.592 0 2.61 0.038 ;
    END
  END o[89]
  PIN o[8]
    DIRECTION OUTPUT ;
    USE SIGNAL ;
    PORT
      LAYER M5 ;
        RECT  32.064 0 32.088 0.192 ;
    END
  END o[8]
  PIN o[90]
    DIRECTION OUTPUT ;
    USE SIGNAL ;
    PORT
      LAYER M5 ;
        RECT  2.64 0 2.664 0.192 ;
    END
  END o[90]
  PIN o[91]
    DIRECTION OUTPUT ;
    USE SIGNAL ;
    PORT
      LAYER M3 ;
        RECT  2.736 0 2.754 0.038 ;
    END
  END o[91]
  PIN o[92]
    DIRECTION OUTPUT ;
    USE SIGNAL ;
    PORT
      LAYER M5 ;
        RECT  2.832 0 2.856 0.192 ;
    END
  END o[92]
  PIN o[93]
    DIRECTION OUTPUT ;
    USE SIGNAL ;
    PORT
      LAYER M3 ;
        RECT  2.88 0 2.898 0.038 ;
    END
  END o[93]
  PIN o[94]
    DIRECTION OUTPUT ;
    USE SIGNAL ;
    PORT
      LAYER M5 ;
        RECT  3.024 0 3.048 0.192 ;
    END
  END o[94]
  PIN o[95]
    DIRECTION OUTPUT ;
    USE SIGNAL ;
    PORT
      LAYER M3 ;
        RECT  3.096 0 3.114 0.038 ;
    END
  END o[95]
  PIN o[96]
    DIRECTION OUTPUT ;
    USE SIGNAL ;
    PORT
      LAYER M5 ;
        RECT  3.12 0 3.144 0.192 ;
    END
  END o[96]
  PIN o[97]
    DIRECTION OUTPUT ;
    USE SIGNAL ;
    PORT
      LAYER M3 ;
        RECT  3.24 0 3.258 0.038 ;
    END
  END o[97]
  PIN o[98]
    DIRECTION OUTPUT ;
    USE SIGNAL ;
    PORT
      LAYER M5 ;
        RECT  3.312 0 3.336 0.192 ;
    END
  END o[98]
  PIN o[99]
    DIRECTION OUTPUT ;
    USE SIGNAL ;
    PORT
      LAYER M3 ;
        RECT  3.384 0 3.402 0.038 ;
    END
  END o[99]
  PIN o[9]
    DIRECTION OUTPUT ;
    USE SIGNAL ;
    PORT
      LAYER M3 ;
        RECT  32.184 0 32.202 0.038 ;
    END
  END o[9]
  PIN o_v[0]
    DIRECTION OUTPUT ;
    USE SIGNAL ;
    PORT
      LAYER M5 ;
        RECT  32.544 0 32.568 0.192 ;
    END
  END o_v[0]
  PIN o_v[1]
    DIRECTION OUTPUT ;
    USE SIGNAL ;
    PORT
      LAYER M3 ;
        RECT  33.768 0 33.786 0.038 ;
    END
  END o_v[1]
  PIN o_v[2]
    DIRECTION OUTPUT ;
    USE SIGNAL ;
    PORT
      LAYER M5 ;
        RECT  34.944 0 34.968 0.192 ;
    END
  END o_v[2]
  PIN o_v[3]
    DIRECTION OUTPUT ;
    USE SIGNAL ;
    PORT
      LAYER M3 ;
        RECT  36.144 0 36.162 0.038 ;
    END
  END o_v[3]
  PIN o_v[4]
    DIRECTION OUTPUT ;
    USE SIGNAL ;
    PORT
      LAYER M5 ;
        RECT  37.344 0 37.368 0.192 ;
    END
  END o_v[4]
  PIN o_v[5]
    DIRECTION OUTPUT ;
    USE SIGNAL ;
    PORT
      LAYER M3 ;
        RECT  38.736 0 38.754 0.038 ;
    END
  END o_v[5]
  PIN o_v[6]
    DIRECTION OUTPUT ;
    USE SIGNAL ;
    PORT
      LAYER M5 ;
        RECT  39.696 0 39.72 0.192 ;
    END
  END o_v[6]
  PIN o_v[7]
    DIRECTION OUTPUT ;
    USE SIGNAL ;
    PORT
      LAYER M3 ;
        RECT  40.896 0 40.914 0.038 ;
    END
  END o_v[7]
  PIN rn_o[0]
    DIRECTION OUTPUT ;
    USE SIGNAL ;
    PORT
      LAYER M4 ;
        RECT  43.008 7.536 43.2 7.56 ;
    END
    PORT
      LAYER M4 ;
        RECT  42.973 7.536 43.02 7.56 ;
    END
  END rn_o[0]
  PIN rn_o[1]
    DIRECTION OUTPUT ;
    USE SIGNAL ;
    PORT
      LAYER M4 ;
        RECT  43.008 18.384 43.2 18.408 ;
    END
    PORT
      LAYER M4 ;
        RECT  42.181 18.384 43.02 18.408 ;
    END
  END rn_o[1]
  PIN rni
    DIRECTION INPUT ;
    USE SIGNAL ;
    PORT
      LAYER M4 ;
        RECT  0 18.384 0.192 18.408 ;
    END
    PORT
      LAYER M4 ;
        RECT  0.156 18.384 0.245 18.408 ;
    END
  END rni
  PIN VDD
    DIRECTION INOUT ;
    USE POWER ;
    PORT
      LAYER M5 ;
        RECT  40.392 2.151 40.512 23.769 ;
        RECT  34.992 2.151 35.112 23.769 ;
        RECT  29.592 2.151 29.712 23.769 ;
        RECT  24.192 2.151 24.312 23.769 ;
        RECT  18.792 2.151 18.912 23.769 ;
        RECT  13.392 2.151 13.512 23.769 ;
        RECT  7.992 2.151 8.112 23.769 ;
        RECT  2.592 2.151 2.712 23.769 ;
    END
  END VDD
  PIN VSS
    DIRECTION INOUT ;
    USE GROUND ;
    PORT
      LAYER M5 ;
        RECT  40.2 2.137 40.32 23.783 ;
        RECT  34.8 2.137 34.92 23.783 ;
        RECT  29.4 2.137 29.52 23.783 ;
        RECT  24 2.137 24.12 23.783 ;
        RECT  18.6 2.137 18.72 23.783 ;
        RECT  13.2 2.137 13.32 23.783 ;
        RECT  7.8 2.137 7.92 23.783 ;
        RECT  2.4 2.137 2.52 23.783 ;
    END
  END VSS
  # OT_OBS_CLOSED layer=M5 d_um=1.536 added=117
  OBS
    LAYER RVTN ;
     RECT  2.16 2.16 41.04 2.295 ;
     RECT  2.16 2.565 41.04 2.835 ;
     RECT  2.16 3.105 41.04 3.375 ;
     RECT  2.16 3.645 41.04 3.915 ;
     RECT  2.16 4.185 41.04 4.455 ;
     RECT  2.16 4.725 41.04 4.995 ;
     RECT  2.16 5.265 41.04 5.535 ;
     RECT  2.16 5.805 41.04 6.075 ;
     RECT  2.16 6.345 41.04 6.615 ;
     RECT  2.16 6.885 41.04 7.155 ;
     RECT  2.16 7.425 41.04 7.695 ;
     RECT  2.16 7.965 41.04 8.235 ;
     RECT  2.16 8.505 41.04 8.775 ;
     RECT  2.16 9.045 41.04 9.315 ;
     RECT  2.16 9.585 41.04 9.855 ;
     RECT  2.16 10.125 41.04 10.395 ;
     RECT  2.16 10.665 41.04 10.935 ;
     RECT  2.16 11.205 41.04 11.475 ;
     RECT  2.16 11.745 41.04 12.015 ;
     RECT  2.16 12.285 41.04 12.555 ;
     RECT  2.16 12.825 41.04 13.095 ;
     RECT  2.16 13.365 41.04 13.635 ;
     RECT  2.16 13.905 41.04 14.175 ;
     RECT  2.16 14.445 41.04 14.715 ;
     RECT  2.16 14.985 41.04 15.255 ;
     RECT  2.16 15.525 41.04 15.795 ;
     RECT  2.16 16.065 41.04 16.335 ;
     RECT  2.16 16.605 41.04 16.875 ;
     RECT  2.16 17.145 41.04 17.415 ;
     RECT  2.16 17.685 41.04 17.955 ;
     RECT  2.16 18.225 41.04 18.495 ;
     RECT  2.16 18.765 41.04 19.035 ;
     RECT  2.16 19.305 41.04 19.575 ;
     RECT  2.16 19.845 41.04 20.115 ;
     RECT  2.16 20.385 41.04 20.655 ;
     RECT  2.16 20.925 41.04 21.195 ;
     RECT  2.16 21.465 41.04 21.735 ;
     RECT  2.16 22.005 41.04 22.275 ;
     RECT  2.16 22.545 41.04 22.815 ;
     RECT  2.16 23.085 41.04 23.355 ;
     RECT  2.16 23.625 41.04 23.76 ;
    LAYER RVTP ;
     RECT  2.16 2.295 41.04 2.565 ;
     RECT  2.16 2.835 41.04 3.105 ;
     RECT  2.16 3.375 41.04 3.645 ;
     RECT  2.16 3.915 41.04 4.185 ;
     RECT  2.16 4.455 41.04 4.725 ;
     RECT  2.16 4.995 41.04 5.265 ;
     RECT  2.16 5.535 41.04 5.805 ;
     RECT  2.16 6.075 41.04 6.345 ;
     RECT  2.16 6.615 41.04 6.885 ;
     RECT  2.16 7.155 41.04 7.425 ;
     RECT  2.16 7.695 41.04 7.965 ;
     RECT  2.16 8.235 41.04 8.505 ;
     RECT  2.16 8.775 41.04 9.045 ;
     RECT  2.16 9.315 41.04 9.585 ;
     RECT  2.16 9.855 41.04 10.125 ;
     RECT  2.16 10.395 41.04 10.665 ;
     RECT  2.16 10.935 41.04 11.205 ;
     RECT  2.16 11.475 41.04 11.745 ;
     RECT  2.16 12.015 41.04 12.285 ;
     RECT  2.16 12.555 41.04 12.825 ;
     RECT  2.16 13.095 41.04 13.365 ;
     RECT  2.16 13.635 41.04 13.905 ;
     RECT  2.16 14.175 41.04 14.445 ;
     RECT  2.16 14.715 41.04 14.985 ;
     RECT  2.16 15.255 41.04 15.525 ;
     RECT  2.16 15.795 41.04 16.065 ;
     RECT  2.16 16.335 41.04 16.605 ;
     RECT  2.16 16.875 41.04 17.145 ;
     RECT  2.16 17.415 41.04 17.685 ;
     RECT  2.16 17.955 41.04 18.225 ;
     RECT  2.16 18.495 41.04 18.765 ;
     RECT  2.16 19.035 41.04 19.305 ;
     RECT  2.16 19.575 41.04 19.845 ;
     RECT  2.16 20.115 41.04 20.385 ;
     RECT  2.16 20.655 41.04 20.925 ;
     RECT  2.16 21.195 41.04 21.465 ;
     RECT  2.16 21.735 41.04 22.005 ;
     RECT  2.16 22.275 41.04 22.545 ;
     RECT  2.16 22.815 41.04 23.085 ;
     RECT  2.16 23.355 41.04 23.625 ;
    LAYER M1 ;
     RECT  2.16 2.151 41.04 23.769 ;
    LAYER M2 ;
     RECT  0.211 18.162 2.16 18.18 ;
     RECT  2.16 2.151 2.443 23.769 ;
     RECT  2.371 25.866 2.471 25.884 ;
     RECT  2.443 1.728 3.227 23.769 ;
     RECT  3.227 2.034 4.163 23.769 ;
     RECT  3.811 0.036 4.171 0.054 ;
     RECT  4.171 0.036 4.343 0.126 ;
     RECT  4.343 0.036 4.451 0.054 ;
     RECT  4.163 2.106 5.351 23.769 ;
     RECT  5.359 1.152 5.459 1.17 ;
     RECT  5.467 0.108 5.539 0.126 ;
     RECT  5.539 0.036 5.567 0.126 ;
     RECT  5.567 0.036 5.711 0.054 ;
     RECT  5.351 2.151 6.259 23.769 ;
     RECT  6.259 1.728 6.403 23.769 ;
     RECT  6.403 1.152 6.719 23.769 ;
     RECT  6.719 1.152 7.331 1.242 ;
     RECT  6.691 0.036 7.583 0.054 ;
     RECT  6.719 2.106 7.843 23.769 ;
     RECT  7.843 25.866 7.979 25.884 ;
     RECT  7.331 1.152 8.491 1.17 ;
     RECT  7.843 2.034 8.491 23.769 ;
     RECT  8.491 1.152 8.915 23.769 ;
     RECT  8.915 1.152 8.951 1.17 ;
     RECT  8.599 0.036 9.139 0.054 ;
     RECT  9.139 0.036 9.247 0.126 ;
     RECT  8.915 2.151 10.003 23.769 ;
     RECT  9.247 0.036 10.175 0.198 ;
     RECT  10.175 0.036 10.247 0.126 ;
     RECT  10.003 1.728 10.391 23.769 ;
     RECT  10.247 0.036 10.607 0.09 ;
     RECT  10.543 1.152 10.823 1.242 ;
     RECT  10.607 0.036 11.623 0.054 ;
     RECT  11.623 0.036 11.875 0.198 ;
     RECT  11.875 0.036 12.047 0.324 ;
     RECT  12.047 0.036 12.227 0.198 ;
     RECT  12.379 25.182 12.479 25.2 ;
     RECT  10.823 1.152 12.595 1.17 ;
     RECT  10.391 2.151 12.595 23.769 ;
     RECT  12.595 1.152 12.947 23.769 ;
     RECT  12.947 1.728 13.019 23.769 ;
     RECT  13.019 1.8 13.091 23.769 ;
     RECT  13.091 2.106 13.243 23.769 ;
     RECT  12.227 0.036 13.387 0.054 ;
     RECT  13.243 2.106 13.667 23.85 ;
     RECT  13.667 2.106 13.775 23.769 ;
     RECT  13.387 0.036 13.783 0.126 ;
     RECT  14.035 25.686 14.171 25.704 ;
     RECT  13.783 0.036 14.207 0.198 ;
     RECT  14.207 0.036 14.675 0.054 ;
     RECT  13.775 2.151 14.971 23.769 ;
     RECT  14.971 1.728 15.179 23.769 ;
     RECT  15.179 2.034 16.267 23.769 ;
     RECT  16.267 1.728 16.367 23.769 ;
     RECT  15.475 0.036 17.131 0.054 ;
     RECT  16.367 2.151 17.131 23.769 ;
     RECT  17.131 2.151 17.203 23.814 ;
     RECT  17.203 2.151 17.303 23.886 ;
     RECT  17.347 25.866 17.447 25.884 ;
     RECT  17.131 0.036 17.483 0.126 ;
     RECT  17.483 0.036 18.319 0.054 ;
     RECT  17.167 25.056 18.427 25.074 ;
     RECT  18.319 0.036 18.455 0.504 ;
     RECT  18.427 24.606 18.671 25.074 ;
     RECT  18.671 25.056 18.815 25.074 ;
     RECT  18.455 0.036 19.175 0.126 ;
     RECT  17.303 2.151 19.939 23.769 ;
     RECT  19.579 25.056 20.435 25.074 ;
     RECT  19.939 1.728 20.471 23.769 ;
     RECT  19.175 0.036 20.731 0.054 ;
     RECT  20.731 0.036 20.831 0.126 ;
     RECT  21.847 1.152 21.919 1.17 ;
     RECT  21.919 1.152 22.055 1.242 ;
     RECT  22.055 1.224 22.163 1.242 ;
     RECT  20.471 2.106 22.315 23.769 ;
     RECT  22.315 1.728 22.559 23.769 ;
     RECT  20.831 0.036 22.675 0.054 ;
     RECT  22.559 2.106 22.819 23.769 ;
     RECT  22.675 0.036 23.279 0.126 ;
     RECT  22.819 2.106 23.279 23.814 ;
     RECT  23.279 2.106 23.395 23.769 ;
     RECT  23.395 1.728 23.711 23.769 ;
     RECT  23.711 2.106 24.043 23.769 ;
     RECT  24.043 2.106 24.187 23.85 ;
     RECT  24.187 2.106 24.287 23.994 ;
     RECT  24.287 2.106 24.359 23.769 ;
     RECT  24.547 1.224 24.763 1.242 ;
     RECT  23.279 0.036 24.835 0.054 ;
     RECT  24.763 1.152 24.863 1.242 ;
     RECT  24.835 0.036 25.007 0.126 ;
     RECT  24.863 1.224 25.007 1.242 ;
     RECT  25.007 0.036 25.331 0.054 ;
     RECT  24.359 2.151 26.563 23.769 ;
     RECT  26.563 1.728 26.735 23.769 ;
     RECT  26.059 0.036 28.003 0.054 ;
     RECT  28.003 0.036 28.075 0.126 ;
     RECT  28.075 0.036 28.219 0.162 ;
     RECT  28.219 0.036 28.391 0.198 ;
     RECT  26.735 2.151 28.435 23.769 ;
     RECT  28.391 0.036 28.679 0.09 ;
     RECT  28.679 0.036 28.787 0.054 ;
     RECT  28.435 1.728 29.191 23.769 ;
     RECT  29.191 1.152 29.227 23.769 ;
     RECT  29.227 1.152 29.291 23.85 ;
     RECT  29.291 1.224 29.471 23.85 ;
     RECT  29.471 1.224 30.019 23.769 ;
     RECT  30.019 1.152 30.595 23.769 ;
     RECT  30.595 1.152 30.731 23.814 ;
     RECT  30.731 1.224 31.495 23.769 ;
     RECT  31.675 25.866 31.775 25.884 ;
     RECT  31.495 1.152 32.035 23.769 ;
     RECT  32.035 1.152 32.171 23.922 ;
     RECT  29.947 0.036 32.423 0.054 ;
     RECT  32.171 1.152 32.711 23.769 ;
     RECT  32.711 1.152 32.963 1.17 ;
     RECT  33.295 0.108 33.403 0.126 ;
     RECT  33.295 25.866 33.431 25.884 ;
     RECT  33.331 24.984 33.475 25.002 ;
     RECT  33.475 24.984 33.503 25.074 ;
     RECT  33.403 0.036 33.539 0.126 ;
     RECT  33.503 25.056 33.575 25.074 ;
     RECT  32.711 2.106 33.619 23.769 ;
     RECT  33.619 1.728 33.971 23.769 ;
     RECT  33.539 0.108 34.411 0.126 ;
     RECT  34.411 0.036 34.763 0.126 ;
     RECT  33.971 2.151 34.771 23.769 ;
     RECT  34.771 2.151 34.871 23.922 ;
     RECT  34.871 2.151 35.995 23.769 ;
     RECT  35.995 1.728 36.239 23.769 ;
     RECT  36.239 2.106 36.563 23.769 ;
     RECT  37.147 25.866 37.247 25.884 ;
     RECT  34.763 0.036 37.435 0.054 ;
     RECT  37.435 0.036 37.571 0.126 ;
     RECT  37.147 1.152 37.579 1.17 ;
     RECT  36.563 2.151 37.579 23.769 ;
     RECT  37.579 1.152 37.751 23.769 ;
     RECT  37.751 1.152 37.895 1.242 ;
     RECT  37.895 1.152 38.003 1.17 ;
     RECT  37.571 0.036 38.803 0.054 ;
     RECT  38.875 1.152 39.299 1.17 ;
     RECT  39.235 25.866 39.335 25.884 ;
     RECT  37.751 2.106 39.559 23.769 ;
     RECT  38.803 0.036 39.731 0.126 ;
     RECT  39.731 0.108 39.767 0.126 ;
     RECT  39.559 2.106 40.063 23.814 ;
     RECT  40.063 2.106 40.243 23.85 ;
     RECT  40.243 2.034 40.271 23.85 ;
     RECT  40.271 2.034 40.747 23.769 ;
     RECT  40.747 1.728 40.883 23.769 ;
     RECT  40.603 0.036 40.891 0.054 ;
     RECT  40.891 0.036 40.991 0.09 ;
     RECT  40.991 0.036 41.027 0.054 ;
     RECT  40.883 2.151 41.04 23.769 ;
     RECT  41.04 2.376 41.063 2.394 ;
     RECT  41.04 7.596 41.063 8.226 ;
     RECT  41.04 3.96 41.099 3.978 ;
     RECT  41.063 8.208 41.099 8.226 ;
     RECT  41.04 17.658 42.215 17.676 ;
     RECT  41.04 10.566 43.007 10.584 ;
    LAYER M3 ;
     RECT  2.304 0.012 40.914 0.031 ;
     RECT  2.304 0.031 41.022 2.371 ;
     RECT  2.304 2.371 41.058 2.489 ;
     RECT  2.34 2.489 41.058 3.955 ;
     RECT  2.34 3.955 41.094 8.231 ;
     RECT  2.34 8.231 41.022 10.229 ;
     RECT  2.34 10.229 40.986 10.319 ;
     RECT  2.376 10.319 40.986 10.589 ;
     RECT  42.984 7.531 43.002 10.589 ;
     RECT  2.415 10.589 40.986 11.129 ;
     RECT  2.415 11.129 40.95 13.639 ;
     RECT  2.415 13.639 41.022 16.259 ;
     RECT  2.415 16.259 40.986 17.959 ;
     RECT  2.415 17.959 41.022 18.265 ;
     RECT  0.216 18.157 0.234 18.413 ;
     RECT  42.192 17.653 42.21 18.413 ;
     RECT  2.376 18.265 41.022 19.309 ;
     RECT  2.34 19.309 41.022 19.921 ;
     RECT  2.304 19.921 41.022 20.309 ;
     RECT  2.34 20.309 41.022 20.489 ;
     RECT  2.34 20.489 40.986 21.235 ;
     RECT  2.304 21.235 41.022 22.747 ;
     RECT  2.268 22.747 41.022 23.405 ;
     RECT  2.304 23.405 41.022 23.657 ;
     RECT  2.304 23.657 40.914 25.901 ;
    LAYER M4 ;
     RECT  2.149 23.376 2.285 23.4 ;
     RECT  2.285 23.376 2.3 23.688 ;
     RECT  2.293 0.384 2.341 0.408 ;
     RECT  2.149 4.128 2.408 4.152 ;
     RECT  2.293 5.136 2.408 5.16 ;
     RECT  0.229 12.816 2.408 12.84 ;
     RECT  2.401 20.352 2.408 20.376 ;
     RECT  2.252 21.648 2.408 21.672 ;
     RECT  2.3 23.376 2.408 23.928 ;
     RECT  2.408 2.148 2.619 23.928 ;
     RECT  2.619 2.148 2.704 23.976 ;
     RECT  2.341 0.288 2.725 0.408 ;
     RECT  2.704 2.784 2.819 3.048 ;
     RECT  2.704 9.36 2.819 10.056 ;
     RECT  2.704 21.552 2.819 23.976 ;
     RECT  2.819 2.784 2.837 2.952 ;
     RECT  2.704 15.36 2.837 15.432 ;
     RECT  2.837 2.784 2.867 2.808 ;
     RECT  2.819 21.552 2.867 22.344 ;
     RECT  2.704 4.128 2.909 5.112 ;
     RECT  2.704 11.184 2.981 13.656 ;
     RECT  2.704 7.92 3.341 7.944 ;
     RECT  2.704 6.72 3.532 6.888 ;
     RECT  2.909 4.56 3.557 5.112 ;
     RECT  2.981 11.952 3.587 13.656 ;
     RECT  3.532 6.864 3.665 6.888 ;
     RECT  2.704 17.664 3.665 17.688 ;
     RECT  2.819 9.696 3.697 10.056 ;
     RECT  3.557 5.088 3.737 5.112 ;
     RECT  2.725 0.192 3.781 0.408 ;
     RECT  2.725 1.728 3.781 1.752 ;
     RECT  3.781 0.192 3.881 1.752 ;
     RECT  2.867 21.6 3.917 22.344 ;
     RECT  3.697 9.696 3.925 10.872 ;
     RECT  2.704 20.352 3.925 20.424 ;
     RECT  3.917 21.6 3.971 21.672 ;
     RECT  2.819 23.376 4.019 23.976 ;
     RECT  3.805 2.976 4.093 3 ;
     RECT  3.881 1.728 4.129 1.752 ;
     RECT  4.093 2.736 4.129 3 ;
     RECT  2.837 15.408 4.201 15.432 ;
     RECT  3.881 0.192 4.205 0.552 ;
     RECT  4.129 1.728 4.205 3 ;
     RECT  2.972 25.104 4.345 25.128 ;
     RECT  4.205 1.728 4.403 2.28 ;
     RECT  4.403 1.728 4.421 1.8 ;
     RECT  3.925 8.832 4.421 10.872 ;
     RECT  4.019 23.376 4.444 23.448 ;
     RECT  4.417 18.24 4.489 18.264 ;
     RECT  3.587 11.952 4.493 13.32 ;
     RECT  4.201 14.784 4.547 15.432 ;
     RECT  4.489 18.24 4.556 18.696 ;
     RECT  3.925 20.208 4.556 20.424 ;
     RECT  4.345 24.528 4.595 25.128 ;
     RECT  4.444 23.376 4.597 23.4 ;
     RECT  4.556 18.24 4.601 20.424 ;
     RECT  4.601 18.24 4.643 19.944 ;
     RECT  4.421 8.832 4.709 10.824 ;
     RECT  4.733 3.408 4.817 3.432 ;
     RECT  4.129 5.664 4.988 5.688 ;
     RECT  4.709 8.832 5.029 9.096 ;
     RECT  4.988 5.088 5.069 5.688 ;
     RECT  5.069 5.088 5.075 5.112 ;
     RECT  4.709 10.272 5.075 10.824 ;
     RECT  4.597 22.8 5.075 23.4 ;
     RECT  5.077 7.2 5.101 7.224 ;
     RECT  5.101 6.24 5.164 7.224 ;
     RECT  4.547 14.832 5.177 15.432 ;
     RECT  4.205 0.192 5.221 0.216 ;
     RECT  3.971 21.6 5.281 21.624 ;
     RECT  4.595 25.104 5.317 25.128 ;
     RECT  4.643 18.24 5.321 18.792 ;
     RECT  5.317 25.104 5.353 25.704 ;
     RECT  5.075 10.704 5.425 10.824 ;
     RECT  5.353 25.104 5.437 25.8 ;
     RECT  5.281 21.456 5.461 21.624 ;
     RECT  5.221 0.192 5.465 0.6 ;
     RECT  5.425 10.704 5.465 11.4 ;
     RECT  5.321 18.24 5.465 18.696 ;
     RECT  4.421 1.728 5.5 1.752 ;
     RECT  5.465 18.24 5.509 18.264 ;
     RECT  5.075 23.376 5.509 23.4 ;
     RECT  5.509 17.088 5.533 17.112 ;
     RECT  5.465 0.576 5.537 0.6 ;
     RECT  5.461 21.456 5.537 22.248 ;
     RECT  5.509 18.144 5.555 18.264 ;
     RECT  4.493 12.816 5.557 13.32 ;
     RECT  5.533 16.56 5.596 17.112 ;
     RECT  5.596 16.56 5.617 16.584 ;
     RECT  5.164 6.24 5.645 6.264 ;
     RECT  5.537 22.224 5.699 22.248 ;
     RECT  5.555 18.144 5.857 18.168 ;
     RECT  5.557 12.816 5.897 13.656 ;
     RECT  5.177 14.832 5.897 15.384 ;
     RECT  5.5 1.728 6.073 1.8 ;
     RECT  5.509 23.376 6.145 23.448 ;
     RECT  5.437 25.104 6.179 25.128 ;
     RECT  6.073 1.728 6.181 2.28 ;
     RECT  6.145 22.752 6.188 23.448 ;
     RECT  6.181 1.728 6.289 2.952 ;
     RECT  5.605 4.56 6.325 4.584 ;
     RECT  6.289 1.2 6.433 2.952 ;
     RECT  6.325 4.56 6.433 4.872 ;
     RECT  6.433 1.2 6.481 4.872 ;
     RECT  4.643 19.92 6.563 19.944 ;
     RECT  6.481 1.728 6.613 4.872 ;
     RECT  6.245 21.072 6.613 21.096 ;
     RECT  6.605 0.192 6.62 0.216 ;
     RECT  5.897 14.832 6.649 15.192 ;
     RECT  6.613 1.728 6.661 5.112 ;
     RECT  6.649 14.688 6.755 15.192 ;
     RECT  6.661 1.728 6.761 5.736 ;
     RECT  6.613 20.304 6.797 21.144 ;
     RECT  5.029 8.208 6.865 9.096 ;
     RECT  6.188 22.752 6.973 23.64 ;
     RECT  6.901 16.224 7.009 16.248 ;
     RECT  6.973 22.704 7.081 23.64 ;
     RECT  6.761 3.312 7.189 5.736 ;
     RECT  6.755 14.784 7.189 15.192 ;
     RECT  7.009 16.224 7.189 16.392 ;
     RECT  7.081 22.704 7.261 23.736 ;
     RECT  7.189 3.312 7.325 6.264 ;
     RECT  6.62 0.192 7.333 0.408 ;
     RECT  5.465 11.376 7.369 11.4 ;
     RECT  7.333 0.048 7.379 0.408 ;
     RECT  5.897 12.816 7.405 13.608 ;
     RECT  7.189 14.784 7.477 16.392 ;
     RECT  6.797 20.304 7.549 21.096 ;
     RECT  5.857 17.616 7.613 18.168 ;
     RECT  7.573 25.68 7.621 25.704 ;
     RECT  7.621 25.68 7.661 25.8 ;
     RECT  6.865 8.208 7.669 9.384 ;
     RECT  7.369 10.848 7.669 11.4 ;
     RECT  7.661 25.776 7.705 25.8 ;
     RECT  7.379 0.048 7.715 0.312 ;
     RECT  7.261 22.272 7.724 23.736 ;
     RECT  7.724 22.272 7.729 23.928 ;
     RECT  7.405 12.816 7.765 13.656 ;
     RECT  6.761 1.728 7.808 2.28 ;
     RECT  7.325 3.312 7.808 6.312 ;
     RECT  7.669 8.208 7.808 11.4 ;
     RECT  7.765 12.48 7.808 13.656 ;
     RECT  7.477 14.784 7.808 16.536 ;
     RECT  7.613 17.616 7.808 18.84 ;
     RECT  7.549 19.968 7.808 21.096 ;
     RECT  7.729 22.272 7.808 24.024 ;
     RECT  7.808 1.728 8.104 24.024 ;
     RECT  8.104 10.944 8.165 11.256 ;
     RECT  8.104 12.48 8.201 15.048 ;
     RECT  8.104 16.32 8.339 16.392 ;
     RECT  8.104 21.552 8.377 24.024 ;
     RECT  8.104 2.928 8.483 5.592 ;
     RECT  7.715 0.288 8.533 0.312 ;
     RECT  8.377 21.552 8.579 24.072 ;
     RECT  8.579 21.552 8.62 21.576 ;
     RECT  8.104 17.856 8.633 18.744 ;
     RECT  8.533 0.288 8.801 0.6 ;
     RECT  8.801 0.192 8.813 0.6 ;
     RECT  8.579 23.232 8.867 24.072 ;
     RECT  8.813 0.192 8.885 0.216 ;
     RECT  8.867 23.712 8.953 24.072 ;
     RECT  8.633 17.856 8.993 18.696 ;
     RECT  8.953 23.712 9.059 24.552 ;
     RECT  8.165 10.944 9.065 10.968 ;
     RECT  8.104 1.728 9.157 1.848 ;
     RECT  8.483 2.928 9.157 5.112 ;
     RECT  9.157 1.728 9.244 5.112 ;
     RECT  8.104 7.968 9.245 9.72 ;
     RECT  8.104 20.448 9.349 20.568 ;
     RECT  9.301 25.68 9.349 25.704 ;
     RECT  8.339 16.368 9.493 16.392 ;
     RECT  8.201 12.48 9.5 14.088 ;
     RECT  9.493 15.984 9.533 16.392 ;
     RECT  9.5 12.48 9.587 14.376 ;
     RECT  9.245 7.968 9.641 8.664 ;
     RECT  9.349 20.448 9.673 21.096 ;
     RECT  9.059 24.528 9.731 24.552 ;
     RECT  9.673 20.448 9.779 21.576 ;
     RECT  9.349 25.68 9.785 25.8 ;
     RECT  9.785 25.68 9.827 25.704 ;
     RECT  9.244 1.728 10.067 2.28 ;
     RECT  8.993 17.856 10.069 17.88 ;
     RECT  9.997 10.896 10.081 10.92 ;
     RECT  9.244 3.264 10.163 5.112 ;
     RECT  9.779 20.448 10.253 21.288 ;
     RECT  9.533 15.984 10.289 16.104 ;
     RECT  9.245 9.648 10.321 9.72 ;
     RECT  10.163 3.264 10.325 4.248 ;
     RECT  10.249 14.832 10.333 14.856 ;
     RECT  10.325 3.936 10.403 4.248 ;
     RECT  9.587 12.48 10.433 13.656 ;
     RECT  9.889 23.376 10.453 23.4 ;
     RECT  10.253 20.448 10.469 21.192 ;
     RECT  10.453 23.376 10.577 23.736 ;
     RECT  9.641 7.968 10.609 8.184 ;
     RECT  10.261 0.576 10.649 0.6 ;
     RECT  10.433 12.48 10.649 13.08 ;
     RECT  10.069 17.856 10.825 18.696 ;
     RECT  10.289 16.08 10.865 16.104 ;
     RECT  10.825 17.856 10.933 19.368 ;
     RECT  10.933 17.088 10.973 19.368 ;
     RECT  10.067 1.728 11.081 2.184 ;
     RECT  11.041 5.712 11.257 5.736 ;
     RECT  10.577 23.376 11.365 23.448 ;
     RECT  11.221 21.312 11.411 21.336 ;
     RECT  10.609 7.872 11.473 8.184 ;
     RECT  11.113 14.064 11.545 14.088 ;
     RECT  11.545 14.064 11.581 14.856 ;
     RECT  11.365 22.8 11.581 23.448 ;
     RECT  11.573 2.736 11.605 2.76 ;
     RECT  11.581 22.8 11.605 23.496 ;
     RECT  11.605 2.736 11.657 3.096 ;
     RECT  11.257 5.712 11.689 5.784 ;
     RECT  11.657 3.072 11.692 3.096 ;
     RECT  11.473 7.872 11.747 8.616 ;
     RECT  10.321 9.648 11.747 10.872 ;
     RECT  11.257 24.528 11.747 24.6 ;
     RECT  11.689 5.664 11.761 5.784 ;
     RECT  11.761 5.664 11.773 7.368 ;
     RECT  11.747 24.576 11.833 24.6 ;
     RECT  11.581 14.064 11.837 15.528 ;
     RECT  11.833 24.576 11.843 25.176 ;
     RECT  10.973 17.088 11.9 18.12 ;
     RECT  11.605 21.648 11.939 23.496 ;
     RECT  11.747 8.592 11.941 8.616 ;
     RECT  11.747 9.648 11.941 10.2 ;
     RECT  11.9 16.992 11.941 18.12 ;
     RECT  11.941 16.992 11.987 18.216 ;
     RECT  11.605 0.192 11.989 0.216 ;
     RECT  10.973 19.344 12.013 19.368 ;
     RECT  12.013 19.344 12.017 19.992 ;
     RECT  11.773 5.712 12.053 7.368 ;
     RECT  11.989 0.192 12.085 0.264 ;
     RECT  10.649 12.48 12.085 12.84 ;
     RECT  11.843 25.104 12.113 25.176 ;
     RECT  11.941 8.592 12.161 10.2 ;
     RECT  12.017 19.968 12.227 19.992 ;
     RECT  12.085 12.48 12.325 12.936 ;
     RECT  12.325 12.48 12.373 13.08 ;
     RECT  11.987 17.664 12.445 18.216 ;
     RECT  12.085 0.192 12.448 0.312 ;
     RECT  12.113 25.104 12.485 25.8 ;
     RECT  12.448 0.192 12.701 0.36 ;
     RECT  12.485 25.2 12.707 25.8 ;
     RECT  12.517 16.512 12.733 16.536 ;
     RECT  12.161 8.592 12.769 9.096 ;
     RECT  12.716 25.824 12.803 25.848 ;
     RECT  12.053 5.712 12.805 5.736 ;
     RECT  10.403 4.224 12.853 4.248 ;
     RECT  12.161 10.176 12.877 10.2 ;
     RECT  11.939 21.648 12.908 23.4 ;
     RECT  12.853 4.224 12.949 4.584 ;
     RECT  12.908 21.648 12.985 23.496 ;
     RECT  12.445 17.664 13.021 18.792 ;
     RECT  11.837 14.064 13.045 14.856 ;
     RECT  12.949 3.408 13.093 4.584 ;
     RECT  12.805 5.568 13.093 5.736 ;
     RECT  12.877 10.176 13.093 10.344 ;
     RECT  12.373 11.952 13.093 13.08 ;
     RECT  12.701 0.288 13.141 0.36 ;
     RECT  11.081 1.728 13.208 1.752 ;
     RECT  13.093 2.832 13.208 5.736 ;
     RECT  12.053 6.864 13.208 7.368 ;
     RECT  12.769 8.496 13.208 9.096 ;
     RECT  13.093 10.176 13.208 13.08 ;
     RECT  13.045 14.064 13.208 15.096 ;
     RECT  12.733 16.272 13.208 16.536 ;
     RECT  13.021 17.664 13.208 18.936 ;
     RECT  12.985 21.648 13.208 23.928 ;
     RECT  13.208 1.728 13.42 23.928 ;
     RECT  13.42 1.728 13.504 23.88 ;
     RECT  13.141 0.288 13.601 0.552 ;
     RECT  13.504 1.728 13.601 5.592 ;
     RECT  13.601 0.288 13.619 0.312 ;
     RECT  13.504 21.984 13.637 23.88 ;
     RECT  13.601 2.88 13.673 5.592 ;
     RECT  13.673 2.88 13.817 4.536 ;
     RECT  13.504 8.496 13.817 11.448 ;
     RECT  13.909 25.68 13.957 25.704 ;
     RECT  13.504 18.192 14.041 19.944 ;
     RECT  13.957 25.68 14.041 25.8 ;
     RECT  13.817 8.496 14.069 11.352 ;
     RECT  14.041 19.92 14.105 19.944 ;
     RECT  14.041 25.68 14.177 25.704 ;
     RECT  13.504 12.816 14.393 14.856 ;
     RECT  14.393 12.816 14.429 14.184 ;
     RECT  14.069 8.496 14.435 9.672 ;
     RECT  14.429 12.816 14.435 14.088 ;
     RECT  13.637 21.984 14.435 23.496 ;
     RECT  13.504 16.032 14.533 16.536 ;
     RECT  13.817 3.984 14.609 4.536 ;
     RECT  14.069 10.8 14.609 11.352 ;
     RECT  14.773 0.192 14.869 0.216 ;
     RECT  13.817 2.88 14.965 2.904 ;
     RECT  13.601 1.728 15.001 1.848 ;
     RECT  14.965 2.88 15.001 3.432 ;
     RECT  15.001 1.728 15.005 3.432 ;
     RECT  13.504 7.344 15.013 7.368 ;
     RECT  14.041 18.192 15.037 18.84 ;
     RECT  15.013 6.672 15.1 7.368 ;
     RECT  15.037 17.952 15.109 18.84 ;
     RECT  14.609 4.512 15.113 4.536 ;
     RECT  14.869 0.192 15.221 0.264 ;
     RECT  14.435 8.496 15.329 9.144 ;
     RECT  15.329 9.072 15.365 9.144 ;
     RECT  14.533 16.032 15.397 16.968 ;
     RECT  15.109 17.952 15.397 19.032 ;
     RECT  15.397 16.032 15.433 19.032 ;
     RECT  14.605 20.592 15.433 20.616 ;
     RECT  13.673 5.568 15.437 5.592 ;
     RECT  15.433 16.032 15.481 20.616 ;
     RECT  14.435 21.984 15.689 23.448 ;
     RECT  15.481 18.192 15.731 20.616 ;
     RECT  14.435 12.816 15.788 13.512 ;
     RECT  15.757 14.832 15.788 14.856 ;
     RECT  14.609 10.848 15.793 11.352 ;
     RECT  15.481 16.032 15.833 16.968 ;
     RECT  15.731 18.672 15.833 20.616 ;
     RECT  15.005 1.728 15.875 2.28 ;
     RECT  15.788 12.816 15.875 14.856 ;
     RECT  15.875 1.728 15.905 1.848 ;
     RECT  15.875 14.832 15.905 14.856 ;
     RECT  15.833 18.672 15.977 19.896 ;
     RECT  15.005 3.36 16.009 3.432 ;
     RECT  15.1 7.344 16.013 7.368 ;
     RECT  16.009 2.832 16.121 3.432 ;
     RECT  15.833 16.032 16.189 16.824 ;
     RECT  15.977 18.672 16.265 19.608 ;
     RECT  15.221 0.192 16.309 0.216 ;
     RECT  15.689 23.376 16.477 23.448 ;
     RECT  15.365 9.072 16.508 9.096 ;
     RECT  15.793 10.848 16.553 11.448 ;
     RECT  16.508 8.64 16.595 9.096 ;
     RECT  16.553 11.424 16.691 11.448 ;
     RECT  16.121 3.408 16.7 3.432 ;
     RECT  16.645 9.36 16.732 9.672 ;
     RECT  16.549 6.192 16.741 6.216 ;
     RECT  15.689 21.984 16.765 22.104 ;
     RECT  16.477 23.376 16.765 23.976 ;
     RECT  16.189 15.024 16.769 16.824 ;
     RECT  16.7 3.408 16.787 4.344 ;
     RECT  15.905 1.728 17.093 1.8 ;
     RECT  16.741 5.424 17.132 6.216 ;
     RECT  16.309 0.192 17.189 0.312 ;
     RECT  17.132 5.424 17.197 6.264 ;
     RECT  17.197 5.184 17.219 6.264 ;
     RECT  16.787 3.408 17.233 3.432 ;
     RECT  16.765 21.984 17.233 23.976 ;
     RECT  16.945 18.192 17.237 18.216 ;
     RECT  15.875 12.816 17.269 13.848 ;
     RECT  17.233 3.072 17.273 3.432 ;
     RECT  17.273 3.072 17.381 3.096 ;
     RECT  17.269 12.528 17.413 13.848 ;
     RECT  16.769 15.024 17.413 16.248 ;
     RECT  16.265 19.584 17.413 19.608 ;
     RECT  17.233 21.984 17.459 24.024 ;
     RECT  17.413 18.816 17.485 19.608 ;
     RECT  17.189 0.192 17.633 1.176 ;
     RECT  17.485 18.816 17.653 19.704 ;
     RECT  16.732 9.36 17.737 9.384 ;
     RECT  17.653 18.816 17.845 20.568 ;
     RECT  17.459 21.984 17.845 23.928 ;
     RECT  16.477 7.392 18.037 7.416 ;
     RECT  18.037 7.392 18.169 7.896 ;
     RECT  17.413 12.528 18.169 16.248 ;
     RECT  17.633 0.192 18.323 0.552 ;
     RECT  17.219 5.184 18.349 6.216 ;
     RECT  18.169 7.392 18.349 7.944 ;
     RECT  18.373 25.68 18.421 25.704 ;
     RECT  17.845 18.816 18.457 23.928 ;
     RECT  18.323 0.192 18.461 0.504 ;
     RECT  18.421 25.68 18.461 25.8 ;
     RECT  18.349 5.184 18.493 7.944 ;
     RECT  17.737 9.36 18.493 10.344 ;
     RECT  18.169 12.528 18.493 17.112 ;
     RECT  18.461 25.776 18.505 25.8 ;
     RECT  18.341 1.728 18.608 1.752 ;
     RECT  17.737 2.88 18.608 2.904 ;
     RECT  18.493 5.184 18.608 10.344 ;
     RECT  18.493 12.24 18.608 17.112 ;
     RECT  18.457 18.816 18.608 24.552 ;
     RECT  18.608 1.728 18.899 24.552 ;
     RECT  18.899 1.728 18.904 23.928 ;
     RECT  18.904 10.128 19.139 16.008 ;
     RECT  18.904 18.192 19.153 22.248 ;
     RECT  18.904 5.088 19.181 5.208 ;
     RECT  19.153 21.168 19.217 22.248 ;
     RECT  19.139 10.32 19.253 16.008 ;
     RECT  19.153 18.192 19.289 19.608 ;
     RECT  18.904 6.72 19.667 6.888 ;
     RECT  18.904 23.28 19.667 23.928 ;
     RECT  19.217 21.168 19.721 21.528 ;
     RECT  19.181 5.088 19.763 5.112 ;
     RECT  19.253 11.76 19.793 16.008 ;
     RECT  18.904 17.088 19.793 17.112 ;
     RECT  18.904 3.408 19.829 4.104 ;
     RECT  18.904 1.728 19.901 2.28 ;
     RECT  18.904 7.968 19.907 9.096 ;
     RECT  19.907 7.968 19.916 8.52 ;
     RECT  19.793 11.76 19.973 15.864 ;
     RECT  19.901 2.16 20.005 2.28 ;
     RECT  20.005 2.16 20.009 2.328 ;
     RECT  19.973 12.816 20.045 15.864 ;
     RECT  19.253 10.32 20.051 10.536 ;
     RECT  19.667 6.768 20.081 6.888 ;
     RECT  20.009 2.304 20.089 2.328 ;
     RECT  20.045 15.312 20.099 15.864 ;
     RECT  18.461 0.192 20.101 0.36 ;
     RECT  20.045 12.816 20.189 14.232 ;
     RECT  20.099 15.312 20.225 15.432 ;
     RECT  19.289 18.192 20.261 18.84 ;
     RECT  20.101 0.192 20.297 0.6 ;
     RECT  20.189 12.816 20.333 13.704 ;
     RECT  20.149 19.968 20.333 19.992 ;
     RECT  20.081 6.816 20.401 6.888 ;
     RECT  19.916 7.92 20.401 8.52 ;
     RECT  20.051 10.32 20.405 10.344 ;
     RECT  19.667 23.28 20.509 23.736 ;
     RECT  20.401 6.816 20.531 8.52 ;
     RECT  20.333 12.816 20.549 13.656 ;
     RECT  20.531 7.968 20.579 8.52 ;
     RECT  19.525 25.104 20.627 25.128 ;
     RECT  20.261 18.768 20.689 18.84 ;
     RECT  19.721 21.504 20.725 21.528 ;
     RECT  20.531 6.816 20.765 6.888 ;
     RECT  19.973 11.76 20.837 11.784 ;
     RECT  20.225 15.312 20.909 15.336 ;
     RECT  20.509 22.8 20.977 23.736 ;
     RECT  20.581 2.88 20.981 2.904 ;
     RECT  20.977 22.8 21.107 23.928 ;
     RECT  20.725 21.168 21.193 21.528 ;
     RECT  19.829 4.08 21.197 4.104 ;
     RECT  21.193 20.592 21.233 21.528 ;
     RECT  21.107 22.8 21.299 23.736 ;
     RECT  21.085 9.648 21.481 10.248 ;
     RECT  20.765 6.864 21.557 6.888 ;
     RECT  20.579 8.496 21.596 8.52 ;
     RECT  20.549 12.816 21.625 13.08 ;
     RECT  20.689 18.768 21.625 19.368 ;
     RECT  21.299 22.8 21.629 23.448 ;
     RECT  21.596 7.92 21.637 8.52 ;
     RECT  21.637 7.44 21.683 8.568 ;
     RECT  21.653 14.928 21.685 14.952 ;
     RECT  21.625 18.192 21.709 19.368 ;
     RECT  20.297 0.192 21.733 0.36 ;
     RECT  21.683 7.44 21.737 7.464 ;
     RECT  21.709 18.768 21.773 19.368 ;
     RECT  21.629 23.376 21.779 23.448 ;
     RECT  21.733 0.192 21.953 0.6 ;
     RECT  21.625 12.528 21.985 13.08 ;
     RECT  21.685 14.64 21.985 14.952 ;
     RECT  21.481 9.648 22.021 10.872 ;
     RECT  22.021 9.648 22.169 10.968 ;
     RECT  21.985 12.528 22.201 14.952 ;
     RECT  21.683 8.496 22.205 8.568 ;
     RECT  22.201 12.336 22.241 14.952 ;
     RECT  21.949 4.56 22.313 4.584 ;
     RECT  21.233 20.592 22.313 20.616 ;
     RECT  22.093 24.528 22.345 24.552 ;
     RECT  21.953 0.192 22.451 0.552 ;
     RECT  22.345 24.528 22.451 25.128 ;
     RECT  21.625 5.712 22.561 5.736 ;
     RECT  21.445 1.728 22.661 1.752 ;
     RECT  22.241 12.336 22.7 13.08 ;
     RECT  21.229 16.656 22.705 16.68 ;
     RECT  22.661 21.072 22.733 21.096 ;
     RECT  22.733 21.072 22.745 21.72 ;
     RECT  22.7 11.952 22.787 13.08 ;
     RECT  22.661 1.728 22.789 1.8 ;
     RECT  22.561 5.712 22.789 6.6 ;
     RECT  22.745 21.504 22.789 21.72 ;
     RECT  21.773 18.768 22.813 18.792 ;
     RECT  22.381 19.776 22.813 19.8 ;
     RECT  22.169 9.648 22.817 10.632 ;
     RECT  22.813 18.72 22.817 19.8 ;
     RECT  22.705 16.656 22.844 16.728 ;
     RECT  21.779 23.424 22.849 23.448 ;
     RECT  22.789 5.712 22.876 6.888 ;
     RECT  22.789 21.504 22.885 22.248 ;
     RECT  22.849 23.376 22.885 23.448 ;
     RECT  22.876 5.712 22.925 6.6 ;
     RECT  22.817 18.72 22.925 19.56 ;
     RECT  22.844 16.656 22.931 17.016 ;
     RECT  22.789 1.728 22.961 1.848 ;
     RECT  22.787 12.336 22.997 13.08 ;
     RECT  22.885 21.504 23.173 23.448 ;
     RECT  22.451 24.528 23.173 24.552 ;
     RECT  22.931 16.656 23.245 16.728 ;
     RECT  23.173 21.504 23.249 24.552 ;
     RECT  22.817 10.608 23.389 10.632 ;
     RECT  22.451 0.192 23.461 0.456 ;
     RECT  23.249 21.504 23.785 24.024 ;
     RECT  23.777 25.776 23.804 25.8 ;
     RECT  22.925 6.576 23.857 6.6 ;
     RECT  23.804 25.68 23.861 25.8 ;
     RECT  23.861 25.68 23.891 25.704 ;
     RECT  22.205 8.496 23.929 8.52 ;
     RECT  22.961 1.728 23.932 1.8 ;
     RECT  23.785 21.072 23.987 24.024 ;
     RECT  23.857 6.576 24.001 7.368 ;
     RECT  23.932 1.68 24.008 1.8 ;
     RECT  23.173 2.832 24.008 2.856 ;
     RECT  23.569 4.512 24.008 5.016 ;
     RECT  24.001 6.576 24.008 7.416 ;
     RECT  23.929 8.496 24.008 8.76 ;
     RECT  23.389 10.608 24.008 11.256 ;
     RECT  22.997 12.48 24.008 13.08 ;
     RECT  22.241 14.832 24.008 14.952 ;
     RECT  23.245 15.936 24.008 16.728 ;
     RECT  22.925 18.72 24.008 18.744 ;
     RECT  23.987 21.072 24.008 23.928 ;
     RECT  24.008 1.68 24.221 23.928 ;
     RECT  23.461 0.192 24.229 0.552 ;
     RECT  24.221 1.68 24.304 23.88 ;
     RECT  24.229 0.192 24.467 0.648 ;
     RECT  24.304 19.632 24.473 23.88 ;
     RECT  24.304 8.4 24.508 9.24 ;
     RECT  24.304 1.68 24.509 7.416 ;
     RECT  24.508 8.4 24.509 8.76 ;
     RECT  24.467 0.192 24.515 0.456 ;
     RECT  24.304 10.224 24.515 13.848 ;
     RECT  24.509 1.728 24.563 7.416 ;
     RECT  24.515 10.224 24.725 13.176 ;
     RECT  24.725 11.952 24.851 13.176 ;
     RECT  24.473 19.632 24.869 23.592 ;
     RECT  24.304 17.088 25.049 18.408 ;
     RECT  25.009 25.104 25.139 25.128 ;
     RECT  25.049 17.472 25.297 18.408 ;
     RECT  24.869 19.632 25.297 20.616 ;
     RECT  24.725 10.224 25.324 10.872 ;
     RECT  25.297 17.472 25.331 20.616 ;
     RECT  25.331 17.472 25.372 18.168 ;
     RECT  24.563 1.728 25.373 3.432 ;
     RECT  25.331 19.344 25.381 20.616 ;
     RECT  24.869 21.648 25.409 23.592 ;
     RECT  25.409 22.272 25.517 23.592 ;
     RECT  24.304 14.928 25.621 14.952 ;
     RECT  24.515 0.192 25.625 0.264 ;
     RECT  25.324 10.752 25.661 10.872 ;
     RECT  24.563 5.76 25.769 7.416 ;
     RECT  24.851 12.48 25.802 13.176 ;
     RECT  24.509 8.4 25.805 8.52 ;
     RECT  25.517 22.8 25.82 23.592 ;
     RECT  25.765 0.288 25.861 0.6 ;
     RECT  25.861 0.288 25.937 0.648 ;
     RECT  25.373 1.728 25.937 3.192 ;
     RECT  24.563 4.512 25.945 4.536 ;
     RECT  25.769 5.76 25.945 6.888 ;
     RECT  25.937 0.288 26.021 3.192 ;
     RECT  25.945 4.512 26.045 6.888 ;
     RECT  26.021 0.288 26.057 0.648 ;
     RECT  26.021 1.728 26.099 3.192 ;
     RECT  25.805 8.4 26.125 8.472 ;
     RECT  25.661 10.752 26.129 10.776 ;
     RECT  26.057 0.288 26.195 0.6 ;
     RECT  25.802 12.528 26.197 13.176 ;
     RECT  25.621 14.352 26.197 14.952 ;
     RECT  26.197 12.528 26.243 14.952 ;
     RECT  26.125 7.968 26.273 8.472 ;
     RECT  25.372 18.144 26.377 18.168 ;
     RECT  25.381 19.392 26.377 20.616 ;
     RECT  26.243 12.528 26.417 13.848 ;
     RECT  24.304 15.984 26.453 16.008 ;
     RECT  26.045 4.224 26.485 6.888 ;
     RECT  26.243 14.832 26.521 14.952 ;
     RECT  26.521 14.832 26.633 15 ;
     RECT  25.82 22.8 26.741 23.736 ;
     RECT  26.741 23.328 26.777 23.736 ;
     RECT  26.485 3.936 26.849 6.888 ;
     RECT  26.377 18.144 26.921 20.616 ;
     RECT  26.633 14.832 26.993 14.952 ;
     RECT  26.921 18.624 27.029 20.616 ;
     RECT  26.849 4.08 27.245 6.888 ;
     RECT  26.993 14.832 27.347 14.856 ;
     RECT  27.245 4.512 27.353 6.888 ;
     RECT  26.809 24.528 27.673 24.552 ;
     RECT  27.26 16.272 27.731 16.776 ;
     RECT  27.029 19.776 27.821 20.616 ;
     RECT  26.273 8.448 27.853 8.472 ;
     RECT  27.029 18.624 27.925 18.792 ;
     RECT  26.777 23.328 27.973 23.544 ;
     RECT  27.731 16.272 28.028 16.68 ;
     RECT  27.973 14.112 28.06 14.136 ;
     RECT  27.353 4.512 28.067 6.552 ;
     RECT  27.673 24.528 28.067 25.176 ;
     RECT  28.067 5.712 28.108 6.552 ;
     RECT  27.973 22.8 28.141 23.544 ;
     RECT  28.067 24.528 28.141 24.552 ;
     RECT  26.099 1.728 28.177 2.904 ;
     RECT  28.141 22.8 28.181 24.552 ;
     RECT  28.141 11.136 28.213 11.16 ;
     RECT  28.177 1.728 28.277 2.952 ;
     RECT  28.108 6.192 28.393 6.552 ;
     RECT  27.925 18.144 28.501 18.792 ;
     RECT  27.821 19.776 28.501 20.52 ;
     RECT  28.393 6.192 28.537 6.792 ;
     RECT  28.213 10.896 28.645 11.16 ;
     RECT  26.417 12.528 28.717 13.08 ;
     RECT  28.277 1.728 28.789 3.432 ;
     RECT  28.067 4.512 28.789 4.536 ;
     RECT  28.028 15.888 28.789 16.68 ;
     RECT  28.645 10.896 28.885 11.448 ;
     RECT  28.717 12.528 28.885 13.752 ;
     RECT  27.853 8.448 28.933 9.096 ;
     RECT  28.789 15.744 28.933 16.68 ;
     RECT  28.885 10.896 29.113 13.752 ;
     RECT  29.077 0.192 29.149 0.216 ;
     RECT  28.933 8.448 29.173 9.24 ;
     RECT  29.113 10.368 29.173 13.752 ;
     RECT  28.181 23.376 29.219 24.552 ;
     RECT  29.149 0.048 29.315 0.216 ;
     RECT  28.789 1.728 29.365 4.536 ;
     RECT  28.933 14.832 29.365 16.68 ;
     RECT  29.365 1.68 29.408 4.536 ;
     RECT  28.537 6.192 29.408 7.176 ;
     RECT  29.173 8.448 29.408 13.752 ;
     RECT  29.365 14.736 29.408 16.68 ;
     RECT  28.501 18.144 29.408 20.52 ;
     RECT  29.005 22.224 29.408 22.248 ;
     RECT  29.219 23.376 29.408 23.928 ;
     RECT  29.408 1.68 29.411 23.928 ;
     RECT  29.411 1.68 29.699 23.88 ;
     RECT  29.699 1.728 29.704 23.88 ;
     RECT  29.704 22.8 29.765 23.88 ;
     RECT  29.704 14.736 29.843 21.432 ;
     RECT  29.845 25.68 29.869 25.704 ;
     RECT  29.843 14.736 29.909 14.856 ;
     RECT  29.869 25.68 29.932 25.8 ;
     RECT  29.932 25.776 29.953 25.8 ;
     RECT  29.581 0.576 29.981 0.6 ;
     RECT  29.843 15.984 29.981 21.432 ;
     RECT  29.704 1.728 29.987 13.08 ;
     RECT  29.981 15.984 30.017 21.144 ;
     RECT  29.987 10.848 30.061 13.08 ;
     RECT  30.017 19.056 30.083 21.144 ;
     RECT  30.083 19.536 30.125 21.144 ;
     RECT  29.987 1.728 30.412 9.72 ;
     RECT  30.061 11.136 30.413 13.08 ;
     RECT  30.412 1.728 30.563 2.28 ;
     RECT  30.412 3.36 30.629 9.72 ;
     RECT  30.563 1.728 30.665 1.752 ;
     RECT  29.909 14.736 30.737 14.808 ;
     RECT  30.017 15.984 30.773 17.352 ;
     RECT  30.629 3.36 30.809 9.096 ;
     RECT  29.765 22.8 30.889 23.736 ;
     RECT  30.773 16.272 30.953 17.352 ;
     RECT  30.805 0.24 30.997 0.264 ;
     RECT  30.997 0.24 31.093 0.312 ;
     RECT  31.045 18.192 31.201 18.264 ;
     RECT  30.125 19.968 31.273 21.144 ;
     RECT  30.809 3.936 31.283 9.096 ;
     RECT  31.093 0.192 31.285 0.312 ;
     RECT  30.413 12.528 31.309 13.08 ;
     RECT  31.273 19.824 31.333 21.144 ;
     RECT  30.889 22.8 31.333 23.4 ;
     RECT  30.953 16.272 31.427 17.112 ;
     RECT  31.333 19.824 31.485 23.4 ;
     RECT  31.427 16.272 31.493 17.016 ;
     RECT  31.283 9.024 31.565 9.096 ;
     RECT  31.285 0.192 31.573 0.36 ;
     RECT  31.283 3.936 31.601 7.992 ;
     RECT  31.485 22.8 31.717 23.4 ;
     RECT  30.913 25.104 31.717 25.128 ;
     RECT  31.485 19.824 31.745 21.672 ;
     RECT  31.745 19.824 31.763 20.04 ;
     RECT  31.493 16.272 31.772 16.392 ;
     RECT  31.717 25.104 31.817 25.8 ;
     RECT  31.817 25.104 31.852 25.704 ;
     RECT  31.772 15.888 31.859 16.392 ;
     RECT  30.413 11.136 31.885 11.16 ;
     RECT  31.309 12.528 31.885 13.464 ;
     RECT  31.565 9.024 31.889 9.048 ;
     RECT  31.763 19.92 31.925 20.04 ;
     RECT  31.925 19.968 31.997 20.04 ;
     RECT  30.737 14.784 32.029 14.808 ;
     RECT  31.201 18.192 32.029 18.312 ;
     RECT  31.573 0.192 32.033 0.6 ;
     RECT  31.885 11.136 32.101 13.464 ;
     RECT  31.601 6.816 32.185 7.992 ;
     RECT  32.029 14.784 32.209 14.856 ;
     RECT  32.033 0.24 32.245 0.6 ;
     RECT  32.053 1.728 32.245 1.752 ;
     RECT  32.245 0.24 32.249 2.328 ;
     RECT  31.601 3.936 32.249 5.688 ;
     RECT  32.029 18.192 32.285 18.84 ;
     RECT  32.249 0.576 32.357 2.328 ;
     RECT  31.717 23.04 32.396 23.4 ;
     RECT  32.249 3.936 32.435 4.536 ;
     RECT  32.285 18.192 32.437 18.216 ;
     RECT  31.745 21.12 32.437 21.672 ;
     RECT  32.185 7.776 32.465 7.992 ;
     RECT  32.101 10.992 32.465 13.464 ;
     RECT  32.465 12.528 32.537 13.464 ;
     RECT  32.437 17.664 32.677 18.216 ;
     RECT  32.677 17.52 32.681 18.216 ;
     RECT  32.465 7.872 32.821 7.992 ;
     RECT  32.357 0.576 32.861 0.6 ;
     RECT  32.437 21.504 32.893 21.672 ;
     RECT  32.396 23.04 32.893 23.496 ;
     RECT  32.537 12.768 33.005 13.464 ;
     RECT  32.357 1.728 33.073 2.328 ;
     RECT  32.209 14.64 33.073 14.856 ;
     RECT  31.859 16.368 33.073 16.392 ;
     RECT  32.893 21.504 33.251 23.496 ;
     RECT  33.073 1.728 33.301 2.568 ;
     RECT  33.251 22.8 33.325 23.496 ;
     RECT  32.435 4.416 33.329 4.536 ;
     RECT  31.997 20.016 33.433 20.04 ;
     RECT  33.301 1.728 33.437 2.904 ;
     RECT  32.465 10.992 33.437 11.16 ;
     RECT  33.073 14.64 33.437 16.392 ;
     RECT  33.433 19.392 33.461 20.04 ;
     RECT  33.251 21.504 33.461 21.528 ;
     RECT  33.005 13.056 33.493 13.464 ;
     RECT  32.249 5.664 33.617 5.688 ;
     RECT  33.493 13.056 33.617 14.136 ;
     RECT  33.325 22.8 33.635 23.976 ;
     RECT  33.437 1.728 33.683 2.568 ;
     RECT  33.605 10.272 33.689 10.296 ;
     RECT  33.461 19.392 33.827 21.528 ;
     RECT  33.781 0.192 33.877 0.216 ;
     RECT  32.821 7.872 33.937 8.472 ;
     RECT  33.617 13.056 33.973 13.464 ;
     RECT  33.685 4.032 34.045 4.056 ;
     RECT  33.721 6.816 34.076 6.84 ;
     RECT  33.937 7.872 34.076 9.096 ;
     RECT  32.681 17.52 34.117 17.64 ;
     RECT  33.683 1.728 34.157 1.752 ;
     RECT  33.827 19.392 34.165 20.328 ;
     RECT  33.877 0.192 34.253 0.264 ;
     RECT  33.827 21.504 34.297 21.528 ;
     RECT  33.635 22.8 34.297 23.928 ;
     RECT  34.045 3.936 34.453 4.056 ;
     RECT  33.577 11.328 34.469 11.352 ;
     RECT  34.117 17.52 34.477 18.216 ;
     RECT  34.165 19.2 34.477 20.328 ;
     RECT  34.469 11.232 34.501 11.352 ;
     RECT  33.973 12.336 34.501 13.464 ;
     RECT  33.437 15.36 34.585 16.392 ;
     RECT  34.253 0.192 34.645 0.312 ;
     RECT  34.477 2.832 34.645 2.856 ;
     RECT  34.297 21.504 34.69 23.928 ;
     RECT  34.645 0.192 34.787 0.408 ;
     RECT  34.645 2.832 34.808 2.904 ;
     RECT  34.453 3.888 34.808 4.056 ;
     RECT  34.369 5.136 34.808 5.16 ;
     RECT  34.076 6.816 34.808 9.096 ;
     RECT  34.261 10.176 34.808 10.2 ;
     RECT  34.501 11.232 34.808 13.464 ;
     RECT  34.585 14.496 34.808 16.392 ;
     RECT  34.477 17.52 34.808 20.328 ;
     RECT  34.69 21.504 34.808 23.976 ;
     RECT  34.808 2.016 34.813 23.976 ;
     RECT  34.813 2.016 35.104 23.88 ;
     RECT  35.104 2.016 35.125 2.904 ;
     RECT  35.104 3.888 35.165 3.96 ;
     RECT  35.104 6.816 35.201 7.992 ;
     RECT  31.852 25.104 35.221 25.128 ;
     RECT  35.104 5.232 35.245 5.64 ;
     RECT  35.104 9.072 35.267 11.496 ;
     RECT  35.104 16.032 35.267 21.768 ;
     RECT  35.221 25.104 35.269 25.704 ;
     RECT  35.125 1.728 35.273 2.904 ;
     RECT  35.267 18.72 35.273 21.768 ;
     RECT  35.273 2.88 35.309 2.904 ;
     RECT  35.273 18.72 35.317 21.672 ;
     RECT  35.269 25.104 35.353 25.8 ;
     RECT  35.267 10.512 35.356 11.496 ;
     RECT  35.353 25.104 35.413 25.128 ;
     RECT  35.317 18.72 35.555 21.576 ;
     RECT  35.267 16.032 35.597 17.688 ;
     RECT  35.104 14.496 35.785 14.808 ;
     RECT  35.104 23.136 35.809 23.88 ;
     RECT  35.413 25.056 35.809 25.128 ;
     RECT  35.555 18.72 35.836 18.888 ;
     RECT  35.785 14.496 35.849 14.52 ;
     RECT  34.787 0.192 35.893 0.312 ;
     RECT  35.273 1.728 35.893 1.752 ;
     RECT  35.555 19.968 35.921 21.576 ;
     RECT  35.809 23.136 35.939 25.128 ;
     RECT  35.245 5.232 36.137 5.256 ;
     RECT  35.201 7.488 36.137 7.992 ;
     RECT  35.893 0.192 36.209 1.752 ;
     RECT  35.921 19.968 36.209 21.528 ;
     RECT  36.209 1.68 36.227 1.752 ;
     RECT  35.939 23.136 36.245 23.976 ;
     RECT  35.939 25.104 36.349 25.128 ;
     RECT  35.597 16.032 36.421 17.352 ;
     RECT  35.165 3.936 36.569 3.96 ;
     RECT  35.104 12.48 36.569 13.128 ;
     RECT  35.356 10.512 36.601 11.208 ;
     RECT  36.209 19.968 36.605 21.144 ;
     RECT  36.349 25.104 36.611 25.176 ;
     RECT  36.137 7.824 36.673 7.992 ;
     RECT  35.267 9.072 36.673 9.096 ;
     RECT  36.611 25.152 36.707 25.176 ;
     RECT  36.673 7.824 36.757 9.096 ;
     RECT  36.601 10.368 36.757 11.208 ;
     RECT  36.605 20.544 36.785 21.144 ;
     RECT  36.757 7.824 36.817 11.208 ;
     RECT  36.569 12.48 36.817 12.504 ;
     RECT  36.421 15.984 36.817 17.352 ;
     RECT  36.817 7.824 36.844 12.504 ;
     RECT  36.227 1.728 36.845 1.752 ;
     RECT  36.817 15.984 36.857 17.496 ;
     RECT  36.529 14.256 36.901 14.28 ;
     RECT  36.845 1.728 36.929 1.8 ;
     RECT  36.844 7.824 36.947 9.144 ;
     RECT  36.844 10.368 37.001 12.504 ;
     RECT  37.001 10.512 37.043 12.504 ;
     RECT  36.245 23.184 37.091 23.976 ;
     RECT  35.836 18.864 37.093 18.888 ;
     RECT  37.043 10.848 37.145 12.504 ;
     RECT  36.209 0.192 37.181 0.264 ;
     RECT  36.901 13.68 37.217 14.28 ;
     RECT  36.947 7.824 37.285 7.896 ;
     RECT  37.145 10.848 37.289 11.448 ;
     RECT  36.785 20.544 37.397 20.76 ;
     RECT  37.181 0.24 37.469 0.264 ;
     RECT  36.673 4.272 37.537 4.392 ;
     RECT  37.537 3.84 37.573 4.392 ;
     RECT  37.573 3.84 37.577 5.064 ;
     RECT  37.091 23.184 37.609 23.448 ;
     RECT  36.929 1.728 37.613 1.752 ;
     RECT  37.285 7.44 37.645 7.896 ;
     RECT  37.093 18.816 37.724 18.888 ;
     RECT  37.577 5.04 37.753 5.064 ;
     RECT  37.724 18.816 37.811 19.368 ;
     RECT  37.645 6.576 37.865 7.896 ;
     RECT  37.217 14.256 37.897 14.28 ;
     RECT  37.577 3.84 37.909 3.864 ;
     RECT  37.897 14.256 37.933 14.856 ;
     RECT  37.621 0.576 37.973 0.6 ;
     RECT  37.753 5.04 38.185 5.16 ;
     RECT  37.289 11.424 38.225 11.448 ;
     RECT  36.857 17.472 38.293 17.496 ;
     RECT  37.865 7.44 38.365 7.896 ;
     RECT  36.947 9.12 38.365 9.144 ;
     RECT  37.609 22.8 38.365 23.448 ;
     RECT  38.365 7.44 38.369 9.144 ;
     RECT  37.397 20.736 38.401 20.76 ;
     RECT  38.365 22.8 38.437 23.736 ;
     RECT  36.857 16.368 38.444 16.392 ;
     RECT  38.293 17.472 38.444 17.688 ;
     RECT  37.909 2.88 38.533 3.864 ;
     RECT  38.369 8.448 38.549 9.144 ;
     RECT  38.437 22.752 38.675 23.736 ;
     RECT  38.581 11.376 38.684 11.4 ;
     RECT  38.533 2.304 38.689 3.864 ;
     RECT  37.933 14.256 38.725 15.384 ;
     RECT  38.444 16.368 38.725 17.688 ;
     RECT  38.401 20.544 38.765 20.76 ;
     RECT  38.473 13.056 38.837 13.08 ;
     RECT  38.833 6.336 38.869 6.36 ;
     RECT  38.833 19.968 38.917 19.992 ;
     RECT  38.689 1.728 38.941 3.864 ;
     RECT  38.185 5.04 38.941 5.352 ;
     RECT  38.941 1.68 38.977 5.352 ;
     RECT  38.869 6.336 38.977 6.888 ;
     RECT  38.725 14.256 39.013 17.688 ;
     RECT  37.811 18.816 39.121 18.84 ;
     RECT  38.675 22.752 39.203 23.592 ;
     RECT  38.977 1.68 39.251 6.888 ;
     RECT  38.941 0.288 39.395 0.312 ;
     RECT  39.251 1.728 39.445 6.888 ;
     RECT  39.121 18.816 39.481 19.416 ;
     RECT  39.301 10.032 39.517 10.056 ;
     RECT  38.684 11.04 39.517 11.4 ;
     RECT  39.445 1.728 39.548 6.984 ;
     RECT  38.549 8.448 39.548 9 ;
     RECT  39.337 21.12 39.733 21.144 ;
     RECT  39.692 12.384 39.949 12.408 ;
     RECT  39.013 13.488 39.949 17.688 ;
     RECT  39.203 23.376 40.021 23.592 ;
     RECT  39.481 18.768 40.049 19.416 ;
     RECT  39.733 20.544 40.049 21.144 ;
     RECT  39.548 1.728 40.208 9 ;
     RECT  39.517 10.032 40.208 11.4 ;
     RECT  39.949 12.384 40.208 17.688 ;
     RECT  40.049 18.768 40.208 21.144 ;
     RECT  39.365 22.224 40.208 22.296 ;
     RECT  40.021 23.376 40.208 23.928 ;
     RECT  40.208 1.728 40.211 23.928 ;
     RECT  40.129 0.528 40.453 0.552 ;
     RECT  40.211 1.728 40.504 23.88 ;
     RECT  40.504 5.184 40.529 5.208 ;
     RECT  40.504 21.936 40.565 23.88 ;
     RECT  40.565 21.936 40.643 23.544 ;
     RECT  40.453 0.192 40.673 0.552 ;
     RECT  39.697 25.104 40.673 25.128 ;
     RECT  40.504 1.728 40.691 1.848 ;
     RECT  40.504 15.984 40.691 17.112 ;
     RECT  40.504 10.848 40.739 11.736 ;
     RECT  40.691 15.984 40.745 16.872 ;
     RECT  40.504 18.24 40.753 18.84 ;
     RECT  40.504 2.832 40.781 3.96 ;
     RECT  40.739 10.848 40.787 10.872 ;
     RECT  40.781 3.936 40.825 3.96 ;
     RECT  40.781 2.832 40.835 2.856 ;
     RECT  40.673 0.528 40.883 0.552 ;
     RECT  40.504 9.696 40.925 9.72 ;
     RECT  40.745 16.848 40.931 16.872 ;
     RECT  40.643 22.8 40.961 23.544 ;
     RECT  40.504 20.544 40.969 20.568 ;
     RECT  40.961 23.52 40.979 23.544 ;
     RECT  40.753 18.816 40.997 18.84 ;
     RECT  40.691 1.728 41.005 1.752 ;
    LAYER M5 ;
     RECT  7.68 0.037 7.704 0.144 ;
     RECT  29.28 0.037 29.304 0.144 ;
     RECT  2.16 0.144 40.968 0.323 ;
     RECT  16.944 0.323 40.968 1.187 ;
     RECT  18.384 1.187 40.968 1.715 ;
     RECT  2.16 0.323 15.864 1.763 ;
     RECT  16.944 1.187 17.064 1.763 ;
     RECT  18.384 1.715 35.64 1.763 ;
     RECT  36.672 1.715 40.968 1.763 ;
     RECT  4.272 1.763 10.776 1.811 ;
     RECT  17.04 1.763 17.064 1.811 ;
     RECT  22.704 1.763 32.28 1.811 ;
     RECT  36.864 1.763 40.68 1.811 ;
     RECT  22.8 1.811 22.824 1.859 ;
     RECT  37.824 1.811 40.68 1.859 ;
     RECT  24 1.811 32.28 2.147 ;
     RECT  6.24 1.811 10.776 2.195 ;
     RECT  4.368 1.811 4.776 2.291 ;
     RECT  6.24 2.195 10.056 2.291 ;
     RECT  12.864 1.763 15.864 2.291 ;
     RECT  28.224 2.147 32.28 2.339 ;
     RECT  11.808 1.763 11.832 2.725 ;
     RECT  2.16 1.763 2.856 2.819 ;
     RECT  37.824 1.859 40.512 2.821 ;
     RECT  18.6 1.763 20.616 2.915 ;
     RECT  24 2.147 27.048 2.915 ;
     RECT  33.312 1.763 35.112 2.915 ;
     RECT  37.824 2.821 40.824 2.963 ;
     RECT  11.616 2.725 11.832 3.107 ;
     RECT  4.752 2.291 4.776 3.443 ;
     RECT  18.6 2.915 19.656 3.443 ;
     RECT  24 2.915 26.568 3.443 ;
     RECT  28.32 2.339 31.464 3.443 ;
     RECT  38.928 2.963 40.824 3.443 ;
     RECT  6.672 2.291 10.056 3.925 ;
     RECT  28.656 3.443 31.464 3.925 ;
     RECT  33.648 2.915 35.112 3.925 ;
     RECT  12.864 2.291 14.424 4.019 ;
     RECT  2.16 2.819 2.808 4.163 ;
     RECT  2.304 4.163 2.808 4.211 ;
     RECT  37.824 2.963 37.848 4.261 ;
     RECT  37.392 4.261 37.848 4.357 ;
     RECT  28.656 3.925 32.424 4.405 ;
     RECT  33.648 3.925 35.88 4.405 ;
     RECT  12.864 4.019 13.8 4.595 ;
     RECT  6.672 3.925 10.392 5.077 ;
     RECT  18.6 3.443 18.912 5.077 ;
     RECT  25.968 3.443 26.568 5.077 ;
     RECT  39.36 3.443 40.824 5.077 ;
     RECT  2.304 4.211 2.712 5.171 ;
     RECT  25.968 5.077 27.096 5.171 ;
     RECT  37.344 4.357 37.848 5.171 ;
     RECT  28.656 4.405 35.88 5.267 ;
     RECT  26.256 5.171 27.096 5.461 ;
     RECT  28.656 5.267 35.208 5.461 ;
     RECT  18.6 5.077 19.752 5.605 ;
     RECT  11.808 3.107 11.832 5.653 ;
     RECT  26.256 5.461 35.208 5.747 ;
     RECT  11.712 5.653 11.832 5.749 ;
     RECT  11.616 5.749 11.832 5.843 ;
     RECT  16.752 3.397 16.776 6.181 ;
     RECT  16.56 6.181 16.776 6.229 ;
     RECT  17.856 5.605 19.752 6.229 ;
     RECT  15.408 3.349 15.432 6.661 ;
     RECT  2.4 5.171 2.712 6.709 ;
     RECT  3.696 5.077 3.72 6.709 ;
     RECT  16.56 6.229 19.752 6.853 ;
     RECT  22.8 6.565 22.824 6.899 ;
     RECT  5.04 5.077 5.064 7.189 ;
     RECT  15.024 6.661 15.432 7.379 ;
     RECT  24 3.443 24.696 7.381 ;
     RECT  16.56 6.853 20.52 7.427 ;
     RECT  37.344 5.171 37.416 7.861 ;
     RECT  37.056 7.861 37.416 7.907 ;
     RECT  17.856 7.427 20.52 7.957 ;
     RECT  37.056 7.907 37.368 8.341 ;
     RECT  24 7.381 25.224 8.389 ;
     RECT  26.256 5.747 27.096 8.389 ;
     RECT  36.912 8.341 37.368 8.437 ;
     RECT  13.2 4.595 13.8 8.485 ;
     RECT  21.648 1.763 21.672 8.579 ;
     RECT  16.56 7.427 16.584 8.675 ;
     RECT  2.4 6.709 3.72 8.821 ;
     RECT  2.4 8.821 3.96 9.061 ;
     RECT  5.04 7.189 5.112 9.061 ;
     RECT  15.408 7.379 15.432 9.061 ;
     RECT  2.4 9.061 5.112 9.107 ;
     RECT  11.616 5.843 11.736 9.301 ;
     RECT  6.624 5.077 10.392 9.637 ;
     RECT  11.616 9.301 12.12 9.637 ;
     RECT  15.408 9.061 15.864 9.637 ;
     RECT  28.656 5.747 35.208 9.637 ;
     RECT  6.624 9.637 12.12 9.731 ;
     RECT  38.88 5.077 40.824 9.731 ;
     RECT  2.4 9.107 5.064 10.067 ;
     RECT  5.04 10.067 5.064 10.307 ;
     RECT  10.032 9.731 12.12 10.307 ;
     RECT  28.656 9.637 35.256 10.307 ;
     RECT  36.768 8.437 37.368 10.547 ;
     RECT  34.032 10.307 35.256 10.597 ;
     RECT  13.2 8.485 14.424 10.835 ;
     RECT  21.6 10.213 21.624 10.883 ;
     RECT  38.88 9.731 40.776 10.883 ;
     RECT  34.032 10.597 35.304 10.885 ;
     RECT  10.032 10.307 10.152 10.931 ;
     RECT  38.88 10.883 40.728 11.029 ;
     RECT  34.032 10.885 35.88 11.219 ;
     RECT  13.2 10.835 13.8 11.221 ;
     RECT  13.104 11.221 13.8 11.459 ;
     RECT  15.408 9.637 16.68 11.459 ;
     RECT  28.656 10.307 32.952 11.459 ;
     RECT  34.032 11.219 35.304 11.507 ;
     RECT  11.616 10.307 12.12 11.941 ;
     RECT  13.104 11.459 13.512 11.941 ;
     RECT  34.032 11.507 35.256 12.325 ;
     RECT  28.896 11.459 32.952 12.563 ;
     RECT  0.24 7.525 0.264 12.851 ;
     RECT  10.128 10.931 10.152 13.045 ;
     RECT  29.4 12.563 32.952 13.045 ;
     RECT  33.984 12.325 35.256 13.045 ;
     RECT  29.4 13.045 35.256 13.093 ;
     RECT  11.616 11.941 13.512 13.333 ;
     RECT  6.624 9.731 8.856 13.621 ;
     RECT  10.128 13.045 10.296 13.621 ;
     RECT  36.912 10.547 37.368 13.715 ;
     RECT  17.856 7.957 20.568 14.005 ;
     RECT  11.616 13.333 14.424 14.099 ;
     RECT  24 8.389 27.096 14.101 ;
     RECT  15.408 11.459 15.432 14.197 ;
     RECT  6.624 13.621 10.296 14.387 ;
     RECT  2.4 10.067 3.72 14.773 ;
     RECT  29.4 13.093 35.352 14.773 ;
     RECT  10.128 14.387 10.296 14.867 ;
     RECT  11.616 14.099 14.376 14.867 ;
     RECT  21.696 14.629 21.72 14.963 ;
     RECT  5.568 13.621 5.592 15.301 ;
     RECT  6.624 14.387 8.856 15.301 ;
     RECT  37.104 13.715 37.368 15.349 ;
     RECT  38.736 11.029 40.728 15.349 ;
     RECT  2.4 14.773 4.536 15.443 ;
     RECT  24 14.101 28.008 15.877 ;
     RECT  24 15.877 28.104 15.925 ;
     RECT  15.408 14.197 15.864 16.259 ;
     RECT  29.4 14.773 35.736 16.403 ;
     RECT  22.752 11.941 22.776 16.501 ;
     RECT  23.856 15.925 28.104 16.501 ;
     RECT  22.752 16.501 28.104 16.691 ;
     RECT  37.104 15.349 40.728 16.837 ;
     RECT  5.568 15.301 8.856 17.077 ;
     RECT  11.616 14.867 13.512 17.077 ;
     RECT  15.408 16.259 15.72 17.699 ;
     RECT  11.376 17.077 13.512 18.131 ;
     RECT  22.752 16.691 28.008 18.133 ;
     RECT  29.4 16.403 35.352 18.133 ;
     RECT  5.52 17.077 8.856 18.275 ;
     RECT  22.752 18.133 35.352 18.709 ;
     RECT  15.696 17.699 15.72 18.851 ;
     RECT  17.664 14.005 20.568 18.851 ;
     RECT  37.104 16.837 40.92 18.851 ;
     RECT  15.216 18.853 15.24 19.043 ;
     RECT  11.616 18.131 13.512 19.333 ;
     RECT  21.648 18.181 21.672 19.379 ;
     RECT  22.752 18.709 35.784 19.427 ;
     RECT  2.4 15.443 3.72 19.621 ;
     RECT  2.4 19.621 4.632 19.909 ;
     RECT  5.664 18.275 8.856 19.909 ;
     RECT  11.616 19.333 13.992 20.003 ;
     RECT  20.16 18.851 20.568 20.003 ;
     RECT  27.072 19.427 35.784 20.003 ;
     RECT  27.744 20.003 30.264 20.051 ;
     RECT  17.664 18.851 19.176 20.579 ;
     RECT  37.344 18.851 40.92 20.579 ;
     RECT  2.4 19.909 8.856 20.965 ;
     RECT  10.128 14.867 10.152 20.965 ;
     RECT  2.4 20.965 10.152 21.061 ;
     RECT  22.752 19.427 25.8 21.061 ;
     RECT  27.984 20.051 30.264 21.155 ;
     RECT  2.4 21.061 10.248 21.203 ;
     RECT  11.616 20.003 11.64 21.301 ;
     RECT  31.344 20.003 35.544 21.541 ;
     RECT  2.4 21.203 10.008 21.637 ;
     RECT  11.376 21.301 11.64 21.637 ;
     RECT  12.672 20.003 13.992 21.637 ;
     RECT  31.344 21.541 35.64 21.683 ;
     RECT  17.856 20.579 19.176 22.069 ;
     RECT  2.304 21.637 10.008 22.259 ;
     RECT  17.04 22.069 19.176 22.259 ;
     RECT  2.304 22.259 3.48 22.355 ;
     RECT  11.376 21.637 13.992 22.789 ;
     RECT  22.704 21.061 25.8 22.789 ;
     RECT  27.984 21.155 30.072 22.789 ;
     RECT  37.632 20.579 37.8 23.173 ;
     RECT  22.704 22.789 26.376 23.317 ;
     RECT  27.984 22.789 30.36 23.317 ;
     RECT  2.304 22.355 2.856 23.365 ;
     RECT  4.608 22.259 10.008 23.365 ;
     RECT  11.376 22.789 14.904 23.365 ;
     RECT  17.04 22.259 18.912 23.365 ;
     RECT  20.544 20.003 20.568 23.365 ;
     RECT  22.704 23.317 30.36 23.365 ;
     RECT  31.344 21.683 31.752 23.365 ;
     RECT  33.216 21.683 35.64 23.365 ;
     RECT  37.152 23.173 37.8 23.365 ;
     RECT  38.832 20.579 40.68 23.365 ;
     RECT  2.16 23.365 40.68 23.413 ;
     RECT  2.16 23.413 40.872 23.509 ;
     RECT  2.16 23.509 40.968 25.744 ;
     RECT  5.376 25.744 5.4 25.811 ;
     RECT  7.632 25.744 7.656 25.811 ;
     RECT  9.36 25.744 9.768 25.811 ;
     RECT  12.144 25.744 12.792 25.811 ;
     RECT  13.968 25.744 13.992 25.811 ;
     RECT  18.432 25.744 18.456 25.811 ;
     RECT  23.808 25.744 23.832 25.811 ;
     RECT  29.904 25.744 29.928 25.811 ;
     RECT  31.728 25.744 31.752 25.811 ;
     RECT  35.28 25.744 35.304 25.811 ;
     RECT  12.768 25.811 12.792 25.859 ;
     RECT  15.864 0.323 16.944 1.763 ;
     RECT  17.064 1.187 18.384 1.763 ;
     RECT  35.64 1.715 36.672 1.763 ;
     RECT  2.856 1.763 4.272 1.811 ;
     RECT  10.776 1.763 11.808 2.195 ;
     RECT  11.832 1.763 12.864 4.595 ;
     RECT  15.864 1.763 17.04 1.811 ;
     RECT  20.616 1.763 21.648 2.915 ;
     RECT  21.672 1.763 22.704 1.811 ;
     RECT  32.28 1.763 33.312 2.339 ;
     RECT  40.68 1.763 40.824 1.859 ;
     RECT  2.856 1.811 4.368 2.291 ;
     RECT  4.776 1.811 6.24 2.291 ;
     RECT  21.672 1.811 22.8 1.859 ;
     RECT  22.824 1.811 24 1.859 ;
     RECT  40.512 1.859 40.824 2.821 ;
     RECT  27.048 2.147 28.224 2.339 ;
     RECT  11.616 2.195 11.808 2.725 ;
     RECT  14.424 2.291 15.864 3.349 ;
     RECT  27.048 2.339 28.32 2.915 ;
     RECT  33.312 2.915 33.648 3.925 ;
     RECT  37.848 2.963 38.928 3.443 ;
     RECT  11.616 3.107 11.808 3.925 ;
     RECT  14.424 3.349 15.408 4.019 ;
     RECT  15.432 3.349 15.864 3.397 ;
     RECT  15.432 3.397 16.752 6.181 ;
     RECT  24.696 3.443 25.968 5.171 ;
     RECT  37.848 3.443 39.36 5.077 ;
     RECT  10.392 3.925 11.808 5.653 ;
     RECT  32.424 3.925 33.648 4.405 ;
     RECT  2.712 4.211 2.808 5.077 ;
     RECT  35.88 4.261 37.392 4.357 ;
     RECT  35.88 4.357 37.344 5.267 ;
     RECT  11.832 4.595 13.2 5.843 ;
     RECT  2.712 5.077 3.696 6.709 ;
     RECT  3.72 5.077 5.04 8.821 ;
     RECT  37.848 5.077 38.88 5.171 ;
     RECT  37.416 5.171 38.88 7.907 ;
     RECT  16.776 5.605 17.856 6.229 ;
     RECT  10.392 5.653 11.712 5.749 ;
     RECT  10.392 5.749 11.616 9.637 ;
     RECT  11.736 5.843 13.2 9.301 ;
     RECT  15.432 6.181 16.56 8.675 ;
     RECT  21.672 6.565 22.8 6.899 ;
     RECT  22.824 6.565 24 6.899 ;
     RECT  13.8 6.661 15.024 7.379 ;
     RECT  20.52 6.853 21.648 7.957 ;
     RECT  5.112 7.189 6.624 9.107 ;
     RECT  13.8 7.379 15.408 8.485 ;
     RECT  25.224 7.381 26.256 8.389 ;
     RECT  16.584 7.427 17.856 8.675 ;
     RECT  37.368 7.907 38.88 11.029 ;
     RECT  20.568 7.957 21.648 8.579 ;
     RECT  14.424 8.485 15.408 10.835 ;
     RECT  15.432 8.675 17.856 9.061 ;
     RECT  3.96 8.821 5.04 9.061 ;
     RECT  15.864 9.061 17.856 9.637 ;
     RECT  12.12 9.301 13.2 11.221 ;
     RECT  16.68 9.637 17.856 11.459 ;
     RECT  35.256 9.637 36.768 10.547 ;
     RECT  8.856 9.731 10.032 10.931 ;
     RECT  3.72 10.067 5.04 10.307 ;
     RECT  20.568 10.213 21.6 10.883 ;
     RECT  10.152 10.307 11.616 13.045 ;
     RECT  32.952 10.307 34.032 12.325 ;
     RECT  35.256 10.547 36.912 10.597 ;
     RECT  35.304 10.597 36.912 10.885 ;
     RECT  35.88 10.885 36.912 11.219 ;
     RECT  8.856 10.931 10.128 13.621 ;
     RECT  37.368 11.029 38.736 15.349 ;
     RECT  12.12 11.221 13.104 11.941 ;
     RECT  22.776 11.941 24 15.925 ;
     RECT  32.952 12.325 33.984 13.045 ;
     RECT  10.296 13.045 11.616 14.867 ;
     RECT  14.424 13.333 15.408 14.099 ;
     RECT  5.592 13.621 6.624 15.301 ;
     RECT  36.912 13.715 37.104 14.773 ;
     RECT  14.376 14.099 15.408 14.867 ;
     RECT  28.008 14.101 29.4 15.877 ;
     RECT  8.856 14.387 10.128 20.965 ;
     RECT  20.568 14.629 21.696 14.963 ;
     RECT  21.72 14.629 22.752 14.963 ;
     RECT  4.536 14.773 5.568 15.443 ;
     RECT  35.736 14.773 37.104 16.403 ;
     RECT  10.152 14.867 11.616 17.077 ;
     RECT  28.104 15.877 29.4 16.691 ;
     RECT  22.776 15.925 23.856 16.501 ;
     RECT  28.008 16.691 29.4 18.133 ;
     RECT  10.152 17.077 11.376 18.131 ;
     RECT  10.152 18.131 11.616 21.061 ;
     RECT  20.568 18.181 21.648 19.379 ;
     RECT  21.672 18.181 22.752 19.379 ;
     RECT  5.52 18.275 5.664 19.621 ;
     RECT  35.784 18.709 37.104 18.851 ;
     RECT  19.176 18.851 20.16 20.003 ;
     RECT  25.8 19.427 27.072 20.003 ;
     RECT  4.632 19.621 5.664 19.909 ;
     RECT  11.64 20.003 12.672 21.637 ;
     RECT  19.176 20.003 20.544 22.259 ;
     RECT  30.264 20.003 31.344 21.155 ;
     RECT  17.664 20.579 17.856 22.069 ;
     RECT  37.8 20.579 38.832 23.365 ;
     RECT  10.248 21.061 11.616 21.203 ;
     RECT  30.072 21.155 31.344 22.789 ;
     RECT  10.008 21.203 11.616 21.301 ;
     RECT  10.008 21.301 11.376 23.365 ;
     RECT  31.752 21.683 33.216 23.365 ;
     RECT  3.48 22.259 4.608 22.355 ;
     RECT  18.912 22.259 20.544 23.365 ;
     RECT  2.856 22.355 4.608 23.365 ;
     RECT  30.36 22.789 31.344 23.365 ;
     RECT  35.64 23.173 37.152 23.365 ;
     RECT  12.792 25.744 12.816 25.811 ;
     RECT  13.032 25.744 13.104 25.811 ;
     RECT  13.224 25.744 13.296 25.811 ;
     RECT  13.512 25.744 13.584 25.811 ;
     RECT  13.704 25.744 13.776 25.811 ;
  END
END dsfd_vm_fxb
END LIBRARY
